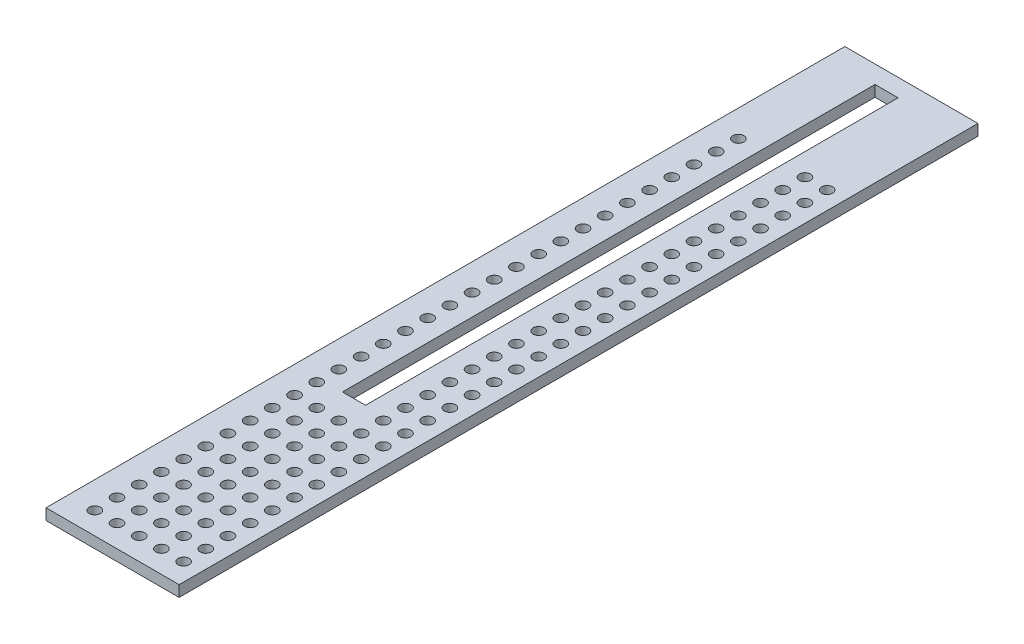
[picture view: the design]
ISO-10303-21;
HEADER;
FILE_DESCRIPTION(('STEP AP214'),'2;1');
FILE_NAME('part.step','',(''),(''),'','','');
FILE_SCHEMA(('AUTOMOTIVE_DESIGN { 1 0 10303 214 1 1 1 1 }'));
ENDSEC;
DATA;
#1=APPLICATION_CONTEXT('core data for automotive mechanical design processes');
#2=APPLICATION_PROTOCOL_DEFINITION('international standard','automotive_design',2000,#1);
#3=PRODUCT_CONTEXT('',#1,'mechanical');
#4=PRODUCT('Part','Part','',(#3));
#5=PRODUCT_RELATED_PRODUCT_CATEGORY('part','',(#4));
#6=PRODUCT_DEFINITION_FORMATION('','',#4);
#7=PRODUCT_DEFINITION_CONTEXT('part definition',#1,'design');
#8=PRODUCT_DEFINITION('design','',#6,#7);
#9=PRODUCT_DEFINITION_SHAPE('','',#8);
#10=(LENGTH_UNIT() NAMED_UNIT(*) SI_UNIT(.MILLI.,.METRE.));
#11=(NAMED_UNIT(*) PLANE_ANGLE_UNIT() SI_UNIT($,.RADIAN.));
#12=(NAMED_UNIT(*) SI_UNIT($,.STERADIAN.) SOLID_ANGLE_UNIT());
#13=UNCERTAINTY_MEASURE_WITH_UNIT(LENGTH_MEASURE(1.E-05),#10,'distance_accuracy_value','');
#14=(GEOMETRIC_REPRESENTATION_CONTEXT(3) GLOBAL_UNCERTAINTY_ASSIGNED_CONTEXT((#13)) GLOBAL_UNIT_ASSIGNED_CONTEXT((#10,
#11,#12)) REPRESENTATION_CONTEXT('',''));
#15=CARTESIAN_POINT('',(0.,0.,0.));
#16=DIRECTION('',(0.,0.,1.));
#17=DIRECTION('',(1.,0.,0.));
#18=AXIS2_PLACEMENT_3D('',#15,#16,#17);
#19=CARTESIAN_POINT('',(-1.58749999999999,50.7999999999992,228.6));
#20=DIRECTION('',(0.,-1.,0.));
#21=DIRECTION('',(1.,0.,0.));
#22=AXIS2_PLACEMENT_3D('',#19,#20,#21);
#23=PLANE('',#22);
#24=CARTESIAN_POINT('',(12.3825,50.7999999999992,222.25));
#25=DIRECTION('',(0.,1.,0.));
#26=DIRECTION('',(-1.,0.,0.));
#27=AXIS2_PLACEMENT_3D('',#24,#25,#26);
#28=CIRCLE('',#27,1.5875);
#29=CARTESIAN_POINT('',(10.795,50.7999999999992,222.25));
#30=VERTEX_POINT('',#29);
#31=EDGE_CURVE('E152',#30,#30,#28,.T.);
#32=ORIENTED_EDGE('',*,*,#31,.F.);
#33=EDGE_LOOP('',(#32));
#34=FACE_BOUND('',#33,.T.);
#35=CARTESIAN_POINT('',(18.7325,50.7999999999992,222.25));
#36=DIRECTION('',(0.,1.,0.));
#37=DIRECTION('',(-1.,0.,0.));
#38=AXIS2_PLACEMENT_3D('',#35,#36,#37);
#39=CIRCLE('',#38,1.5875);
#40=CARTESIAN_POINT('',(17.145,50.7999999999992,222.25));
#41=VERTEX_POINT('',#40);
#42=EDGE_CURVE('E156',#41,#41,#39,.T.);
#43=ORIENTED_EDGE('',*,*,#42,.F.);
#44=EDGE_LOOP('',(#43));
#45=FACE_BOUND('',#44,.T.);
#46=CARTESIAN_POINT('',(25.0825,50.7999999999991,222.25));
#47=DIRECTION('',(0.,1.,0.));
#48=DIRECTION('',(-1.,0.,0.));
#49=AXIS2_PLACEMENT_3D('',#46,#47,#48);
#50=CIRCLE('',#49,1.5875);
#51=CARTESIAN_POINT('',(23.495,50.7999999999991,222.25));
#52=VERTEX_POINT('',#51);
#53=EDGE_CURVE('E160',#52,#52,#50,.T.);
#54=ORIENTED_EDGE('',*,*,#53,.F.);
#55=EDGE_LOOP('',(#54));
#56=FACE_BOUND('',#55,.T.);
#57=CARTESIAN_POINT('',(31.4325,50.7999999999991,222.25));
#58=DIRECTION('',(0.,1.,0.));
#59=DIRECTION('',(-1.,0.,0.));
#60=AXIS2_PLACEMENT_3D('',#57,#58,#59);
#61=CIRCLE('',#60,1.5875);
#62=CARTESIAN_POINT('',(29.845,50.7999999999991,222.25));
#63=VERTEX_POINT('',#62);
#64=EDGE_CURVE('E164',#63,#63,#61,.T.);
#65=ORIENTED_EDGE('',*,*,#64,.F.);
#66=EDGE_LOOP('',(#65));
#67=FACE_BOUND('',#66,.T.);
#68=CARTESIAN_POINT('',(12.3825,50.7999999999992,215.9));
#69=DIRECTION('',(0.,1.,0.));
#70=DIRECTION('',(-1.,0.,0.));
#71=AXIS2_PLACEMENT_3D('',#68,#69,#70);
#72=CIRCLE('',#71,1.5875);
#73=CARTESIAN_POINT('',(10.795,50.7999999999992,215.9));
#74=VERTEX_POINT('',#73);
#75=EDGE_CURVE('E168',#74,#74,#72,.T.);
#76=ORIENTED_EDGE('',*,*,#75,.F.);
#77=EDGE_LOOP('',(#76));
#78=FACE_BOUND('',#77,.T.);
#79=CARTESIAN_POINT('',(18.7325,50.7999999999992,215.9));
#80=DIRECTION('',(0.,1.,0.));
#81=DIRECTION('',(-1.,0.,0.));
#82=AXIS2_PLACEMENT_3D('',#79,#80,#81);
#83=CIRCLE('',#82,1.5875);
#84=CARTESIAN_POINT('',(17.145,50.7999999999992,215.9));
#85=VERTEX_POINT('',#84);
#86=EDGE_CURVE('E172',#85,#85,#83,.T.);
#87=ORIENTED_EDGE('',*,*,#86,.F.);
#88=EDGE_LOOP('',(#87));
#89=FACE_BOUND('',#88,.T.);
#90=CARTESIAN_POINT('',(25.0825,50.7999999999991,215.9));
#91=DIRECTION('',(0.,1.,0.));
#92=DIRECTION('',(-1.,0.,0.));
#93=AXIS2_PLACEMENT_3D('',#90,#91,#92);
#94=CIRCLE('',#93,1.5875);
#95=CARTESIAN_POINT('',(23.495,50.7999999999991,215.9));
#96=VERTEX_POINT('',#95);
#97=EDGE_CURVE('E176',#96,#96,#94,.T.);
#98=ORIENTED_EDGE('',*,*,#97,.F.);
#99=EDGE_LOOP('',(#98));
#100=FACE_BOUND('',#99,.T.);
#101=CARTESIAN_POINT('',(31.4325,50.7999999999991,215.9));
#102=DIRECTION('',(0.,1.,0.));
#103=DIRECTION('',(-1.,0.,0.));
#104=AXIS2_PLACEMENT_3D('',#101,#102,#103);
#105=CIRCLE('',#104,1.58750000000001);
#106=CARTESIAN_POINT('',(29.845,50.7999999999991,215.9));
#107=VERTEX_POINT('',#106);
#108=EDGE_CURVE('E180',#107,#107,#105,.T.);
#109=ORIENTED_EDGE('',*,*,#108,.F.);
#110=EDGE_LOOP('',(#109));
#111=FACE_BOUND('',#110,.T.);
#112=CARTESIAN_POINT('',(12.3825,50.7999999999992,209.55));
#113=DIRECTION('',(0.,1.,0.));
#114=DIRECTION('',(-1.,0.,0.));
#115=AXIS2_PLACEMENT_3D('',#112,#113,#114);
#116=CIRCLE('',#115,1.5875);
#117=CARTESIAN_POINT('',(10.795,50.7999999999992,209.55));
#118=VERTEX_POINT('',#117);
#119=EDGE_CURVE('E184',#118,#118,#116,.T.);
#120=ORIENTED_EDGE('',*,*,#119,.F.);
#121=EDGE_LOOP('',(#120));
#122=FACE_BOUND('',#121,.T.);
#123=CARTESIAN_POINT('',(18.7325,50.7999999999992,209.55));
#124=DIRECTION('',(0.,1.,0.));
#125=DIRECTION('',(-1.,0.,0.));
#126=AXIS2_PLACEMENT_3D('',#123,#124,#125);
#127=CIRCLE('',#126,1.5875);
#128=CARTESIAN_POINT('',(17.145,50.7999999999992,209.55));
#129=VERTEX_POINT('',#128);
#130=EDGE_CURVE('E188',#129,#129,#127,.T.);
#131=ORIENTED_EDGE('',*,*,#130,.F.);
#132=EDGE_LOOP('',(#131));
#133=FACE_BOUND('',#132,.T.);
#134=CARTESIAN_POINT('',(25.0825,50.7999999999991,209.55));
#135=DIRECTION('',(0.,1.,0.));
#136=DIRECTION('',(-1.,0.,0.));
#137=AXIS2_PLACEMENT_3D('',#134,#135,#136);
#138=CIRCLE('',#137,1.5875);
#139=CARTESIAN_POINT('',(23.495,50.7999999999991,209.55));
#140=VERTEX_POINT('',#139);
#141=EDGE_CURVE('E192',#140,#140,#138,.T.);
#142=ORIENTED_EDGE('',*,*,#141,.F.);
#143=EDGE_LOOP('',(#142));
#144=FACE_BOUND('',#143,.T.);
#145=CARTESIAN_POINT('',(31.4325,50.7999999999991,209.55));
#146=DIRECTION('',(0.,1.,0.));
#147=DIRECTION('',(-1.,0.,0.));
#148=AXIS2_PLACEMENT_3D('',#145,#146,#147);
#149=CIRCLE('',#148,1.5875);
#150=CARTESIAN_POINT('',(29.845,50.7999999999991,209.55));
#151=VERTEX_POINT('',#150);
#152=EDGE_CURVE('E196',#151,#151,#149,.T.);
#153=ORIENTED_EDGE('',*,*,#152,.F.);
#154=EDGE_LOOP('',(#153));
#155=FACE_BOUND('',#154,.T.);
#156=CARTESIAN_POINT('',(12.3824999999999,50.7999999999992,203.2));
#157=DIRECTION('',(0.,1.,0.));
#158=DIRECTION('',(-1.,0.,0.));
#159=AXIS2_PLACEMENT_3D('',#156,#157,#158);
#160=CIRCLE('',#159,1.5875);
#161=CARTESIAN_POINT('',(10.7949999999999,50.7999999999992,203.2));
#162=VERTEX_POINT('',#161);
#163=EDGE_CURVE('E200',#162,#162,#160,.T.);
#164=ORIENTED_EDGE('',*,*,#163,.F.);
#165=EDGE_LOOP('',(#164));
#166=FACE_BOUND('',#165,.T.);
#167=CARTESIAN_POINT('',(18.7324999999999,50.7999999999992,203.2));
#168=DIRECTION('',(0.,1.,0.));
#169=DIRECTION('',(-1.,0.,0.));
#170=AXIS2_PLACEMENT_3D('',#167,#168,#169);
#171=CIRCLE('',#170,1.5875);
#172=CARTESIAN_POINT('',(17.1449999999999,50.7999999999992,203.2));
#173=VERTEX_POINT('',#172);
#174=EDGE_CURVE('E204',#173,#173,#171,.T.);
#175=ORIENTED_EDGE('',*,*,#174,.F.);
#176=EDGE_LOOP('',(#175));
#177=FACE_BOUND('',#176,.T.);
#178=CARTESIAN_POINT('',(25.0824999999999,50.7999999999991,203.2));
#179=DIRECTION('',(0.,1.,0.));
#180=DIRECTION('',(-1.,0.,0.));
#181=AXIS2_PLACEMENT_3D('',#178,#179,#180);
#182=CIRCLE('',#181,1.5875);
#183=CARTESIAN_POINT('',(23.4949999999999,50.7999999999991,203.2));
#184=VERTEX_POINT('',#183);
#185=EDGE_CURVE('E208',#184,#184,#182,.T.);
#186=ORIENTED_EDGE('',*,*,#185,.F.);
#187=EDGE_LOOP('',(#186));
#188=FACE_BOUND('',#187,.T.);
#189=CARTESIAN_POINT('',(31.4324999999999,50.7999999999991,203.2));
#190=DIRECTION('',(0.,1.,0.));
#191=DIRECTION('',(-1.,0.,0.));
#192=AXIS2_PLACEMENT_3D('',#189,#190,#191);
#193=CIRCLE('',#192,1.5875);
#194=CARTESIAN_POINT('',(29.8449999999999,50.7999999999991,203.2));
#195=VERTEX_POINT('',#194);
#196=EDGE_CURVE('E212',#195,#195,#193,.T.);
#197=ORIENTED_EDGE('',*,*,#196,.F.);
#198=EDGE_LOOP('',(#197));
#199=FACE_BOUND('',#198,.T.);
#200=CARTESIAN_POINT('',(12.3824999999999,50.7999999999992,196.85));
#201=DIRECTION('',(0.,1.,0.));
#202=DIRECTION('',(-1.,0.,0.));
#203=AXIS2_PLACEMENT_3D('',#200,#201,#202);
#204=CIRCLE('',#203,1.5875);
#205=CARTESIAN_POINT('',(10.7949999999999,50.7999999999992,196.85));
#206=VERTEX_POINT('',#205);
#207=EDGE_CURVE('E216',#206,#206,#204,.T.);
#208=ORIENTED_EDGE('',*,*,#207,.F.);
#209=EDGE_LOOP('',(#208));
#210=FACE_BOUND('',#209,.T.);
#211=CARTESIAN_POINT('',(18.7324999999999,50.7999999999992,196.85));
#212=DIRECTION('',(0.,1.,0.));
#213=DIRECTION('',(-1.,0.,0.));
#214=AXIS2_PLACEMENT_3D('',#211,#212,#213);
#215=CIRCLE('',#214,1.5875);
#216=CARTESIAN_POINT('',(17.1449999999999,50.7999999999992,196.85));
#217=VERTEX_POINT('',#216);
#218=EDGE_CURVE('E220',#217,#217,#215,.T.);
#219=ORIENTED_EDGE('',*,*,#218,.F.);
#220=EDGE_LOOP('',(#219));
#221=FACE_BOUND('',#220,.T.);
#222=CARTESIAN_POINT('',(25.0824999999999,50.7999999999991,196.85));
#223=DIRECTION('',(0.,1.,0.));
#224=DIRECTION('',(-1.,0.,0.));
#225=AXIS2_PLACEMENT_3D('',#222,#223,#224);
#226=CIRCLE('',#225,1.5875);
#227=CARTESIAN_POINT('',(23.4949999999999,50.7999999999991,196.85));
#228=VERTEX_POINT('',#227);
#229=EDGE_CURVE('E224',#228,#228,#226,.T.);
#230=ORIENTED_EDGE('',*,*,#229,.F.);
#231=EDGE_LOOP('',(#230));
#232=FACE_BOUND('',#231,.T.);
#233=CARTESIAN_POINT('',(31.4324999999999,50.7999999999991,196.85));
#234=DIRECTION('',(0.,1.,0.));
#235=DIRECTION('',(-1.,0.,0.));
#236=AXIS2_PLACEMENT_3D('',#233,#234,#235);
#237=CIRCLE('',#236,1.58750000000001);
#238=CARTESIAN_POINT('',(29.8449999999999,50.7999999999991,196.85));
#239=VERTEX_POINT('',#238);
#240=EDGE_CURVE('E228',#239,#239,#237,.T.);
#241=ORIENTED_EDGE('',*,*,#240,.F.);
#242=EDGE_LOOP('',(#241));
#243=FACE_BOUND('',#242,.T.);
#244=CARTESIAN_POINT('',(12.3824999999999,50.7999999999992,190.5));
#245=DIRECTION('',(0.,1.,0.));
#246=DIRECTION('',(-1.,0.,0.));
#247=AXIS2_PLACEMENT_3D('',#244,#245,#246);
#248=CIRCLE('',#247,1.5875);
#249=CARTESIAN_POINT('',(10.7949999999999,50.7999999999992,190.5));
#250=VERTEX_POINT('',#249);
#251=EDGE_CURVE('E232',#250,#250,#248,.T.);
#252=ORIENTED_EDGE('',*,*,#251,.F.);
#253=EDGE_LOOP('',(#252));
#254=FACE_BOUND('',#253,.T.);
#255=CARTESIAN_POINT('',(18.7324999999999,50.7999999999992,190.5));
#256=DIRECTION('',(0.,1.,0.));
#257=DIRECTION('',(-1.,0.,0.));
#258=AXIS2_PLACEMENT_3D('',#255,#256,#257);
#259=CIRCLE('',#258,1.5875);
#260=CARTESIAN_POINT('',(17.1449999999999,50.7999999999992,190.5));
#261=VERTEX_POINT('',#260);
#262=EDGE_CURVE('E236',#261,#261,#259,.T.);
#263=ORIENTED_EDGE('',*,*,#262,.F.);
#264=EDGE_LOOP('',(#263));
#265=FACE_BOUND('',#264,.T.);
#266=CARTESIAN_POINT('',(25.0824999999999,50.7999999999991,190.5));
#267=DIRECTION('',(0.,1.,0.));
#268=DIRECTION('',(-1.,0.,0.));
#269=AXIS2_PLACEMENT_3D('',#266,#267,#268);
#270=CIRCLE('',#269,1.5875);
#271=CARTESIAN_POINT('',(23.4949999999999,50.7999999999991,190.5));
#272=VERTEX_POINT('',#271);
#273=EDGE_CURVE('E240',#272,#272,#270,.T.);
#274=ORIENTED_EDGE('',*,*,#273,.F.);
#275=EDGE_LOOP('',(#274));
#276=FACE_BOUND('',#275,.T.);
#277=CARTESIAN_POINT('',(31.4324999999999,50.7999999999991,190.5));
#278=DIRECTION('',(0.,1.,0.));
#279=DIRECTION('',(-1.,0.,0.));
#280=AXIS2_PLACEMENT_3D('',#277,#278,#279);
#281=CIRCLE('',#280,1.5875);
#282=CARTESIAN_POINT('',(29.8449999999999,50.7999999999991,190.5));
#283=VERTEX_POINT('',#282);
#284=EDGE_CURVE('E244',#283,#283,#281,.T.);
#285=ORIENTED_EDGE('',*,*,#284,.F.);
#286=EDGE_LOOP('',(#285));
#287=FACE_BOUND('',#286,.T.);
#288=CARTESIAN_POINT('',(12.3824999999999,50.7999999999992,184.15));
#289=DIRECTION('',(0.,1.,0.));
#290=DIRECTION('',(-1.,0.,0.));
#291=AXIS2_PLACEMENT_3D('',#288,#289,#290);
#292=CIRCLE('',#291,1.5875);
#293=CARTESIAN_POINT('',(10.7949999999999,50.7999999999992,184.15));
#294=VERTEX_POINT('',#293);
#295=EDGE_CURVE('E248',#294,#294,#292,.T.);
#296=ORIENTED_EDGE('',*,*,#295,.F.);
#297=EDGE_LOOP('',(#296));
#298=FACE_BOUND('',#297,.T.);
#299=CARTESIAN_POINT('',(18.7324999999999,50.7999999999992,184.15));
#300=DIRECTION('',(0.,1.,0.));
#301=DIRECTION('',(-1.,0.,0.));
#302=AXIS2_PLACEMENT_3D('',#299,#300,#301);
#303=CIRCLE('',#302,1.5875);
#304=CARTESIAN_POINT('',(17.1449999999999,50.7999999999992,184.15));
#305=VERTEX_POINT('',#304);
#306=EDGE_CURVE('E252',#305,#305,#303,.T.);
#307=ORIENTED_EDGE('',*,*,#306,.F.);
#308=EDGE_LOOP('',(#307));
#309=FACE_BOUND('',#308,.T.);
#310=CARTESIAN_POINT('',(25.0824999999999,50.7999999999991,184.15));
#311=DIRECTION('',(0.,1.,0.));
#312=DIRECTION('',(-1.,0.,0.));
#313=AXIS2_PLACEMENT_3D('',#310,#311,#312);
#314=CIRCLE('',#313,1.5875);
#315=CARTESIAN_POINT('',(23.4949999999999,50.7999999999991,184.15));
#316=VERTEX_POINT('',#315);
#317=EDGE_CURVE('E256',#316,#316,#314,.T.);
#318=ORIENTED_EDGE('',*,*,#317,.F.);
#319=EDGE_LOOP('',(#318));
#320=FACE_BOUND('',#319,.T.);
#321=CARTESIAN_POINT('',(31.4324999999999,50.7999999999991,184.15));
#322=DIRECTION('',(0.,1.,0.));
#323=DIRECTION('',(-1.,0.,0.));
#324=AXIS2_PLACEMENT_3D('',#321,#322,#323);
#325=CIRCLE('',#324,1.58750000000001);
#326=CARTESIAN_POINT('',(29.8449999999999,50.7999999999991,184.15));
#327=VERTEX_POINT('',#326);
#328=EDGE_CURVE('E260',#327,#327,#325,.T.);
#329=ORIENTED_EDGE('',*,*,#328,.F.);
#330=EDGE_LOOP('',(#329));
#331=FACE_BOUND('',#330,.T.);
#332=CARTESIAN_POINT('',(12.3824999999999,50.7999999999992,177.8));
#333=DIRECTION('',(0.,1.,0.));
#334=DIRECTION('',(-1.,0.,0.));
#335=AXIS2_PLACEMENT_3D('',#332,#333,#334);
#336=CIRCLE('',#335,1.5875);
#337=CARTESIAN_POINT('',(10.7949999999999,50.7999999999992,177.8));
#338=VERTEX_POINT('',#337);
#339=EDGE_CURVE('E264',#338,#338,#336,.T.);
#340=ORIENTED_EDGE('',*,*,#339,.F.);
#341=EDGE_LOOP('',(#340));
#342=FACE_BOUND('',#341,.T.);
#343=CARTESIAN_POINT('',(18.7324999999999,50.7999999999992,177.8));
#344=DIRECTION('',(0.,1.,0.));
#345=DIRECTION('',(-1.,0.,0.));
#346=AXIS2_PLACEMENT_3D('',#343,#344,#345);
#347=CIRCLE('',#346,1.5875);
#348=CARTESIAN_POINT('',(17.1449999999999,50.7999999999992,177.8));
#349=VERTEX_POINT('',#348);
#350=EDGE_CURVE('E268',#349,#349,#347,.T.);
#351=ORIENTED_EDGE('',*,*,#350,.F.);
#352=EDGE_LOOP('',(#351));
#353=FACE_BOUND('',#352,.T.);
#354=CARTESIAN_POINT('',(25.0824999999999,50.7999999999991,177.8));
#355=DIRECTION('',(0.,1.,0.));
#356=DIRECTION('',(-1.,0.,0.));
#357=AXIS2_PLACEMENT_3D('',#354,#355,#356);
#358=CIRCLE('',#357,1.5875);
#359=CARTESIAN_POINT('',(23.4949999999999,50.7999999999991,177.8));
#360=VERTEX_POINT('',#359);
#361=EDGE_CURVE('E272',#360,#360,#358,.T.);
#362=ORIENTED_EDGE('',*,*,#361,.F.);
#363=EDGE_LOOP('',(#362));
#364=FACE_BOUND('',#363,.T.);
#365=CARTESIAN_POINT('',(31.4324999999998,50.7999999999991,177.8));
#366=DIRECTION('',(0.,1.,0.));
#367=DIRECTION('',(-1.,0.,0.));
#368=AXIS2_PLACEMENT_3D('',#365,#366,#367);
#369=CIRCLE('',#368,1.5875);
#370=CARTESIAN_POINT('',(29.8449999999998,50.7999999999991,177.8));
#371=VERTEX_POINT('',#370);
#372=EDGE_CURVE('E276',#371,#371,#369,.T.);
#373=ORIENTED_EDGE('',*,*,#372,.F.);
#374=EDGE_LOOP('',(#373));
#375=FACE_BOUND('',#374,.T.);
#376=CARTESIAN_POINT('',(12.3824999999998,50.7999999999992,171.45));
#377=DIRECTION('',(0.,1.,0.));
#378=DIRECTION('',(-1.,0.,0.));
#379=AXIS2_PLACEMENT_3D('',#376,#377,#378);
#380=CIRCLE('',#379,1.5875);
#381=CARTESIAN_POINT('',(10.7949999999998,50.7999999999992,171.45));
#382=VERTEX_POINT('',#381);
#383=EDGE_CURVE('E280',#382,#382,#380,.T.);
#384=ORIENTED_EDGE('',*,*,#383,.F.);
#385=EDGE_LOOP('',(#384));
#386=FACE_BOUND('',#385,.T.);
#387=CARTESIAN_POINT('',(18.7324999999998,50.7999999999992,171.45));
#388=DIRECTION('',(0.,1.,0.));
#389=DIRECTION('',(-1.,0.,0.));
#390=AXIS2_PLACEMENT_3D('',#387,#388,#389);
#391=CIRCLE('',#390,1.5875);
#392=CARTESIAN_POINT('',(17.1449999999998,50.7999999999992,171.45));
#393=VERTEX_POINT('',#392);
#394=EDGE_CURVE('E284',#393,#393,#391,.T.);
#395=ORIENTED_EDGE('',*,*,#394,.F.);
#396=EDGE_LOOP('',(#395));
#397=FACE_BOUND('',#396,.T.);
#398=CARTESIAN_POINT('',(25.0824999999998,50.7999999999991,171.45));
#399=DIRECTION('',(0.,1.,0.));
#400=DIRECTION('',(-1.,0.,0.));
#401=AXIS2_PLACEMENT_3D('',#398,#399,#400);
#402=CIRCLE('',#401,1.5875);
#403=CARTESIAN_POINT('',(23.4949999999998,50.7999999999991,171.45));
#404=VERTEX_POINT('',#403);
#405=EDGE_CURVE('E288',#404,#404,#402,.T.);
#406=ORIENTED_EDGE('',*,*,#405,.F.);
#407=EDGE_LOOP('',(#406));
#408=FACE_BOUND('',#407,.T.);
#409=CARTESIAN_POINT('',(31.4324999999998,50.7999999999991,171.45));
#410=DIRECTION('',(0.,1.,0.));
#411=DIRECTION('',(-1.,0.,0.));
#412=AXIS2_PLACEMENT_3D('',#409,#410,#411);
#413=CIRCLE('',#412,1.5875);
#414=CARTESIAN_POINT('',(29.8449999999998,50.7999999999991,171.45));
#415=VERTEX_POINT('',#414);
#416=EDGE_CURVE('E292',#415,#415,#413,.T.);
#417=ORIENTED_EDGE('',*,*,#416,.F.);
#418=EDGE_LOOP('',(#417));
#419=FACE_BOUND('',#418,.T.);
#420=CARTESIAN_POINT('',(12.3824999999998,50.7999999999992,165.1));
#421=DIRECTION('',(0.,1.,0.));
#422=DIRECTION('',(-1.,0.,0.));
#423=AXIS2_PLACEMENT_3D('',#420,#421,#422);
#424=CIRCLE('',#423,1.5875);
#425=CARTESIAN_POINT('',(10.7949999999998,50.7999999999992,165.1));
#426=VERTEX_POINT('',#425);
#427=EDGE_CURVE('E296',#426,#426,#424,.T.);
#428=ORIENTED_EDGE('',*,*,#427,.F.);
#429=EDGE_LOOP('',(#428));
#430=FACE_BOUND('',#429,.T.);
#431=CARTESIAN_POINT('',(18.7324999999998,50.7999999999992,165.1));
#432=DIRECTION('',(0.,1.,0.));
#433=DIRECTION('',(-1.,0.,0.));
#434=AXIS2_PLACEMENT_3D('',#431,#432,#433);
#435=CIRCLE('',#434,1.5875);
#436=CARTESIAN_POINT('',(17.1449999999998,50.7999999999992,165.1));
#437=VERTEX_POINT('',#436);
#438=EDGE_CURVE('E300',#437,#437,#435,.T.);
#439=ORIENTED_EDGE('',*,*,#438,.F.);
#440=EDGE_LOOP('',(#439));
#441=FACE_BOUND('',#440,.T.);
#442=CARTESIAN_POINT('',(25.0824999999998,50.7999999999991,165.1));
#443=DIRECTION('',(0.,1.,0.));
#444=DIRECTION('',(-1.,0.,0.));
#445=AXIS2_PLACEMENT_3D('',#442,#443,#444);
#446=CIRCLE('',#445,1.5875);
#447=CARTESIAN_POINT('',(23.4949999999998,50.7999999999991,165.1));
#448=VERTEX_POINT('',#447);
#449=EDGE_CURVE('E304',#448,#448,#446,.T.);
#450=ORIENTED_EDGE('',*,*,#449,.F.);
#451=EDGE_LOOP('',(#450));
#452=FACE_BOUND('',#451,.T.);
#453=CARTESIAN_POINT('',(31.4324999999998,50.7999999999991,165.1));
#454=DIRECTION('',(0.,1.,0.));
#455=DIRECTION('',(-1.,0.,0.));
#456=AXIS2_PLACEMENT_3D('',#453,#454,#455);
#457=CIRCLE('',#456,1.58750000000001);
#458=CARTESIAN_POINT('',(29.8449999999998,50.7999999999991,165.1));
#459=VERTEX_POINT('',#458);
#460=EDGE_CURVE('E308',#459,#459,#457,.T.);
#461=ORIENTED_EDGE('',*,*,#460,.F.);
#462=EDGE_LOOP('',(#461));
#463=FACE_BOUND('',#462,.T.);
#464=CARTESIAN_POINT('',(25.0824999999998,50.7999999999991,158.75));
#465=DIRECTION('',(0.,1.,0.));
#466=DIRECTION('',(-1.,0.,0.));
#467=AXIS2_PLACEMENT_3D('',#464,#465,#466);
#468=CIRCLE('',#467,1.5875);
#469=CARTESIAN_POINT('',(23.4949999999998,50.7999999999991,158.75));
#470=VERTEX_POINT('',#469);
#471=EDGE_CURVE('E312',#470,#470,#468,.T.);
#472=ORIENTED_EDGE('',*,*,#471,.F.);
#473=EDGE_LOOP('',(#472));
#474=FACE_BOUND('',#473,.T.);
#475=CARTESIAN_POINT('',(31.4324999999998,50.7999999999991,158.75));
#476=DIRECTION('',(0.,1.,0.));
#477=DIRECTION('',(-1.,0.,0.));
#478=AXIS2_PLACEMENT_3D('',#475,#476,#477);
#479=CIRCLE('',#478,1.5875);
#480=CARTESIAN_POINT('',(29.8449999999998,50.7999999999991,158.75));
#481=VERTEX_POINT('',#480);
#482=EDGE_CURVE('E316',#481,#481,#479,.T.);
#483=ORIENTED_EDGE('',*,*,#482,.F.);
#484=EDGE_LOOP('',(#483));
#485=FACE_BOUND('',#484,.T.);
#486=CARTESIAN_POINT('',(25.0824999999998,50.7999999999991,152.4));
#487=DIRECTION('',(0.,1.,0.));
#488=DIRECTION('',(-1.,0.,0.));
#489=AXIS2_PLACEMENT_3D('',#486,#487,#488);
#490=CIRCLE('',#489,1.5875);
#491=CARTESIAN_POINT('',(23.4949999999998,50.7999999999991,152.4));
#492=VERTEX_POINT('',#491);
#493=EDGE_CURVE('E320',#492,#492,#490,.T.);
#494=ORIENTED_EDGE('',*,*,#493,.F.);
#495=EDGE_LOOP('',(#494));
#496=FACE_BOUND('',#495,.T.);
#497=CARTESIAN_POINT('',(31.4324999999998,50.7999999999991,152.4));
#498=DIRECTION('',(0.,1.,0.));
#499=DIRECTION('',(-1.,0.,0.));
#500=AXIS2_PLACEMENT_3D('',#497,#498,#499);
#501=CIRCLE('',#500,1.58750000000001);
#502=CARTESIAN_POINT('',(29.8449999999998,50.7999999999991,152.4));
#503=VERTEX_POINT('',#502);
#504=EDGE_CURVE('E324',#503,#503,#501,.T.);
#505=ORIENTED_EDGE('',*,*,#504,.F.);
#506=EDGE_LOOP('',(#505));
#507=FACE_BOUND('',#506,.T.);
#508=CARTESIAN_POINT('',(25.0824999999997,50.7999999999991,146.05));
#509=DIRECTION('',(0.,1.,0.));
#510=DIRECTION('',(-1.,0.,0.));
#511=AXIS2_PLACEMENT_3D('',#508,#509,#510);
#512=CIRCLE('',#511,1.5875);
#513=CARTESIAN_POINT('',(23.4949999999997,50.7999999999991,146.05));
#514=VERTEX_POINT('',#513);
#515=EDGE_CURVE('E328',#514,#514,#512,.T.);
#516=ORIENTED_EDGE('',*,*,#515,.F.);
#517=EDGE_LOOP('',(#516));
#518=FACE_BOUND('',#517,.T.);
#519=CARTESIAN_POINT('',(31.4324999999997,50.7999999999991,146.05));
#520=DIRECTION('',(0.,1.,0.));
#521=DIRECTION('',(-1.,0.,0.));
#522=AXIS2_PLACEMENT_3D('',#519,#520,#521);
#523=CIRCLE('',#522,1.5875);
#524=CARTESIAN_POINT('',(29.8449999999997,50.7999999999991,146.05));
#525=VERTEX_POINT('',#524);
#526=EDGE_CURVE('E332',#525,#525,#523,.T.);
#527=ORIENTED_EDGE('',*,*,#526,.F.);
#528=EDGE_LOOP('',(#527));
#529=FACE_BOUND('',#528,.T.);
#530=CARTESIAN_POINT('',(25.0824999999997,50.7999999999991,139.7));
#531=DIRECTION('',(0.,1.,0.));
#532=DIRECTION('',(-1.,0.,0.));
#533=AXIS2_PLACEMENT_3D('',#530,#531,#532);
#534=CIRCLE('',#533,1.5875);
#535=CARTESIAN_POINT('',(23.4949999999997,50.7999999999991,139.7));
#536=VERTEX_POINT('',#535);
#537=EDGE_CURVE('E336',#536,#536,#534,.T.);
#538=ORIENTED_EDGE('',*,*,#537,.F.);
#539=EDGE_LOOP('',(#538));
#540=FACE_BOUND('',#539,.T.);
#541=CARTESIAN_POINT('',(31.4324999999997,50.7999999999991,139.7));
#542=DIRECTION('',(0.,1.,0.));
#543=DIRECTION('',(-1.,0.,0.));
#544=AXIS2_PLACEMENT_3D('',#541,#542,#543);
#545=CIRCLE('',#544,1.5875);
#546=CARTESIAN_POINT('',(29.8449999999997,50.7999999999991,139.7));
#547=VERTEX_POINT('',#546);
#548=EDGE_CURVE('E340',#547,#547,#545,.T.);
#549=ORIENTED_EDGE('',*,*,#548,.F.);
#550=EDGE_LOOP('',(#549));
#551=FACE_BOUND('',#550,.T.);
#552=CARTESIAN_POINT('',(25.0824999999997,50.7999999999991,133.35));
#553=DIRECTION('',(0.,1.,0.));
#554=DIRECTION('',(-1.,0.,0.));
#555=AXIS2_PLACEMENT_3D('',#552,#553,#554);
#556=CIRCLE('',#555,1.5875);
#557=CARTESIAN_POINT('',(23.4949999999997,50.7999999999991,133.35));
#558=VERTEX_POINT('',#557);
#559=EDGE_CURVE('E344',#558,#558,#556,.T.);
#560=ORIENTED_EDGE('',*,*,#559,.F.);
#561=EDGE_LOOP('',(#560));
#562=FACE_BOUND('',#561,.T.);
#563=CARTESIAN_POINT('',(31.4324999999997,50.7999999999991,133.35));
#564=DIRECTION('',(0.,1.,0.));
#565=DIRECTION('',(-1.,0.,0.));
#566=AXIS2_PLACEMENT_3D('',#563,#564,#565);
#567=CIRCLE('',#566,1.5875);
#568=CARTESIAN_POINT('',(29.8449999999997,50.7999999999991,133.35));
#569=VERTEX_POINT('',#568);
#570=EDGE_CURVE('E348',#569,#569,#567,.T.);
#571=ORIENTED_EDGE('',*,*,#570,.F.);
#572=EDGE_LOOP('',(#571));
#573=FACE_BOUND('',#572,.T.);
#574=CARTESIAN_POINT('',(25.0824999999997,50.7999999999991,127.));
#575=DIRECTION('',(0.,1.,0.));
#576=DIRECTION('',(-1.,0.,0.));
#577=AXIS2_PLACEMENT_3D('',#574,#575,#576);
#578=CIRCLE('',#577,1.5875);
#579=CARTESIAN_POINT('',(23.4949999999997,50.7999999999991,127.));
#580=VERTEX_POINT('',#579);
#581=EDGE_CURVE('E352',#580,#580,#578,.T.);
#582=ORIENTED_EDGE('',*,*,#581,.F.);
#583=EDGE_LOOP('',(#582));
#584=FACE_BOUND('',#583,.T.);
#585=CARTESIAN_POINT('',(31.4324999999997,50.7999999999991,127.));
#586=DIRECTION('',(0.,1.,0.));
#587=DIRECTION('',(-1.,0.,0.));
#588=AXIS2_PLACEMENT_3D('',#585,#586,#587);
#589=CIRCLE('',#588,1.5875);
#590=CARTESIAN_POINT('',(29.8449999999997,50.7999999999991,127.));
#591=VERTEX_POINT('',#590);
#592=EDGE_CURVE('E356',#591,#591,#589,.T.);
#593=ORIENTED_EDGE('',*,*,#592,.F.);
#594=EDGE_LOOP('',(#593));
#595=FACE_BOUND('',#594,.T.);
#596=CARTESIAN_POINT('',(25.0824999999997,50.7999999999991,120.65));
#597=DIRECTION('',(0.,1.,0.));
#598=DIRECTION('',(-1.,0.,0.));
#599=AXIS2_PLACEMENT_3D('',#596,#597,#598);
#600=CIRCLE('',#599,1.5875);
#601=CARTESIAN_POINT('',(23.4949999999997,50.7999999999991,120.65));
#602=VERTEX_POINT('',#601);
#603=EDGE_CURVE('E360',#602,#602,#600,.T.);
#604=ORIENTED_EDGE('',*,*,#603,.F.);
#605=EDGE_LOOP('',(#604));
#606=FACE_BOUND('',#605,.T.);
#607=CARTESIAN_POINT('',(31.4324999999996,50.7999999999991,120.65));
#608=DIRECTION('',(0.,1.,0.));
#609=DIRECTION('',(-1.,0.,0.));
#610=AXIS2_PLACEMENT_3D('',#607,#608,#609);
#611=CIRCLE('',#610,1.58750000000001);
#612=CARTESIAN_POINT('',(29.8449999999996,50.7999999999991,120.65));
#613=VERTEX_POINT('',#612);
#614=EDGE_CURVE('E364',#613,#613,#611,.T.);
#615=ORIENTED_EDGE('',*,*,#614,.F.);
#616=EDGE_LOOP('',(#615));
#617=FACE_BOUND('',#616,.T.);
#618=CARTESIAN_POINT('',(25.0824999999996,50.7999999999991,114.3));
#619=DIRECTION('',(0.,1.,0.));
#620=DIRECTION('',(-1.,0.,0.));
#621=AXIS2_PLACEMENT_3D('',#618,#619,#620);
#622=CIRCLE('',#621,1.5875);
#623=CARTESIAN_POINT('',(23.4949999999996,50.7999999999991,114.3));
#624=VERTEX_POINT('',#623);
#625=EDGE_CURVE('E368',#624,#624,#622,.T.);
#626=ORIENTED_EDGE('',*,*,#625,.F.);
#627=EDGE_LOOP('',(#626));
#628=FACE_BOUND('',#627,.T.);
#629=CARTESIAN_POINT('',(31.4324999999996,50.7999999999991,114.3));
#630=DIRECTION('',(0.,1.,0.));
#631=DIRECTION('',(-1.,0.,0.));
#632=AXIS2_PLACEMENT_3D('',#629,#630,#631);
#633=CIRCLE('',#632,1.5875);
#634=CARTESIAN_POINT('',(29.8449999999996,50.7999999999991,114.3));
#635=VERTEX_POINT('',#634);
#636=EDGE_CURVE('E372',#635,#635,#633,.T.);
#637=ORIENTED_EDGE('',*,*,#636,.F.);
#638=EDGE_LOOP('',(#637));
#639=FACE_BOUND('',#638,.T.);
#640=CARTESIAN_POINT('',(25.0824999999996,50.7999999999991,107.95));
#641=DIRECTION('',(0.,1.,0.));
#642=DIRECTION('',(-1.,0.,0.));
#643=AXIS2_PLACEMENT_3D('',#640,#641,#642);
#644=CIRCLE('',#643,1.5875);
#645=CARTESIAN_POINT('',(23.4949999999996,50.7999999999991,107.95));
#646=VERTEX_POINT('',#645);
#647=EDGE_CURVE('E376',#646,#646,#644,.T.);
#648=ORIENTED_EDGE('',*,*,#647,.F.);
#649=EDGE_LOOP('',(#648));
#650=FACE_BOUND('',#649,.T.);
#651=CARTESIAN_POINT('',(31.4324999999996,50.7999999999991,107.95));
#652=DIRECTION('',(0.,1.,0.));
#653=DIRECTION('',(-1.,0.,0.));
#654=AXIS2_PLACEMENT_3D('',#651,#652,#653);
#655=CIRCLE('',#654,1.5875);
#656=CARTESIAN_POINT('',(29.8449999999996,50.7999999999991,107.95));
#657=VERTEX_POINT('',#656);
#658=EDGE_CURVE('E380',#657,#657,#655,.T.);
#659=ORIENTED_EDGE('',*,*,#658,.F.);
#660=EDGE_LOOP('',(#659));
#661=FACE_BOUND('',#660,.T.);
#662=CARTESIAN_POINT('',(25.0824999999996,50.7999999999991,101.6));
#663=DIRECTION('',(0.,1.,0.));
#664=DIRECTION('',(-1.,0.,0.));
#665=AXIS2_PLACEMENT_3D('',#662,#663,#664);
#666=CIRCLE('',#665,1.5875);
#667=CARTESIAN_POINT('',(23.4949999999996,50.7999999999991,101.6));
#668=VERTEX_POINT('',#667);
#669=EDGE_CURVE('E384',#668,#668,#666,.T.);
#670=ORIENTED_EDGE('',*,*,#669,.F.);
#671=EDGE_LOOP('',(#670));
#672=FACE_BOUND('',#671,.T.);
#673=CARTESIAN_POINT('',(31.4324999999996,50.7999999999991,101.6));
#674=DIRECTION('',(0.,1.,0.));
#675=DIRECTION('',(-1.,0.,0.));
#676=AXIS2_PLACEMENT_3D('',#673,#674,#675);
#677=CIRCLE('',#676,1.5875);
#678=CARTESIAN_POINT('',(29.8449999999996,50.7999999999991,101.6));
#679=VERTEX_POINT('',#678);
#680=EDGE_CURVE('E388',#679,#679,#677,.T.);
#681=ORIENTED_EDGE('',*,*,#680,.F.);
#682=EDGE_LOOP('',(#681));
#683=FACE_BOUND('',#682,.T.);
#684=CARTESIAN_POINT('',(25.0824999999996,50.7999999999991,95.25));
#685=DIRECTION('',(0.,1.,0.));
#686=DIRECTION('',(-1.,0.,0.));
#687=AXIS2_PLACEMENT_3D('',#684,#685,#686);
#688=CIRCLE('',#687,1.5875);
#689=CARTESIAN_POINT('',(23.4949999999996,50.7999999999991,95.25));
#690=VERTEX_POINT('',#689);
#691=EDGE_CURVE('E392',#690,#690,#688,.T.);
#692=ORIENTED_EDGE('',*,*,#691,.F.);
#693=EDGE_LOOP('',(#692));
#694=FACE_BOUND('',#693,.T.);
#695=CARTESIAN_POINT('',(31.4324999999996,50.7999999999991,95.25));
#696=DIRECTION('',(0.,1.,0.));
#697=DIRECTION('',(-1.,0.,0.));
#698=AXIS2_PLACEMENT_3D('',#695,#696,#697);
#699=CIRCLE('',#698,1.5875);
#700=CARTESIAN_POINT('',(29.8449999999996,50.7999999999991,95.25));
#701=VERTEX_POINT('',#700);
#702=EDGE_CURVE('E396',#701,#701,#699,.T.);
#703=ORIENTED_EDGE('',*,*,#702,.F.);
#704=EDGE_LOOP('',(#703));
#705=FACE_BOUND('',#704,.T.);
#706=CARTESIAN_POINT('',(25.0824999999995,50.7999999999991,88.9));
#707=DIRECTION('',(0.,1.,0.));
#708=DIRECTION('',(-1.,0.,0.));
#709=AXIS2_PLACEMENT_3D('',#706,#707,#708);
#710=CIRCLE('',#709,1.5875);
#711=CARTESIAN_POINT('',(23.4949999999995,50.7999999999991,88.9));
#712=VERTEX_POINT('',#711);
#713=EDGE_CURVE('E400',#712,#712,#710,.T.);
#714=ORIENTED_EDGE('',*,*,#713,.F.);
#715=EDGE_LOOP('',(#714));
#716=FACE_BOUND('',#715,.T.);
#717=CARTESIAN_POINT('',(31.4324999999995,50.7999999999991,88.9));
#718=DIRECTION('',(0.,1.,0.));
#719=DIRECTION('',(-1.,0.,0.));
#720=AXIS2_PLACEMENT_3D('',#717,#718,#719);
#721=CIRCLE('',#720,1.58750000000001);
#722=CARTESIAN_POINT('',(29.8449999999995,50.7999999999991,88.9));
#723=VERTEX_POINT('',#722);
#724=EDGE_CURVE('E404',#723,#723,#721,.T.);
#725=ORIENTED_EDGE('',*,*,#724,.F.);
#726=EDGE_LOOP('',(#725));
#727=FACE_BOUND('',#726,.T.);
#728=CARTESIAN_POINT('',(6.03249999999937,50.7999999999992,38.1));
#729=DIRECTION('',(0.,1.,0.));
#730=DIRECTION('',(-1.,0.,0.));
#731=AXIS2_PLACEMENT_3D('',#728,#729,#730);
#732=CIRCLE('',#731,1.5875);
#733=CARTESIAN_POINT('',(4.44499999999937,50.7999999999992,38.1));
#734=VERTEX_POINT('',#733);
#735=EDGE_CURVE('E117',#734,#734,#732,.T.);
#736=ORIENTED_EDGE('',*,*,#735,.F.);
#737=EDGE_LOOP('',(#736));
#738=FACE_BOUND('',#737,.T.);
#739=CARTESIAN_POINT('',(6.03249999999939,50.7999999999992,44.45));
#740=DIRECTION('',(0.,1.,0.));
#741=DIRECTION('',(-1.,0.,0.));
#742=AXIS2_PLACEMENT_3D('',#739,#740,#741);
#743=CIRCLE('',#742,1.5875);
#744=CARTESIAN_POINT('',(4.44499999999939,50.7999999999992,44.45));
#745=VERTEX_POINT('',#744);
#746=EDGE_CURVE('E411',#745,#745,#743,.T.);
#747=ORIENTED_EDGE('',*,*,#746,.F.);
#748=EDGE_LOOP('',(#747));
#749=FACE_BOUND('',#748,.T.);
#750=CARTESIAN_POINT('',(6.03249999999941,50.7999999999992,50.8));
#751=DIRECTION('',(0.,1.,0.));
#752=DIRECTION('',(-1.,0.,0.));
#753=AXIS2_PLACEMENT_3D('',#750,#751,#752);
#754=CIRCLE('',#753,1.5875);
#755=CARTESIAN_POINT('',(4.44499999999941,50.7999999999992,50.8));
#756=VERTEX_POINT('',#755);
#757=EDGE_CURVE('E415',#756,#756,#754,.T.);
#758=ORIENTED_EDGE('',*,*,#757,.F.);
#759=EDGE_LOOP('',(#758));
#760=FACE_BOUND('',#759,.T.);
#761=CARTESIAN_POINT('',(6.03249999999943,50.7999999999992,57.15));
#762=DIRECTION('',(0.,1.,0.));
#763=DIRECTION('',(-1.,0.,0.));
#764=AXIS2_PLACEMENT_3D('',#761,#762,#763);
#765=CIRCLE('',#764,1.5875);
#766=CARTESIAN_POINT('',(4.44499999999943,50.7999999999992,57.15));
#767=VERTEX_POINT('',#766);
#768=EDGE_CURVE('E419',#767,#767,#765,.T.);
#769=ORIENTED_EDGE('',*,*,#768,.F.);
#770=EDGE_LOOP('',(#769));
#771=FACE_BOUND('',#770,.T.);
#772=CARTESIAN_POINT('',(6.03249999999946,50.7999999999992,63.5));
#773=DIRECTION('',(0.,1.,0.));
#774=DIRECTION('',(-1.,0.,0.));
#775=AXIS2_PLACEMENT_3D('',#772,#773,#774);
#776=CIRCLE('',#775,1.5875);
#777=CARTESIAN_POINT('',(4.44499999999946,50.7999999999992,63.5));
#778=VERTEX_POINT('',#777);
#779=EDGE_CURVE('E423',#778,#778,#776,.T.);
#780=ORIENTED_EDGE('',*,*,#779,.F.);
#781=EDGE_LOOP('',(#780));
#782=FACE_BOUND('',#781,.T.);
#783=CARTESIAN_POINT('',(6.03249999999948,50.7999999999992,69.85));
#784=DIRECTION('',(0.,1.,0.));
#785=DIRECTION('',(-1.,0.,0.));
#786=AXIS2_PLACEMENT_3D('',#783,#784,#785);
#787=CIRCLE('',#786,1.5875);
#788=CARTESIAN_POINT('',(4.44499999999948,50.7999999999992,69.85));
#789=VERTEX_POINT('',#788);
#790=EDGE_CURVE('E427',#789,#789,#787,.T.);
#791=ORIENTED_EDGE('',*,*,#790,.F.);
#792=EDGE_LOOP('',(#791));
#793=FACE_BOUND('',#792,.T.);
#794=CARTESIAN_POINT('',(6.0324999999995,50.7999999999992,76.2));
#795=DIRECTION('',(0.,1.,0.));
#796=DIRECTION('',(-1.,0.,0.));
#797=AXIS2_PLACEMENT_3D('',#794,#795,#796);
#798=CIRCLE('',#797,1.5875);
#799=CARTESIAN_POINT('',(4.4449999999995,50.7999999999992,76.2));
#800=VERTEX_POINT('',#799);
#801=EDGE_CURVE('E431',#800,#800,#798,.T.);
#802=ORIENTED_EDGE('',*,*,#801,.F.);
#803=EDGE_LOOP('',(#802));
#804=FACE_BOUND('',#803,.T.);
#805=CARTESIAN_POINT('',(6.03249999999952,50.7999999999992,82.55));
#806=DIRECTION('',(0.,1.,0.));
#807=DIRECTION('',(-1.,0.,0.));
#808=AXIS2_PLACEMENT_3D('',#805,#806,#807);
#809=CIRCLE('',#808,1.5875);
#810=CARTESIAN_POINT('',(4.44499999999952,50.7999999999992,82.55));
#811=VERTEX_POINT('',#810);
#812=EDGE_CURVE('E435',#811,#811,#809,.T.);
#813=ORIENTED_EDGE('',*,*,#812,.F.);
#814=EDGE_LOOP('',(#813));
#815=FACE_BOUND('',#814,.T.);
#816=CARTESIAN_POINT('',(6.03249999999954,50.7999999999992,88.9));
#817=DIRECTION('',(0.,1.,0.));
#818=DIRECTION('',(-1.,0.,0.));
#819=AXIS2_PLACEMENT_3D('',#816,#817,#818);
#820=CIRCLE('',#819,1.5875);
#821=CARTESIAN_POINT('',(4.44499999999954,50.7999999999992,88.9));
#822=VERTEX_POINT('',#821);
#823=EDGE_CURVE('E439',#822,#822,#820,.T.);
#824=ORIENTED_EDGE('',*,*,#823,.F.);
#825=EDGE_LOOP('',(#824));
#826=FACE_BOUND('',#825,.T.);
#827=CARTESIAN_POINT('',(6.03249999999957,50.7999999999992,95.25));
#828=DIRECTION('',(0.,1.,0.));
#829=DIRECTION('',(-1.,0.,0.));
#830=AXIS2_PLACEMENT_3D('',#827,#828,#829);
#831=CIRCLE('',#830,1.5875);
#832=CARTESIAN_POINT('',(4.44499999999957,50.7999999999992,95.25));
#833=VERTEX_POINT('',#832);
#834=EDGE_CURVE('E443',#833,#833,#831,.T.);
#835=ORIENTED_EDGE('',*,*,#834,.F.);
#836=EDGE_LOOP('',(#835));
#837=FACE_BOUND('',#836,.T.);
#838=CARTESIAN_POINT('',(6.03249999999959,50.7999999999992,101.6));
#839=DIRECTION('',(0.,1.,0.));
#840=DIRECTION('',(-1.,0.,0.));
#841=AXIS2_PLACEMENT_3D('',#838,#839,#840);
#842=CIRCLE('',#841,1.5875);
#843=CARTESIAN_POINT('',(4.44499999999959,50.7999999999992,101.6));
#844=VERTEX_POINT('',#843);
#845=EDGE_CURVE('E447',#844,#844,#842,.T.);
#846=ORIENTED_EDGE('',*,*,#845,.F.);
#847=EDGE_LOOP('',(#846));
#848=FACE_BOUND('',#847,.T.);
#849=CARTESIAN_POINT('',(6.03249999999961,50.7999999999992,107.95));
#850=DIRECTION('',(0.,1.,0.));
#851=DIRECTION('',(-1.,0.,0.));
#852=AXIS2_PLACEMENT_3D('',#849,#850,#851);
#853=CIRCLE('',#852,1.5875);
#854=CARTESIAN_POINT('',(4.44499999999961,50.7999999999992,107.95));
#855=VERTEX_POINT('',#854);
#856=EDGE_CURVE('E451',#855,#855,#853,.T.);
#857=ORIENTED_EDGE('',*,*,#856,.F.);
#858=EDGE_LOOP('',(#857));
#859=FACE_BOUND('',#858,.T.);
#860=CARTESIAN_POINT('',(6.03249999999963,50.7999999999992,114.3));
#861=DIRECTION('',(0.,1.,0.));
#862=DIRECTION('',(-1.,0.,0.));
#863=AXIS2_PLACEMENT_3D('',#860,#861,#862);
#864=CIRCLE('',#863,1.5875);
#865=CARTESIAN_POINT('',(4.44499999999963,50.7999999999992,114.3));
#866=VERTEX_POINT('',#865);
#867=EDGE_CURVE('E455',#866,#866,#864,.T.);
#868=ORIENTED_EDGE('',*,*,#867,.F.);
#869=EDGE_LOOP('',(#868));
#870=FACE_BOUND('',#869,.T.);
#871=CARTESIAN_POINT('',(6.03249999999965,50.7999999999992,120.65));
#872=DIRECTION('',(0.,1.,0.));
#873=DIRECTION('',(-1.,0.,0.));
#874=AXIS2_PLACEMENT_3D('',#871,#872,#873);
#875=CIRCLE('',#874,1.5875);
#876=CARTESIAN_POINT('',(4.44499999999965,50.7999999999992,120.65));
#877=VERTEX_POINT('',#876);
#878=EDGE_CURVE('E459',#877,#877,#875,.T.);
#879=ORIENTED_EDGE('',*,*,#878,.F.);
#880=EDGE_LOOP('',(#879));
#881=FACE_BOUND('',#880,.T.);
#882=CARTESIAN_POINT('',(6.03249999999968,50.7999999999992,127.));
#883=DIRECTION('',(0.,1.,0.));
#884=DIRECTION('',(-1.,0.,0.));
#885=AXIS2_PLACEMENT_3D('',#882,#883,#884);
#886=CIRCLE('',#885,1.5875);
#887=CARTESIAN_POINT('',(4.44499999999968,50.7999999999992,127.));
#888=VERTEX_POINT('',#887);
#889=EDGE_CURVE('E463',#888,#888,#886,.T.);
#890=ORIENTED_EDGE('',*,*,#889,.F.);
#891=EDGE_LOOP('',(#890));
#892=FACE_BOUND('',#891,.T.);
#893=CARTESIAN_POINT('',(6.0324999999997,50.7999999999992,133.35));
#894=DIRECTION('',(0.,1.,0.));
#895=DIRECTION('',(-1.,0.,0.));
#896=AXIS2_PLACEMENT_3D('',#893,#894,#895);
#897=CIRCLE('',#896,1.5875);
#898=CARTESIAN_POINT('',(4.4449999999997,50.7999999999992,133.35));
#899=VERTEX_POINT('',#898);
#900=EDGE_CURVE('E467',#899,#899,#897,.T.);
#901=ORIENTED_EDGE('',*,*,#900,.F.);
#902=EDGE_LOOP('',(#901));
#903=FACE_BOUND('',#902,.T.);
#904=CARTESIAN_POINT('',(6.03249999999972,50.7999999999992,139.7));
#905=DIRECTION('',(0.,1.,0.));
#906=DIRECTION('',(-1.,0.,0.));
#907=AXIS2_PLACEMENT_3D('',#904,#905,#906);
#908=CIRCLE('',#907,1.5875);
#909=CARTESIAN_POINT('',(4.44499999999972,50.7999999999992,139.7));
#910=VERTEX_POINT('',#909);
#911=EDGE_CURVE('E471',#910,#910,#908,.T.);
#912=ORIENTED_EDGE('',*,*,#911,.F.);
#913=EDGE_LOOP('',(#912));
#914=FACE_BOUND('',#913,.T.);
#915=CARTESIAN_POINT('',(6.03249999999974,50.7999999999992,146.05));
#916=DIRECTION('',(0.,1.,0.));
#917=DIRECTION('',(-1.,0.,0.));
#918=AXIS2_PLACEMENT_3D('',#915,#916,#917);
#919=CIRCLE('',#918,1.5875);
#920=CARTESIAN_POINT('',(4.44499999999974,50.7999999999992,146.05));
#921=VERTEX_POINT('',#920);
#922=EDGE_CURVE('E475',#921,#921,#919,.T.);
#923=ORIENTED_EDGE('',*,*,#922,.F.);
#924=EDGE_LOOP('',(#923));
#925=FACE_BOUND('',#924,.T.);
#926=CARTESIAN_POINT('',(6.03249999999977,50.7999999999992,152.4));
#927=DIRECTION('',(0.,1.,0.));
#928=DIRECTION('',(-1.,0.,0.));
#929=AXIS2_PLACEMENT_3D('',#926,#927,#928);
#930=CIRCLE('',#929,1.5875);
#931=CARTESIAN_POINT('',(4.44499999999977,50.7999999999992,152.4));
#932=VERTEX_POINT('',#931);
#933=EDGE_CURVE('E479',#932,#932,#930,.T.);
#934=ORIENTED_EDGE('',*,*,#933,.F.);
#935=EDGE_LOOP('',(#934));
#936=FACE_BOUND('',#935,.T.);
#937=CARTESIAN_POINT('',(6.03249999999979,50.7999999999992,158.75));
#938=DIRECTION('',(0.,1.,0.));
#939=DIRECTION('',(-1.,0.,0.));
#940=AXIS2_PLACEMENT_3D('',#937,#938,#939);
#941=CIRCLE('',#940,1.5875);
#942=CARTESIAN_POINT('',(4.44499999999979,50.7999999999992,158.75));
#943=VERTEX_POINT('',#942);
#944=EDGE_CURVE('E483',#943,#943,#941,.T.);
#945=ORIENTED_EDGE('',*,*,#944,.F.);
#946=EDGE_LOOP('',(#945));
#947=FACE_BOUND('',#946,.T.);
#948=CARTESIAN_POINT('',(6.03249999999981,50.7999999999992,165.1));
#949=DIRECTION('',(0.,1.,0.));
#950=DIRECTION('',(-1.,0.,0.));
#951=AXIS2_PLACEMENT_3D('',#948,#949,#950);
#952=CIRCLE('',#951,1.5875);
#953=CARTESIAN_POINT('',(4.44499999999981,50.7999999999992,165.1));
#954=VERTEX_POINT('',#953);
#955=EDGE_CURVE('E487',#954,#954,#952,.T.);
#956=ORIENTED_EDGE('',*,*,#955,.F.);
#957=EDGE_LOOP('',(#956));
#958=FACE_BOUND('',#957,.T.);
#959=CARTESIAN_POINT('',(6.03249999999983,50.7999999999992,171.45));
#960=DIRECTION('',(0.,1.,0.));
#961=DIRECTION('',(-1.,0.,0.));
#962=AXIS2_PLACEMENT_3D('',#959,#960,#961);
#963=CIRCLE('',#962,1.5875);
#964=CARTESIAN_POINT('',(4.44499999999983,50.7999999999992,171.45));
#965=VERTEX_POINT('',#964);
#966=EDGE_CURVE('E491',#965,#965,#963,.T.);
#967=ORIENTED_EDGE('',*,*,#966,.F.);
#968=EDGE_LOOP('',(#967));
#969=FACE_BOUND('',#968,.T.);
#970=CARTESIAN_POINT('',(6.03249999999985,50.7999999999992,177.8));
#971=DIRECTION('',(0.,1.,0.));
#972=DIRECTION('',(-1.,0.,0.));
#973=AXIS2_PLACEMENT_3D('',#970,#971,#972);
#974=CIRCLE('',#973,1.5875);
#975=CARTESIAN_POINT('',(4.44499999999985,50.7999999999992,177.8));
#976=VERTEX_POINT('',#975);
#977=EDGE_CURVE('E495',#976,#976,#974,.T.);
#978=ORIENTED_EDGE('',*,*,#977,.F.);
#979=EDGE_LOOP('',(#978));
#980=FACE_BOUND('',#979,.T.);
#981=CARTESIAN_POINT('',(6.03249999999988,50.7999999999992,184.15));
#982=DIRECTION('',(0.,1.,0.));
#983=DIRECTION('',(-1.,0.,0.));
#984=AXIS2_PLACEMENT_3D('',#981,#982,#983);
#985=CIRCLE('',#984,1.5875);
#986=CARTESIAN_POINT('',(4.44499999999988,50.7999999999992,184.15));
#987=VERTEX_POINT('',#986);
#988=EDGE_CURVE('E499',#987,#987,#985,.T.);
#989=ORIENTED_EDGE('',*,*,#988,.F.);
#990=EDGE_LOOP('',(#989));
#991=FACE_BOUND('',#990,.T.);
#992=CARTESIAN_POINT('',(6.0324999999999,50.7999999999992,190.5));
#993=DIRECTION('',(0.,1.,0.));
#994=DIRECTION('',(-1.,0.,0.));
#995=AXIS2_PLACEMENT_3D('',#992,#993,#994);
#996=CIRCLE('',#995,1.5875);
#997=CARTESIAN_POINT('',(4.4449999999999,50.7999999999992,190.5));
#998=VERTEX_POINT('',#997);
#999=EDGE_CURVE('E503',#998,#998,#996,.T.);
#1000=ORIENTED_EDGE('',*,*,#999,.F.);
#1001=EDGE_LOOP('',(#1000));
#1002=FACE_BOUND('',#1001,.T.);
#1003=CARTESIAN_POINT('',(6.03249999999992,50.7999999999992,196.85));
#1004=DIRECTION('',(0.,1.,0.));
#1005=DIRECTION('',(-1.,0.,0.));
#1006=AXIS2_PLACEMENT_3D('',#1003,#1004,#1005);
#1007=CIRCLE('',#1006,1.5875);
#1008=CARTESIAN_POINT('',(4.44499999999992,50.7999999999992,196.85));
#1009=VERTEX_POINT('',#1008);
#1010=EDGE_CURVE('E507',#1009,#1009,#1007,.T.);
#1011=ORIENTED_EDGE('',*,*,#1010,.F.);
#1012=EDGE_LOOP('',(#1011));
#1013=FACE_BOUND('',#1012,.T.);
#1014=CARTESIAN_POINT('',(6.03249999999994,50.7999999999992,203.2));
#1015=DIRECTION('',(0.,1.,0.));
#1016=DIRECTION('',(-1.,0.,0.));
#1017=AXIS2_PLACEMENT_3D('',#1014,#1015,#1016);
#1018=CIRCLE('',#1017,1.5875);
#1019=CARTESIAN_POINT('',(4.44499999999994,50.7999999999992,203.2));
#1020=VERTEX_POINT('',#1019);
#1021=EDGE_CURVE('E511',#1020,#1020,#1018,.T.);
#1022=ORIENTED_EDGE('',*,*,#1021,.F.);
#1023=EDGE_LOOP('',(#1022));
#1024=FACE_BOUND('',#1023,.T.);
#1025=CARTESIAN_POINT('',(6.03249999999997,50.7999999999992,209.55));
#1026=DIRECTION('',(0.,1.,0.));
#1027=DIRECTION('',(-1.,0.,0.));
#1028=AXIS2_PLACEMENT_3D('',#1025,#1026,#1027);
#1029=CIRCLE('',#1028,1.5875);
#1030=CARTESIAN_POINT('',(4.44499999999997,50.7999999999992,209.55));
#1031=VERTEX_POINT('',#1030);
#1032=EDGE_CURVE('E515',#1031,#1031,#1029,.T.);
#1033=ORIENTED_EDGE('',*,*,#1032,.F.);
#1034=EDGE_LOOP('',(#1033));
#1035=FACE_BOUND('',#1034,.T.);
#1036=CARTESIAN_POINT('',(6.03249999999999,50.7999999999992,215.9));
#1037=DIRECTION('',(0.,1.,0.));
#1038=DIRECTION('',(-1.,0.,0.));
#1039=AXIS2_PLACEMENT_3D('',#1036,#1037,#1038);
#1040=CIRCLE('',#1039,1.5875);
#1041=CARTESIAN_POINT('',(4.44499999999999,50.7999999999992,215.9));
#1042=VERTEX_POINT('',#1041);
#1043=EDGE_CURVE('E519',#1042,#1042,#1040,.T.);
#1044=ORIENTED_EDGE('',*,*,#1043,.F.);
#1045=EDGE_LOOP('',(#1044));
#1046=FACE_BOUND('',#1045,.T.);
#1047=CARTESIAN_POINT('',(31.4324999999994,50.7999999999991,38.1));
#1048=DIRECTION('',(0.,1.,0.));
#1049=DIRECTION('',(-1.,0.,0.));
#1050=AXIS2_PLACEMENT_3D('',#1047,#1048,#1049);
#1051=CIRCLE('',#1050,1.5875);
#1052=CARTESIAN_POINT('',(29.8449999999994,50.7999999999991,38.1));
#1053=VERTEX_POINT('',#1052);
#1054=EDGE_CURVE('E523',#1053,#1053,#1051,.T.);
#1055=ORIENTED_EDGE('',*,*,#1054,.F.);
#1056=EDGE_LOOP('',(#1055));
#1057=FACE_BOUND('',#1056,.T.);
#1058=CARTESIAN_POINT('',(25.0824999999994,50.7999999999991,38.1));
#1059=DIRECTION('',(0.,1.,0.));
#1060=DIRECTION('',(-1.,0.,0.));
#1061=AXIS2_PLACEMENT_3D('',#1058,#1059,#1060);
#1062=CIRCLE('',#1061,1.5875);
#1063=CARTESIAN_POINT('',(23.4949999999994,50.7999999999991,38.1));
#1064=VERTEX_POINT('',#1063);
#1065=EDGE_CURVE('E527',#1064,#1064,#1062,.T.);
#1066=ORIENTED_EDGE('',*,*,#1065,.F.);
#1067=EDGE_LOOP('',(#1066));
#1068=FACE_BOUND('',#1067,.T.);
#1069=CARTESIAN_POINT('',(31.4324999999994,50.7999999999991,44.45));
#1070=DIRECTION('',(0.,1.,0.));
#1071=DIRECTION('',(-1.,0.,0.));
#1072=AXIS2_PLACEMENT_3D('',#1069,#1070,#1071);
#1073=CIRCLE('',#1072,1.5875);
#1074=CARTESIAN_POINT('',(29.8449999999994,50.7999999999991,44.45));
#1075=VERTEX_POINT('',#1074);
#1076=EDGE_CURVE('E531',#1075,#1075,#1073,.T.);
#1077=ORIENTED_EDGE('',*,*,#1076,.F.);
#1078=EDGE_LOOP('',(#1077));
#1079=FACE_BOUND('',#1078,.T.);
#1080=CARTESIAN_POINT('',(25.0824999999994,50.7999999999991,44.45));
#1081=DIRECTION('',(0.,1.,0.));
#1082=DIRECTION('',(-1.,0.,0.));
#1083=AXIS2_PLACEMENT_3D('',#1080,#1081,#1082);
#1084=CIRCLE('',#1083,1.5875);
#1085=CARTESIAN_POINT('',(23.4949999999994,50.7999999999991,44.45));
#1086=VERTEX_POINT('',#1085);
#1087=EDGE_CURVE('E535',#1086,#1086,#1084,.T.);
#1088=ORIENTED_EDGE('',*,*,#1087,.F.);
#1089=EDGE_LOOP('',(#1088));
#1090=FACE_BOUND('',#1089,.T.);
#1091=CARTESIAN_POINT('',(31.4324999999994,50.7999999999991,50.8));
#1092=DIRECTION('',(0.,1.,0.));
#1093=DIRECTION('',(-1.,0.,0.));
#1094=AXIS2_PLACEMENT_3D('',#1091,#1092,#1093);
#1095=CIRCLE('',#1094,1.5875);
#1096=CARTESIAN_POINT('',(29.8449999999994,50.7999999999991,50.8));
#1097=VERTEX_POINT('',#1096);
#1098=EDGE_CURVE('E539',#1097,#1097,#1095,.T.);
#1099=ORIENTED_EDGE('',*,*,#1098,.F.);
#1100=EDGE_LOOP('',(#1099));
#1101=FACE_BOUND('',#1100,.T.);
#1102=CARTESIAN_POINT('',(25.0824999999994,50.7999999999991,50.8));
#1103=DIRECTION('',(0.,1.,0.));
#1104=DIRECTION('',(-1.,0.,0.));
#1105=AXIS2_PLACEMENT_3D('',#1102,#1103,#1104);
#1106=CIRCLE('',#1105,1.5875);
#1107=CARTESIAN_POINT('',(23.4949999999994,50.7999999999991,50.8));
#1108=VERTEX_POINT('',#1107);
#1109=EDGE_CURVE('E543',#1108,#1108,#1106,.T.);
#1110=ORIENTED_EDGE('',*,*,#1109,.F.);
#1111=EDGE_LOOP('',(#1110));
#1112=FACE_BOUND('',#1111,.T.);
#1113=CARTESIAN_POINT('',(31.4324999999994,50.7999999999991,57.15));
#1114=DIRECTION('',(0.,1.,0.));
#1115=DIRECTION('',(-1.,0.,0.));
#1116=AXIS2_PLACEMENT_3D('',#1113,#1114,#1115);
#1117=CIRCLE('',#1116,1.58750000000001);
#1118=CARTESIAN_POINT('',(29.8449999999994,50.7999999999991,57.15));
#1119=VERTEX_POINT('',#1118);
#1120=EDGE_CURVE('E547',#1119,#1119,#1117,.T.);
#1121=ORIENTED_EDGE('',*,*,#1120,.F.);
#1122=EDGE_LOOP('',(#1121));
#1123=FACE_BOUND('',#1122,.T.);
#1124=CARTESIAN_POINT('',(25.0824999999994,50.7999999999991,57.15));
#1125=DIRECTION('',(0.,1.,0.));
#1126=DIRECTION('',(-1.,0.,0.));
#1127=AXIS2_PLACEMENT_3D('',#1124,#1125,#1126);
#1128=CIRCLE('',#1127,1.5875);
#1129=CARTESIAN_POINT('',(23.4949999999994,50.7999999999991,57.15));
#1130=VERTEX_POINT('',#1129);
#1131=EDGE_CURVE('E551',#1130,#1130,#1128,.T.);
#1132=ORIENTED_EDGE('',*,*,#1131,.F.);
#1133=EDGE_LOOP('',(#1132));
#1134=FACE_BOUND('',#1133,.T.);
#1135=CARTESIAN_POINT('',(31.4324999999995,50.7999999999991,63.5));
#1136=DIRECTION('',(0.,1.,0.));
#1137=DIRECTION('',(-1.,0.,0.));
#1138=AXIS2_PLACEMENT_3D('',#1135,#1136,#1137);
#1139=CIRCLE('',#1138,1.5875);
#1140=CARTESIAN_POINT('',(29.8449999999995,50.7999999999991,63.5));
#1141=VERTEX_POINT('',#1140);
#1142=EDGE_CURVE('E555',#1141,#1141,#1139,.T.);
#1143=ORIENTED_EDGE('',*,*,#1142,.F.);
#1144=EDGE_LOOP('',(#1143));
#1145=FACE_BOUND('',#1144,.T.);
#1146=CARTESIAN_POINT('',(25.0824999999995,50.7999999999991,63.5));
#1147=DIRECTION('',(0.,1.,0.));
#1148=DIRECTION('',(-1.,0.,0.));
#1149=AXIS2_PLACEMENT_3D('',#1146,#1147,#1148);
#1150=CIRCLE('',#1149,1.5875);
#1151=CARTESIAN_POINT('',(23.4949999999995,50.7999999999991,63.5));
#1152=VERTEX_POINT('',#1151);
#1153=EDGE_CURVE('E559',#1152,#1152,#1150,.T.);
#1154=ORIENTED_EDGE('',*,*,#1153,.F.);
#1155=EDGE_LOOP('',(#1154));
#1156=FACE_BOUND('',#1155,.T.);
#1157=CARTESIAN_POINT('',(31.4324999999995,50.7999999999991,69.85));
#1158=DIRECTION('',(0.,1.,0.));
#1159=DIRECTION('',(-1.,0.,0.));
#1160=AXIS2_PLACEMENT_3D('',#1157,#1158,#1159);
#1161=CIRCLE('',#1160,1.5875);
#1162=CARTESIAN_POINT('',(29.8449999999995,50.7999999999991,69.85));
#1163=VERTEX_POINT('',#1162);
#1164=EDGE_CURVE('E563',#1163,#1163,#1161,.T.);
#1165=ORIENTED_EDGE('',*,*,#1164,.F.);
#1166=EDGE_LOOP('',(#1165));
#1167=FACE_BOUND('',#1166,.T.);
#1168=CARTESIAN_POINT('',(25.0824999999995,50.7999999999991,69.85));
#1169=DIRECTION('',(0.,1.,0.));
#1170=DIRECTION('',(-1.,0.,0.));
#1171=AXIS2_PLACEMENT_3D('',#1168,#1169,#1170);
#1172=CIRCLE('',#1171,1.5875);
#1173=CARTESIAN_POINT('',(23.4949999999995,50.7999999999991,69.85));
#1174=VERTEX_POINT('',#1173);
#1175=EDGE_CURVE('E567',#1174,#1174,#1172,.T.);
#1176=ORIENTED_EDGE('',*,*,#1175,.F.);
#1177=EDGE_LOOP('',(#1176));
#1178=FACE_BOUND('',#1177,.T.);
#1179=CARTESIAN_POINT('',(31.4324999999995,50.7999999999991,76.2));
#1180=DIRECTION('',(0.,1.,0.));
#1181=DIRECTION('',(-1.,0.,0.));
#1182=AXIS2_PLACEMENT_3D('',#1179,#1180,#1181);
#1183=CIRCLE('',#1182,1.5875);
#1184=CARTESIAN_POINT('',(29.8449999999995,50.7999999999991,76.2));
#1185=VERTEX_POINT('',#1184);
#1186=EDGE_CURVE('E571',#1185,#1185,#1183,.T.);
#1187=ORIENTED_EDGE('',*,*,#1186,.F.);
#1188=EDGE_LOOP('',(#1187));
#1189=FACE_BOUND('',#1188,.T.);
#1190=CARTESIAN_POINT('',(25.0824999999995,50.7999999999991,76.2));
#1191=DIRECTION('',(0.,1.,0.));
#1192=DIRECTION('',(-1.,0.,0.));
#1193=AXIS2_PLACEMENT_3D('',#1190,#1191,#1192);
#1194=CIRCLE('',#1193,1.5875);
#1195=CARTESIAN_POINT('',(23.4949999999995,50.7999999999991,76.2));
#1196=VERTEX_POINT('',#1195);
#1197=EDGE_CURVE('E575',#1196,#1196,#1194,.T.);
#1198=ORIENTED_EDGE('',*,*,#1197,.F.);
#1199=EDGE_LOOP('',(#1198));
#1200=FACE_BOUND('',#1199,.T.);
#1201=CARTESIAN_POINT('',(31.4324999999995,50.7999999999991,82.55));
#1202=DIRECTION('',(0.,1.,0.));
#1203=DIRECTION('',(-1.,0.,0.));
#1204=AXIS2_PLACEMENT_3D('',#1201,#1202,#1203);
#1205=CIRCLE('',#1204,1.5875);
#1206=CARTESIAN_POINT('',(29.8449999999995,50.7999999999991,82.55));
#1207=VERTEX_POINT('',#1206);
#1208=EDGE_CURVE('E579',#1207,#1207,#1205,.T.);
#1209=ORIENTED_EDGE('',*,*,#1208,.F.);
#1210=EDGE_LOOP('',(#1209));
#1211=FACE_BOUND('',#1210,.T.);
#1212=CARTESIAN_POINT('',(25.0824999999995,50.7999999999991,82.55));
#1213=DIRECTION('',(0.,1.,0.));
#1214=DIRECTION('',(-1.,0.,0.));
#1215=AXIS2_PLACEMENT_3D('',#1212,#1213,#1214);
#1216=CIRCLE('',#1215,1.5875);
#1217=CARTESIAN_POINT('',(23.4949999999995,50.7999999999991,82.55));
#1218=VERTEX_POINT('',#1217);
#1219=EDGE_CURVE('E583',#1218,#1218,#1216,.T.);
#1220=ORIENTED_EDGE('',*,*,#1219,.F.);
#1221=EDGE_LOOP('',(#1220));
#1222=FACE_BOUND('',#1221,.T.);
#1223=CARTESIAN_POINT('',(6.03250000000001,50.7999999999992,222.25));
#1224=DIRECTION('',(0.,1.,0.));
#1225=DIRECTION('',(-1.,0.,0.));
#1226=AXIS2_PLACEMENT_3D('',#1223,#1224,#1225);
#1227=CIRCLE('',#1226,1.5875);
#1228=CARTESIAN_POINT('',(4.44500000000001,50.7999999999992,222.25));
#1229=VERTEX_POINT('',#1228);
#1230=EDGE_CURVE('E587',#1229,#1229,#1227,.T.);
#1231=ORIENTED_EDGE('',*,*,#1230,.F.);
#1232=EDGE_LOOP('',(#1231));
#1233=FACE_BOUND('',#1232,.T.);
#1234=DIRECTION('',(-1.,0.,0.));
#1235=VECTOR('',#1234,1.);
#1236=CARTESIAN_POINT('',(18.7325,50.7999999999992,5.08));
#1237=LINE('',#1236,#1235);
#1238=CARTESIAN_POINT('',(18.7325,50.7999999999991,5.08));
#1239=VERTEX_POINT('',#1238);
#1240=CARTESIAN_POINT('',(12.1285,50.7999999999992,5.08));
#1241=VERTEX_POINT('',#1240);
#1242=EDGE_CURVE('E591',#1239,#1241,#1237,.T.);
#1243=ORIENTED_EDGE('',*,*,#1242,.F.);
#1244=DIRECTION('',(0.,0.,-1.));
#1245=VECTOR('',#1244,1.);
#1246=CARTESIAN_POINT('',(18.7325,50.7999999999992,5.08));
#1247=LINE('',#1246,#1245);
#1248=CARTESIAN_POINT('',(18.7325,50.7999999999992,157.48));
#1249=VERTEX_POINT('',#1248);
#1250=EDGE_CURVE('E60',#1249,#1239,#1247,.T.);
#1251=ORIENTED_EDGE('',*,*,#1250,.F.);
#1252=DIRECTION('',(1.,0.,0.));
#1253=VECTOR('',#1252,1.);
#1254=CARTESIAN_POINT('',(18.7325,50.7999999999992,157.48));
#1255=LINE('',#1254,#1253);
#1256=CARTESIAN_POINT('',(12.1285,50.7999999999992,157.48));
#1257=VERTEX_POINT('',#1256);
#1258=EDGE_CURVE('E598',#1257,#1249,#1255,.T.);
#1259=ORIENTED_EDGE('',*,*,#1258,.F.);
#1260=DIRECTION('',(0.,0.,1.));
#1261=VECTOR('',#1260,1.);
#1262=CARTESIAN_POINT('',(12.1285,50.7999999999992,5.08));
#1263=LINE('',#1262,#1261);
#1264=EDGE_CURVE('E594',#1241,#1257,#1263,.T.);
#1265=ORIENTED_EDGE('',*,*,#1264,.F.);
#1266=EDGE_LOOP('',(#1243,#1251,#1259,#1265));
#1267=FACE_BOUND('',#1266,.T.);
#1268=DIRECTION('',(-1.,0.,0.));
#1269=VECTOR('',#1268,1.);
#1270=CARTESIAN_POINT('',(-1.58749999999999,50.7999999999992,0.));
#1271=LINE('',#1270,#1269);
#1272=CARTESIAN_POINT('',(36.5125,50.7999999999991,0.));
#1273=VERTEX_POINT('',#1272);
#1274=CARTESIAN_POINT('',(-1.58749999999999,50.7999999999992,0.));
#1275=VERTEX_POINT('',#1274);
#1276=EDGE_CURVE('E130',#1273,#1275,#1271,.T.);
#1277=ORIENTED_EDGE('',*,*,#1276,.T.);
#1278=DIRECTION('',(0.,0.,-1.));
#1279=VECTOR('',#1278,1.);
#1280=CARTESIAN_POINT('',(-1.58749999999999,50.7999999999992,228.6));
#1281=LINE('',#1280,#1279);
#1282=CARTESIAN_POINT('',(-1.58749999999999,50.7999999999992,228.6));
#1283=VERTEX_POINT('',#1282);
#1284=EDGE_CURVE('E11',#1283,#1275,#1281,.T.);
#1285=ORIENTED_EDGE('',*,*,#1284,.F.);
#1286=DIRECTION('',(-1.,0.,0.));
#1287=VECTOR('',#1286,1.);
#1288=CARTESIAN_POINT('',(-1.58749999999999,50.7999999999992,228.6));
#1289=LINE('',#1288,#1287);
#1290=CARTESIAN_POINT('',(36.5125,50.7999999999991,228.6));
#1291=VERTEX_POINT('',#1290);
#1292=EDGE_CURVE('E121',#1291,#1283,#1289,.T.);
#1293=ORIENTED_EDGE('',*,*,#1292,.F.);
#1294=DIRECTION('',(0.,0.,-1.));
#1295=VECTOR('',#1294,1.);
#1296=CARTESIAN_POINT('',(36.5125,50.7999999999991,228.6));
#1297=LINE('',#1296,#1295);
#1298=EDGE_CURVE('E129',#1291,#1273,#1297,.T.);
#1299=ORIENTED_EDGE('',*,*,#1298,.T.);
#1300=EDGE_LOOP('',(#1277,#1285,#1293,#1299));
#1301=FACE_BOUND('',#1300,.T.);
#1302=ADVANCED_FACE('F38',(#34,#45,#56,#67,#78,#89,#100,#111,#122,#133,#144,#155,#166,#177,#188,
#199,#210,#221,#232,#243,#254,#265,#276,#287,#298,#309,#320,#331,#342,#353,#364,#375,#386,#397,
#408,#419,#430,#441,#452,#463,#474,#485,#496,#507,#518,#529,#540,#551,#562,#573,#584,#595,#606,
#617,#628,#639,#650,#661,#672,#683,#694,#705,#716,#727,#738,#749,#760,#771,#782,#793,#804,#815,
#826,#837,#848,#859,#870,#881,#892,#903,#914,#925,#936,#947,#958,#969,#980,#991,#1002,#1013,
#1024,#1035,#1046,#1057,#1068,#1079,#1090,#1101,#1112,#1123,#1134,#1145,#1156,#1167,#1178,#1189,
#1200,#1211,#1222,#1233,#1267,#1301),#23,.F.);
#1303=CARTESIAN_POINT('',(-1.58750000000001,-50.8000000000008,228.6));
#1304=DIRECTION('',(1.,0.,0.));
#1305=DIRECTION('',(0.,1.,0.));
#1306=AXIS2_PLACEMENT_3D('',#1303,#1304,#1305);
#1307=PLANE('',#1306);
#1308=DIRECTION('',(0.,-1.,0.));
#1309=VECTOR('',#1308,1.);
#1310=CARTESIAN_POINT('',(-1.58750000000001,-50.8000000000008,0.));
#1311=LINE('',#1310,#1309);
#1312=CARTESIAN_POINT('',(-1.58749999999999,47.6249999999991,0.));
#1313=VERTEX_POINT('',#1312);
#1314=EDGE_CURVE('E116',#1275,#1313,#1311,.T.);
#1315=ORIENTED_EDGE('',*,*,#1314,.T.);
#1316=DIRECTION('',(0.,0.,-1.));
#1317=VECTOR('',#1316,1.);
#1318=CARTESIAN_POINT('',(-1.58749999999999,47.6249999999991,228.6));
#1319=LINE('',#1318,#1317);
#1320=CARTESIAN_POINT('',(-1.58749999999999,47.6249999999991,228.6));
#1321=VERTEX_POINT('',#1320);
#1322=EDGE_CURVE('E104',#1321,#1313,#1319,.T.);
#1323=ORIENTED_EDGE('',*,*,#1322,.F.);
#1324=DIRECTION('',(0.,-1.,0.));
#1325=VECTOR('',#1324,1.);
#1326=CARTESIAN_POINT('',(-1.58750000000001,-50.8000000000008,228.6));
#1327=LINE('',#1326,#1325);
#1328=EDGE_CURVE('E111',#1283,#1321,#1327,.T.);
#1329=ORIENTED_EDGE('',*,*,#1328,.F.);
#1330=ORIENTED_EDGE('',*,*,#1284,.T.);
#1331=EDGE_LOOP('',(#1315,#1323,#1329,#1330));
#1332=FACE_BOUND('',#1331,.T.);
#1333=ADVANCED_FACE('F114',(#1332),#1307,.F.);
#1334=CARTESIAN_POINT('',(1.5875,47.6249999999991,228.6));
#1335=DIRECTION('',(0.,1.,0.));
#1336=DIRECTION('',(0.,0.,1.));
#1337=AXIS2_PLACEMENT_3D('',#1334,#1335,#1336);
#1338=PLANE('',#1337);
#1339=CARTESIAN_POINT('',(12.3825,47.6249999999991,222.25));
#1340=DIRECTION('',(0.,1.,0.));
#1341=DIRECTION('',(0.,0.,1.));
#1342=AXIS2_PLACEMENT_3D('',#1339,#1340,#1341);
#1343=CIRCLE('',#1342,1.5875);
#1344=CARTESIAN_POINT('',(12.3825,47.6249999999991,223.8375));
#1345=VERTEX_POINT('',#1344);
#1346=EDGE_CURVE('E631',#1345,#1345,#1343,.F.);
#1347=ORIENTED_EDGE('',*,*,#1346,.F.);
#1348=EDGE_LOOP('',(#1347));
#1349=FACE_BOUND('',#1348,.T.);
#1350=CARTESIAN_POINT('',(18.7325,47.6249999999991,222.25));
#1351=DIRECTION('',(0.,1.,0.));
#1352=DIRECTION('',(0.,0.,1.));
#1353=AXIS2_PLACEMENT_3D('',#1350,#1351,#1352);
#1354=CIRCLE('',#1353,1.5875);
#1355=CARTESIAN_POINT('',(18.7325,47.6249999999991,223.8375));
#1356=VERTEX_POINT('',#1355);
#1357=EDGE_CURVE('E881',#1356,#1356,#1354,.F.);
#1358=ORIENTED_EDGE('',*,*,#1357,.F.);
#1359=EDGE_LOOP('',(#1358));
#1360=FACE_BOUND('',#1359,.T.);
#1361=CARTESIAN_POINT('',(25.0825,47.6249999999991,222.25));
#1362=DIRECTION('',(0.,1.,0.));
#1363=DIRECTION('',(0.,0.,1.));
#1364=AXIS2_PLACEMENT_3D('',#1361,#1362,#1363);
#1365=CIRCLE('',#1364,1.5875);
#1366=CARTESIAN_POINT('',(25.0825,47.6249999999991,223.8375));
#1367=VERTEX_POINT('',#1366);
#1368=EDGE_CURVE('E877',#1367,#1367,#1365,.F.);
#1369=ORIENTED_EDGE('',*,*,#1368,.F.);
#1370=EDGE_LOOP('',(#1369));
#1371=FACE_BOUND('',#1370,.T.);
#1372=CARTESIAN_POINT('',(31.4325,47.6249999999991,222.25));
#1373=DIRECTION('',(0.,1.,0.));
#1374=DIRECTION('',(0.,0.,1.));
#1375=AXIS2_PLACEMENT_3D('',#1372,#1373,#1374);
#1376=CIRCLE('',#1375,1.5875);
#1377=CARTESIAN_POINT('',(31.4325,47.6249999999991,223.8375));
#1378=VERTEX_POINT('',#1377);
#1379=EDGE_CURVE('E873',#1378,#1378,#1376,.F.);
#1380=ORIENTED_EDGE('',*,*,#1379,.F.);
#1381=EDGE_LOOP('',(#1380));
#1382=FACE_BOUND('',#1381,.T.);
#1383=CARTESIAN_POINT('',(12.3825,47.6249999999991,215.9));
#1384=DIRECTION('',(0.,1.,0.));
#1385=DIRECTION('',(0.,0.,1.));
#1386=AXIS2_PLACEMENT_3D('',#1383,#1384,#1385);
#1387=CIRCLE('',#1386,1.5875);
#1388=CARTESIAN_POINT('',(12.3825,47.6249999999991,217.4875));
#1389=VERTEX_POINT('',#1388);
#1390=EDGE_CURVE('E869',#1389,#1389,#1387,.F.);
#1391=ORIENTED_EDGE('',*,*,#1390,.F.);
#1392=EDGE_LOOP('',(#1391));
#1393=FACE_BOUND('',#1392,.T.);
#1394=CARTESIAN_POINT('',(18.7325,47.6249999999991,215.9));
#1395=DIRECTION('',(0.,1.,0.));
#1396=DIRECTION('',(0.,0.,1.));
#1397=AXIS2_PLACEMENT_3D('',#1394,#1395,#1396);
#1398=CIRCLE('',#1397,1.5875);
#1399=CARTESIAN_POINT('',(18.7325,47.6249999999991,217.4875));
#1400=VERTEX_POINT('',#1399);
#1401=EDGE_CURVE('E865',#1400,#1400,#1398,.F.);
#1402=ORIENTED_EDGE('',*,*,#1401,.F.);
#1403=EDGE_LOOP('',(#1402));
#1404=FACE_BOUND('',#1403,.T.);
#1405=CARTESIAN_POINT('',(25.0825,47.6249999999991,215.9));
#1406=DIRECTION('',(0.,1.,0.));
#1407=DIRECTION('',(0.,0.,1.));
#1408=AXIS2_PLACEMENT_3D('',#1405,#1406,#1407);
#1409=CIRCLE('',#1408,1.5875);
#1410=CARTESIAN_POINT('',(25.0825,47.6249999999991,217.4875));
#1411=VERTEX_POINT('',#1410);
#1412=EDGE_CURVE('E861',#1411,#1411,#1409,.F.);
#1413=ORIENTED_EDGE('',*,*,#1412,.F.);
#1414=EDGE_LOOP('',(#1413));
#1415=FACE_BOUND('',#1414,.T.);
#1416=CARTESIAN_POINT('',(31.4325,47.6249999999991,215.9));
#1417=DIRECTION('',(0.,1.,0.));
#1418=DIRECTION('',(0.,0.,1.));
#1419=AXIS2_PLACEMENT_3D('',#1416,#1417,#1418);
#1420=CIRCLE('',#1419,1.58750000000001);
#1421=CARTESIAN_POINT('',(31.4325,47.6249999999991,217.4875));
#1422=VERTEX_POINT('',#1421);
#1423=EDGE_CURVE('E857',#1422,#1422,#1420,.F.);
#1424=ORIENTED_EDGE('',*,*,#1423,.F.);
#1425=EDGE_LOOP('',(#1424));
#1426=FACE_BOUND('',#1425,.T.);
#1427=CARTESIAN_POINT('',(12.3825,47.6249999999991,209.55));
#1428=DIRECTION('',(0.,1.,0.));
#1429=DIRECTION('',(0.,0.,1.));
#1430=AXIS2_PLACEMENT_3D('',#1427,#1428,#1429);
#1431=CIRCLE('',#1430,1.5875);
#1432=CARTESIAN_POINT('',(12.3825,47.6249999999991,211.1375));
#1433=VERTEX_POINT('',#1432);
#1434=EDGE_CURVE('E853',#1433,#1433,#1431,.F.);
#1435=ORIENTED_EDGE('',*,*,#1434,.F.);
#1436=EDGE_LOOP('',(#1435));
#1437=FACE_BOUND('',#1436,.T.);
#1438=CARTESIAN_POINT('',(18.7325,47.6249999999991,209.55));
#1439=DIRECTION('',(0.,1.,0.));
#1440=DIRECTION('',(0.,0.,1.));
#1441=AXIS2_PLACEMENT_3D('',#1438,#1439,#1440);
#1442=CIRCLE('',#1441,1.5875);
#1443=CARTESIAN_POINT('',(18.7325,47.6249999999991,211.1375));
#1444=VERTEX_POINT('',#1443);
#1445=EDGE_CURVE('E849',#1444,#1444,#1442,.F.);
#1446=ORIENTED_EDGE('',*,*,#1445,.F.);
#1447=EDGE_LOOP('',(#1446));
#1448=FACE_BOUND('',#1447,.T.);
#1449=CARTESIAN_POINT('',(25.0825,47.6249999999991,209.55));
#1450=DIRECTION('',(0.,1.,0.));
#1451=DIRECTION('',(0.,0.,1.));
#1452=AXIS2_PLACEMENT_3D('',#1449,#1450,#1451);
#1453=CIRCLE('',#1452,1.5875);
#1454=CARTESIAN_POINT('',(25.0825,47.6249999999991,211.1375));
#1455=VERTEX_POINT('',#1454);
#1456=EDGE_CURVE('E845',#1455,#1455,#1453,.F.);
#1457=ORIENTED_EDGE('',*,*,#1456,.F.);
#1458=EDGE_LOOP('',(#1457));
#1459=FACE_BOUND('',#1458,.T.);
#1460=CARTESIAN_POINT('',(31.4325,47.6249999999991,209.55));
#1461=DIRECTION('',(0.,1.,0.));
#1462=DIRECTION('',(0.,0.,1.));
#1463=AXIS2_PLACEMENT_3D('',#1460,#1461,#1462);
#1464=CIRCLE('',#1463,1.5875);
#1465=CARTESIAN_POINT('',(31.4325,47.6249999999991,211.1375));
#1466=VERTEX_POINT('',#1465);
#1467=EDGE_CURVE('E841',#1466,#1466,#1464,.F.);
#1468=ORIENTED_EDGE('',*,*,#1467,.F.);
#1469=EDGE_LOOP('',(#1468));
#1470=FACE_BOUND('',#1469,.T.);
#1471=CARTESIAN_POINT('',(12.3824999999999,47.6249999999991,203.2));
#1472=DIRECTION('',(0.,1.,0.));
#1473=DIRECTION('',(0.,0.,1.));
#1474=AXIS2_PLACEMENT_3D('',#1471,#1472,#1473);
#1475=CIRCLE('',#1474,1.5875);
#1476=CARTESIAN_POINT('',(12.3824999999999,47.6249999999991,204.7875));
#1477=VERTEX_POINT('',#1476);
#1478=EDGE_CURVE('E837',#1477,#1477,#1475,.F.);
#1479=ORIENTED_EDGE('',*,*,#1478,.F.);
#1480=EDGE_LOOP('',(#1479));
#1481=FACE_BOUND('',#1480,.T.);
#1482=CARTESIAN_POINT('',(18.7324999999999,47.6249999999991,203.2));
#1483=DIRECTION('',(0.,1.,0.));
#1484=DIRECTION('',(0.,0.,1.));
#1485=AXIS2_PLACEMENT_3D('',#1482,#1483,#1484);
#1486=CIRCLE('',#1485,1.5875);
#1487=CARTESIAN_POINT('',(18.7324999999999,47.6249999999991,204.7875));
#1488=VERTEX_POINT('',#1487);
#1489=EDGE_CURVE('E833',#1488,#1488,#1486,.F.);
#1490=ORIENTED_EDGE('',*,*,#1489,.F.);
#1491=EDGE_LOOP('',(#1490));
#1492=FACE_BOUND('',#1491,.T.);
#1493=CARTESIAN_POINT('',(25.0824999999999,47.6249999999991,203.2));
#1494=DIRECTION('',(0.,1.,0.));
#1495=DIRECTION('',(0.,0.,1.));
#1496=AXIS2_PLACEMENT_3D('',#1493,#1494,#1495);
#1497=CIRCLE('',#1496,1.5875);
#1498=CARTESIAN_POINT('',(25.0824999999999,47.6249999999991,204.7875));
#1499=VERTEX_POINT('',#1498);
#1500=EDGE_CURVE('E829',#1499,#1499,#1497,.F.);
#1501=ORIENTED_EDGE('',*,*,#1500,.F.);
#1502=EDGE_LOOP('',(#1501));
#1503=FACE_BOUND('',#1502,.T.);
#1504=CARTESIAN_POINT('',(31.4324999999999,47.6249999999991,203.2));
#1505=DIRECTION('',(0.,1.,0.));
#1506=DIRECTION('',(0.,0.,1.));
#1507=AXIS2_PLACEMENT_3D('',#1504,#1505,#1506);
#1508=CIRCLE('',#1507,1.5875);
#1509=CARTESIAN_POINT('',(31.4324999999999,47.6249999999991,204.7875));
#1510=VERTEX_POINT('',#1509);
#1511=EDGE_CURVE('E825',#1510,#1510,#1508,.F.);
#1512=ORIENTED_EDGE('',*,*,#1511,.F.);
#1513=EDGE_LOOP('',(#1512));
#1514=FACE_BOUND('',#1513,.T.);
#1515=CARTESIAN_POINT('',(12.3824999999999,47.6249999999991,196.85));
#1516=DIRECTION('',(0.,1.,0.));
#1517=DIRECTION('',(0.,0.,1.));
#1518=AXIS2_PLACEMENT_3D('',#1515,#1516,#1517);
#1519=CIRCLE('',#1518,1.5875);
#1520=CARTESIAN_POINT('',(12.3824999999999,47.6249999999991,198.4375));
#1521=VERTEX_POINT('',#1520);
#1522=EDGE_CURVE('E821',#1521,#1521,#1519,.F.);
#1523=ORIENTED_EDGE('',*,*,#1522,.F.);
#1524=EDGE_LOOP('',(#1523));
#1525=FACE_BOUND('',#1524,.T.);
#1526=CARTESIAN_POINT('',(18.7324999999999,47.6249999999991,196.85));
#1527=DIRECTION('',(0.,1.,0.));
#1528=DIRECTION('',(0.,0.,1.));
#1529=AXIS2_PLACEMENT_3D('',#1526,#1527,#1528);
#1530=CIRCLE('',#1529,1.5875);
#1531=CARTESIAN_POINT('',(18.7324999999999,47.6249999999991,198.4375));
#1532=VERTEX_POINT('',#1531);
#1533=EDGE_CURVE('E817',#1532,#1532,#1530,.F.);
#1534=ORIENTED_EDGE('',*,*,#1533,.F.);
#1535=EDGE_LOOP('',(#1534));
#1536=FACE_BOUND('',#1535,.T.);
#1537=CARTESIAN_POINT('',(25.0824999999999,47.6249999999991,196.85));
#1538=DIRECTION('',(0.,1.,0.));
#1539=DIRECTION('',(0.,0.,1.));
#1540=AXIS2_PLACEMENT_3D('',#1537,#1538,#1539);
#1541=CIRCLE('',#1540,1.5875);
#1542=CARTESIAN_POINT('',(25.0824999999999,47.6249999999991,198.4375));
#1543=VERTEX_POINT('',#1542);
#1544=EDGE_CURVE('E813',#1543,#1543,#1541,.F.);
#1545=ORIENTED_EDGE('',*,*,#1544,.F.);
#1546=EDGE_LOOP('',(#1545));
#1547=FACE_BOUND('',#1546,.T.);
#1548=CARTESIAN_POINT('',(31.4324999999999,47.6249999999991,196.85));
#1549=DIRECTION('',(0.,1.,0.));
#1550=DIRECTION('',(0.,0.,1.));
#1551=AXIS2_PLACEMENT_3D('',#1548,#1549,#1550);
#1552=CIRCLE('',#1551,1.58750000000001);
#1553=CARTESIAN_POINT('',(31.4324999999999,47.6249999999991,198.4375));
#1554=VERTEX_POINT('',#1553);
#1555=EDGE_CURVE('E809',#1554,#1554,#1552,.F.);
#1556=ORIENTED_EDGE('',*,*,#1555,.F.);
#1557=EDGE_LOOP('',(#1556));
#1558=FACE_BOUND('',#1557,.T.);
#1559=CARTESIAN_POINT('',(12.3824999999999,47.6249999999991,190.5));
#1560=DIRECTION('',(0.,1.,0.));
#1561=DIRECTION('',(0.,0.,1.));
#1562=AXIS2_PLACEMENT_3D('',#1559,#1560,#1561);
#1563=CIRCLE('',#1562,1.5875);
#1564=CARTESIAN_POINT('',(12.3824999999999,47.6249999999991,192.0875));
#1565=VERTEX_POINT('',#1564);
#1566=EDGE_CURVE('E805',#1565,#1565,#1563,.F.);
#1567=ORIENTED_EDGE('',*,*,#1566,.F.);
#1568=EDGE_LOOP('',(#1567));
#1569=FACE_BOUND('',#1568,.T.);
#1570=CARTESIAN_POINT('',(18.7324999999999,47.6249999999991,190.5));
#1571=DIRECTION('',(0.,1.,0.));
#1572=DIRECTION('',(0.,0.,1.));
#1573=AXIS2_PLACEMENT_3D('',#1570,#1571,#1572);
#1574=CIRCLE('',#1573,1.5875);
#1575=CARTESIAN_POINT('',(18.7324999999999,47.6249999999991,192.0875));
#1576=VERTEX_POINT('',#1575);
#1577=EDGE_CURVE('E801',#1576,#1576,#1574,.F.);
#1578=ORIENTED_EDGE('',*,*,#1577,.F.);
#1579=EDGE_LOOP('',(#1578));
#1580=FACE_BOUND('',#1579,.T.);
#1581=CARTESIAN_POINT('',(25.0824999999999,47.6249999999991,190.5));
#1582=DIRECTION('',(0.,1.,0.));
#1583=DIRECTION('',(0.,0.,1.));
#1584=AXIS2_PLACEMENT_3D('',#1581,#1582,#1583);
#1585=CIRCLE('',#1584,1.5875);
#1586=CARTESIAN_POINT('',(25.0824999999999,47.6249999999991,192.0875));
#1587=VERTEX_POINT('',#1586);
#1588=EDGE_CURVE('E797',#1587,#1587,#1585,.F.);
#1589=ORIENTED_EDGE('',*,*,#1588,.F.);
#1590=EDGE_LOOP('',(#1589));
#1591=FACE_BOUND('',#1590,.T.);
#1592=CARTESIAN_POINT('',(31.4324999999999,47.6249999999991,190.5));
#1593=DIRECTION('',(0.,1.,0.));
#1594=DIRECTION('',(0.,0.,1.));
#1595=AXIS2_PLACEMENT_3D('',#1592,#1593,#1594);
#1596=CIRCLE('',#1595,1.5875);
#1597=CARTESIAN_POINT('',(31.4324999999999,47.6249999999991,192.0875));
#1598=VERTEX_POINT('',#1597);
#1599=EDGE_CURVE('E793',#1598,#1598,#1596,.F.);
#1600=ORIENTED_EDGE('',*,*,#1599,.F.);
#1601=EDGE_LOOP('',(#1600));
#1602=FACE_BOUND('',#1601,.T.);
#1603=CARTESIAN_POINT('',(12.3824999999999,47.6249999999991,184.15));
#1604=DIRECTION('',(0.,1.,0.));
#1605=DIRECTION('',(0.,0.,1.));
#1606=AXIS2_PLACEMENT_3D('',#1603,#1604,#1605);
#1607=CIRCLE('',#1606,1.5875);
#1608=CARTESIAN_POINT('',(12.3824999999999,47.6249999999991,185.7375));
#1609=VERTEX_POINT('',#1608);
#1610=EDGE_CURVE('E789',#1609,#1609,#1607,.F.);
#1611=ORIENTED_EDGE('',*,*,#1610,.F.);
#1612=EDGE_LOOP('',(#1611));
#1613=FACE_BOUND('',#1612,.T.);
#1614=CARTESIAN_POINT('',(18.7324999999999,47.6249999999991,184.15));
#1615=DIRECTION('',(0.,1.,0.));
#1616=DIRECTION('',(0.,0.,1.));
#1617=AXIS2_PLACEMENT_3D('',#1614,#1615,#1616);
#1618=CIRCLE('',#1617,1.5875);
#1619=CARTESIAN_POINT('',(18.7324999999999,47.6249999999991,185.7375));
#1620=VERTEX_POINT('',#1619);
#1621=EDGE_CURVE('E785',#1620,#1620,#1618,.F.);
#1622=ORIENTED_EDGE('',*,*,#1621,.F.);
#1623=EDGE_LOOP('',(#1622));
#1624=FACE_BOUND('',#1623,.T.);
#1625=CARTESIAN_POINT('',(25.0824999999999,47.6249999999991,184.15));
#1626=DIRECTION('',(0.,1.,0.));
#1627=DIRECTION('',(0.,0.,1.));
#1628=AXIS2_PLACEMENT_3D('',#1625,#1626,#1627);
#1629=CIRCLE('',#1628,1.5875);
#1630=CARTESIAN_POINT('',(25.0824999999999,47.6249999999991,185.7375));
#1631=VERTEX_POINT('',#1630);
#1632=EDGE_CURVE('E781',#1631,#1631,#1629,.F.);
#1633=ORIENTED_EDGE('',*,*,#1632,.F.);
#1634=EDGE_LOOP('',(#1633));
#1635=FACE_BOUND('',#1634,.T.);
#1636=CARTESIAN_POINT('',(31.4324999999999,47.6249999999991,184.15));
#1637=DIRECTION('',(0.,1.,0.));
#1638=DIRECTION('',(0.,0.,1.));
#1639=AXIS2_PLACEMENT_3D('',#1636,#1637,#1638);
#1640=CIRCLE('',#1639,1.58750000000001);
#1641=CARTESIAN_POINT('',(31.4324999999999,47.6249999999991,185.7375));
#1642=VERTEX_POINT('',#1641);
#1643=EDGE_CURVE('E777',#1642,#1642,#1640,.F.);
#1644=ORIENTED_EDGE('',*,*,#1643,.F.);
#1645=EDGE_LOOP('',(#1644));
#1646=FACE_BOUND('',#1645,.T.);
#1647=CARTESIAN_POINT('',(12.3824999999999,47.6249999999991,177.8));
#1648=DIRECTION('',(0.,1.,0.));
#1649=DIRECTION('',(0.,0.,1.));
#1650=AXIS2_PLACEMENT_3D('',#1647,#1648,#1649);
#1651=CIRCLE('',#1650,1.5875);
#1652=CARTESIAN_POINT('',(12.3824999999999,47.6249999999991,179.3875));
#1653=VERTEX_POINT('',#1652);
#1654=EDGE_CURVE('E773',#1653,#1653,#1651,.F.);
#1655=ORIENTED_EDGE('',*,*,#1654,.F.);
#1656=EDGE_LOOP('',(#1655));
#1657=FACE_BOUND('',#1656,.T.);
#1658=CARTESIAN_POINT('',(18.7324999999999,47.6249999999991,177.8));
#1659=DIRECTION('',(0.,1.,0.));
#1660=DIRECTION('',(0.,0.,1.));
#1661=AXIS2_PLACEMENT_3D('',#1658,#1659,#1660);
#1662=CIRCLE('',#1661,1.5875);
#1663=CARTESIAN_POINT('',(18.7324999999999,47.6249999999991,179.3875));
#1664=VERTEX_POINT('',#1663);
#1665=EDGE_CURVE('E769',#1664,#1664,#1662,.F.);
#1666=ORIENTED_EDGE('',*,*,#1665,.F.);
#1667=EDGE_LOOP('',(#1666));
#1668=FACE_BOUND('',#1667,.T.);
#1669=CARTESIAN_POINT('',(25.0824999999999,47.6249999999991,177.8));
#1670=DIRECTION('',(0.,1.,0.));
#1671=DIRECTION('',(0.,0.,1.));
#1672=AXIS2_PLACEMENT_3D('',#1669,#1670,#1671);
#1673=CIRCLE('',#1672,1.5875);
#1674=CARTESIAN_POINT('',(25.0824999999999,47.6249999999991,179.3875));
#1675=VERTEX_POINT('',#1674);
#1676=EDGE_CURVE('E765',#1675,#1675,#1673,.F.);
#1677=ORIENTED_EDGE('',*,*,#1676,.F.);
#1678=EDGE_LOOP('',(#1677));
#1679=FACE_BOUND('',#1678,.T.);
#1680=CARTESIAN_POINT('',(31.4324999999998,47.6249999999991,177.8));
#1681=DIRECTION('',(0.,1.,0.));
#1682=DIRECTION('',(0.,0.,1.));
#1683=AXIS2_PLACEMENT_3D('',#1680,#1681,#1682);
#1684=CIRCLE('',#1683,1.5875);
#1685=CARTESIAN_POINT('',(31.4324999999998,47.6249999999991,179.3875));
#1686=VERTEX_POINT('',#1685);
#1687=EDGE_CURVE('E761',#1686,#1686,#1684,.F.);
#1688=ORIENTED_EDGE('',*,*,#1687,.F.);
#1689=EDGE_LOOP('',(#1688));
#1690=FACE_BOUND('',#1689,.T.);
#1691=CARTESIAN_POINT('',(12.3824999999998,47.6249999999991,171.45));
#1692=DIRECTION('',(0.,1.,0.));
#1693=DIRECTION('',(0.,0.,1.));
#1694=AXIS2_PLACEMENT_3D('',#1691,#1692,#1693);
#1695=CIRCLE('',#1694,1.5875);
#1696=CARTESIAN_POINT('',(12.3824999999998,47.6249999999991,173.0375));
#1697=VERTEX_POINT('',#1696);
#1698=EDGE_CURVE('E757',#1697,#1697,#1695,.F.);
#1699=ORIENTED_EDGE('',*,*,#1698,.F.);
#1700=EDGE_LOOP('',(#1699));
#1701=FACE_BOUND('',#1700,.T.);
#1702=CARTESIAN_POINT('',(18.7324999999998,47.6249999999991,171.45));
#1703=DIRECTION('',(0.,1.,0.));
#1704=DIRECTION('',(0.,0.,1.));
#1705=AXIS2_PLACEMENT_3D('',#1702,#1703,#1704);
#1706=CIRCLE('',#1705,1.5875);
#1707=CARTESIAN_POINT('',(18.7324999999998,47.6249999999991,173.0375));
#1708=VERTEX_POINT('',#1707);
#1709=EDGE_CURVE('E753',#1708,#1708,#1706,.F.);
#1710=ORIENTED_EDGE('',*,*,#1709,.F.);
#1711=EDGE_LOOP('',(#1710));
#1712=FACE_BOUND('',#1711,.T.);
#1713=CARTESIAN_POINT('',(25.0824999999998,47.6249999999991,171.45));
#1714=DIRECTION('',(0.,1.,0.));
#1715=DIRECTION('',(0.,0.,1.));
#1716=AXIS2_PLACEMENT_3D('',#1713,#1714,#1715);
#1717=CIRCLE('',#1716,1.5875);
#1718=CARTESIAN_POINT('',(25.0824999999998,47.6249999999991,173.0375));
#1719=VERTEX_POINT('',#1718);
#1720=EDGE_CURVE('E749',#1719,#1719,#1717,.F.);
#1721=ORIENTED_EDGE('',*,*,#1720,.F.);
#1722=EDGE_LOOP('',(#1721));
#1723=FACE_BOUND('',#1722,.T.);
#1724=CARTESIAN_POINT('',(31.4324999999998,47.6249999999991,171.45));
#1725=DIRECTION('',(0.,1.,0.));
#1726=DIRECTION('',(0.,0.,1.));
#1727=AXIS2_PLACEMENT_3D('',#1724,#1725,#1726);
#1728=CIRCLE('',#1727,1.5875);
#1729=CARTESIAN_POINT('',(31.4324999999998,47.6249999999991,173.0375));
#1730=VERTEX_POINT('',#1729);
#1731=EDGE_CURVE('E745',#1730,#1730,#1728,.F.);
#1732=ORIENTED_EDGE('',*,*,#1731,.F.);
#1733=EDGE_LOOP('',(#1732));
#1734=FACE_BOUND('',#1733,.T.);
#1735=CARTESIAN_POINT('',(12.3824999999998,47.6249999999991,165.1));
#1736=DIRECTION('',(0.,1.,0.));
#1737=DIRECTION('',(0.,0.,1.));
#1738=AXIS2_PLACEMENT_3D('',#1735,#1736,#1737);
#1739=CIRCLE('',#1738,1.5875);
#1740=CARTESIAN_POINT('',(12.3824999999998,47.6249999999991,166.6875));
#1741=VERTEX_POINT('',#1740);
#1742=EDGE_CURVE('E741',#1741,#1741,#1739,.F.);
#1743=ORIENTED_EDGE('',*,*,#1742,.F.);
#1744=EDGE_LOOP('',(#1743));
#1745=FACE_BOUND('',#1744,.T.);
#1746=CARTESIAN_POINT('',(18.7324999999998,47.6249999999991,165.1));
#1747=DIRECTION('',(0.,1.,0.));
#1748=DIRECTION('',(0.,0.,1.));
#1749=AXIS2_PLACEMENT_3D('',#1746,#1747,#1748);
#1750=CIRCLE('',#1749,1.5875);
#1751=CARTESIAN_POINT('',(18.7324999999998,47.6249999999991,166.6875));
#1752=VERTEX_POINT('',#1751);
#1753=EDGE_CURVE('E737',#1752,#1752,#1750,.F.);
#1754=ORIENTED_EDGE('',*,*,#1753,.F.);
#1755=EDGE_LOOP('',(#1754));
#1756=FACE_BOUND('',#1755,.T.);
#1757=CARTESIAN_POINT('',(25.0824999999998,47.6249999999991,165.1));
#1758=DIRECTION('',(0.,1.,0.));
#1759=DIRECTION('',(0.,0.,1.));
#1760=AXIS2_PLACEMENT_3D('',#1757,#1758,#1759);
#1761=CIRCLE('',#1760,1.5875);
#1762=CARTESIAN_POINT('',(25.0824999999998,47.6249999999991,166.6875));
#1763=VERTEX_POINT('',#1762);
#1764=EDGE_CURVE('E733',#1763,#1763,#1761,.F.);
#1765=ORIENTED_EDGE('',*,*,#1764,.F.);
#1766=EDGE_LOOP('',(#1765));
#1767=FACE_BOUND('',#1766,.T.);
#1768=CARTESIAN_POINT('',(31.4324999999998,47.6249999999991,165.1));
#1769=DIRECTION('',(0.,1.,0.));
#1770=DIRECTION('',(0.,0.,1.));
#1771=AXIS2_PLACEMENT_3D('',#1768,#1769,#1770);
#1772=CIRCLE('',#1771,1.58750000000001);
#1773=CARTESIAN_POINT('',(31.4324999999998,47.6249999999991,166.6875));
#1774=VERTEX_POINT('',#1773);
#1775=EDGE_CURVE('E729',#1774,#1774,#1772,.F.);
#1776=ORIENTED_EDGE('',*,*,#1775,.F.);
#1777=EDGE_LOOP('',(#1776));
#1778=FACE_BOUND('',#1777,.T.);
#1779=CARTESIAN_POINT('',(25.0824999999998,47.6249999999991,158.75));
#1780=DIRECTION('',(0.,1.,0.));
#1781=DIRECTION('',(0.,0.,1.));
#1782=AXIS2_PLACEMENT_3D('',#1779,#1780,#1781);
#1783=CIRCLE('',#1782,1.5875);
#1784=CARTESIAN_POINT('',(25.0824999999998,47.6249999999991,160.3375));
#1785=VERTEX_POINT('',#1784);
#1786=EDGE_CURVE('E725',#1785,#1785,#1783,.F.);
#1787=ORIENTED_EDGE('',*,*,#1786,.F.);
#1788=EDGE_LOOP('',(#1787));
#1789=FACE_BOUND('',#1788,.T.);
#1790=CARTESIAN_POINT('',(31.4324999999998,47.6249999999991,158.75));
#1791=DIRECTION('',(0.,1.,0.));
#1792=DIRECTION('',(0.,0.,1.));
#1793=AXIS2_PLACEMENT_3D('',#1790,#1791,#1792);
#1794=CIRCLE('',#1793,1.5875);
#1795=CARTESIAN_POINT('',(31.4324999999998,47.6249999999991,160.3375));
#1796=VERTEX_POINT('',#1795);
#1797=EDGE_CURVE('E721',#1796,#1796,#1794,.F.);
#1798=ORIENTED_EDGE('',*,*,#1797,.F.);
#1799=EDGE_LOOP('',(#1798));
#1800=FACE_BOUND('',#1799,.T.);
#1801=CARTESIAN_POINT('',(25.0824999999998,47.6249999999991,152.4));
#1802=DIRECTION('',(0.,1.,0.));
#1803=DIRECTION('',(0.,0.,1.));
#1804=AXIS2_PLACEMENT_3D('',#1801,#1802,#1803);
#1805=CIRCLE('',#1804,1.5875);
#1806=CARTESIAN_POINT('',(25.0824999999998,47.6249999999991,153.9875));
#1807=VERTEX_POINT('',#1806);
#1808=EDGE_CURVE('E717',#1807,#1807,#1805,.F.);
#1809=ORIENTED_EDGE('',*,*,#1808,.F.);
#1810=EDGE_LOOP('',(#1809));
#1811=FACE_BOUND('',#1810,.T.);
#1812=CARTESIAN_POINT('',(31.4324999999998,47.6249999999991,152.4));
#1813=DIRECTION('',(0.,1.,0.));
#1814=DIRECTION('',(0.,0.,1.));
#1815=AXIS2_PLACEMENT_3D('',#1812,#1813,#1814);
#1816=CIRCLE('',#1815,1.58750000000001);
#1817=CARTESIAN_POINT('',(31.4324999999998,47.6249999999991,153.9875));
#1818=VERTEX_POINT('',#1817);
#1819=EDGE_CURVE('E713',#1818,#1818,#1816,.F.);
#1820=ORIENTED_EDGE('',*,*,#1819,.F.);
#1821=EDGE_LOOP('',(#1820));
#1822=FACE_BOUND('',#1821,.T.);
#1823=CARTESIAN_POINT('',(25.0824999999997,47.6249999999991,146.05));
#1824=DIRECTION('',(0.,1.,0.));
#1825=DIRECTION('',(0.,0.,1.));
#1826=AXIS2_PLACEMENT_3D('',#1823,#1824,#1825);
#1827=CIRCLE('',#1826,1.5875);
#1828=CARTESIAN_POINT('',(25.0824999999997,47.6249999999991,147.6375));
#1829=VERTEX_POINT('',#1828);
#1830=EDGE_CURVE('E709',#1829,#1829,#1827,.F.);
#1831=ORIENTED_EDGE('',*,*,#1830,.F.);
#1832=EDGE_LOOP('',(#1831));
#1833=FACE_BOUND('',#1832,.T.);
#1834=CARTESIAN_POINT('',(31.4324999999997,47.6249999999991,146.05));
#1835=DIRECTION('',(0.,1.,0.));
#1836=DIRECTION('',(0.,0.,1.));
#1837=AXIS2_PLACEMENT_3D('',#1834,#1835,#1836);
#1838=CIRCLE('',#1837,1.5875);
#1839=CARTESIAN_POINT('',(31.4324999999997,47.6249999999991,147.6375));
#1840=VERTEX_POINT('',#1839);
#1841=EDGE_CURVE('E705',#1840,#1840,#1838,.F.);
#1842=ORIENTED_EDGE('',*,*,#1841,.F.);
#1843=EDGE_LOOP('',(#1842));
#1844=FACE_BOUND('',#1843,.T.);
#1845=CARTESIAN_POINT('',(25.0824999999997,47.6249999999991,139.7));
#1846=DIRECTION('',(0.,1.,0.));
#1847=DIRECTION('',(0.,0.,1.));
#1848=AXIS2_PLACEMENT_3D('',#1845,#1846,#1847);
#1849=CIRCLE('',#1848,1.5875);
#1850=CARTESIAN_POINT('',(25.0824999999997,47.6249999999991,141.2875));
#1851=VERTEX_POINT('',#1850);
#1852=EDGE_CURVE('E701',#1851,#1851,#1849,.F.);
#1853=ORIENTED_EDGE('',*,*,#1852,.F.);
#1854=EDGE_LOOP('',(#1853));
#1855=FACE_BOUND('',#1854,.T.);
#1856=CARTESIAN_POINT('',(31.4324999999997,47.6249999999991,139.7));
#1857=DIRECTION('',(0.,1.,0.));
#1858=DIRECTION('',(0.,0.,1.));
#1859=AXIS2_PLACEMENT_3D('',#1856,#1857,#1858);
#1860=CIRCLE('',#1859,1.5875);
#1861=CARTESIAN_POINT('',(31.4324999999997,47.6249999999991,141.2875));
#1862=VERTEX_POINT('',#1861);
#1863=EDGE_CURVE('E697',#1862,#1862,#1860,.F.);
#1864=ORIENTED_EDGE('',*,*,#1863,.F.);
#1865=EDGE_LOOP('',(#1864));
#1866=FACE_BOUND('',#1865,.T.);
#1867=CARTESIAN_POINT('',(25.0824999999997,47.6249999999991,133.35));
#1868=DIRECTION('',(0.,1.,0.));
#1869=DIRECTION('',(0.,0.,1.));
#1870=AXIS2_PLACEMENT_3D('',#1867,#1868,#1869);
#1871=CIRCLE('',#1870,1.5875);
#1872=CARTESIAN_POINT('',(25.0824999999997,47.6249999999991,134.9375));
#1873=VERTEX_POINT('',#1872);
#1874=EDGE_CURVE('E693',#1873,#1873,#1871,.F.);
#1875=ORIENTED_EDGE('',*,*,#1874,.F.);
#1876=EDGE_LOOP('',(#1875));
#1877=FACE_BOUND('',#1876,.T.);
#1878=CARTESIAN_POINT('',(31.4324999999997,47.6249999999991,133.35));
#1879=DIRECTION('',(0.,1.,0.));
#1880=DIRECTION('',(0.,0.,1.));
#1881=AXIS2_PLACEMENT_3D('',#1878,#1879,#1880);
#1882=CIRCLE('',#1881,1.5875);
#1883=CARTESIAN_POINT('',(31.4324999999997,47.6249999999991,134.9375));
#1884=VERTEX_POINT('',#1883);
#1885=EDGE_CURVE('E689',#1884,#1884,#1882,.F.);
#1886=ORIENTED_EDGE('',*,*,#1885,.F.);
#1887=EDGE_LOOP('',(#1886));
#1888=FACE_BOUND('',#1887,.T.);
#1889=CARTESIAN_POINT('',(25.0824999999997,47.6249999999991,127.));
#1890=DIRECTION('',(0.,1.,0.));
#1891=DIRECTION('',(0.,0.,1.));
#1892=AXIS2_PLACEMENT_3D('',#1889,#1890,#1891);
#1893=CIRCLE('',#1892,1.5875);
#1894=CARTESIAN_POINT('',(25.0824999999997,47.6249999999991,128.5875));
#1895=VERTEX_POINT('',#1894);
#1896=EDGE_CURVE('E685',#1895,#1895,#1893,.F.);
#1897=ORIENTED_EDGE('',*,*,#1896,.F.);
#1898=EDGE_LOOP('',(#1897));
#1899=FACE_BOUND('',#1898,.T.);
#1900=CARTESIAN_POINT('',(31.4324999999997,47.6249999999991,127.));
#1901=DIRECTION('',(0.,1.,0.));
#1902=DIRECTION('',(0.,0.,1.));
#1903=AXIS2_PLACEMENT_3D('',#1900,#1901,#1902);
#1904=CIRCLE('',#1903,1.5875);
#1905=CARTESIAN_POINT('',(31.4324999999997,47.6249999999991,128.5875));
#1906=VERTEX_POINT('',#1905);
#1907=EDGE_CURVE('E681',#1906,#1906,#1904,.F.);
#1908=ORIENTED_EDGE('',*,*,#1907,.F.);
#1909=EDGE_LOOP('',(#1908));
#1910=FACE_BOUND('',#1909,.T.);
#1911=CARTESIAN_POINT('',(25.0824999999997,47.6249999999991,120.65));
#1912=DIRECTION('',(0.,1.,0.));
#1913=DIRECTION('',(0.,0.,1.));
#1914=AXIS2_PLACEMENT_3D('',#1911,#1912,#1913);
#1915=CIRCLE('',#1914,1.5875);
#1916=CARTESIAN_POINT('',(25.0824999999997,47.6249999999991,122.2375));
#1917=VERTEX_POINT('',#1916);
#1918=EDGE_CURVE('E677',#1917,#1917,#1915,.F.);
#1919=ORIENTED_EDGE('',*,*,#1918,.F.);
#1920=EDGE_LOOP('',(#1919));
#1921=FACE_BOUND('',#1920,.T.);
#1922=CARTESIAN_POINT('',(31.4324999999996,47.6249999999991,120.65));
#1923=DIRECTION('',(0.,1.,0.));
#1924=DIRECTION('',(0.,0.,1.));
#1925=AXIS2_PLACEMENT_3D('',#1922,#1923,#1924);
#1926=CIRCLE('',#1925,1.58750000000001);
#1927=CARTESIAN_POINT('',(31.4324999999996,47.6249999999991,122.2375));
#1928=VERTEX_POINT('',#1927);
#1929=EDGE_CURVE('E673',#1928,#1928,#1926,.F.);
#1930=ORIENTED_EDGE('',*,*,#1929,.F.);
#1931=EDGE_LOOP('',(#1930));
#1932=FACE_BOUND('',#1931,.T.);
#1933=CARTESIAN_POINT('',(25.0824999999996,47.6249999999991,114.3));
#1934=DIRECTION('',(0.,1.,0.));
#1935=DIRECTION('',(0.,0.,1.));
#1936=AXIS2_PLACEMENT_3D('',#1933,#1934,#1935);
#1937=CIRCLE('',#1936,1.5875);
#1938=CARTESIAN_POINT('',(25.0824999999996,47.6249999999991,115.8875));
#1939=VERTEX_POINT('',#1938);
#1940=EDGE_CURVE('E669',#1939,#1939,#1937,.F.);
#1941=ORIENTED_EDGE('',*,*,#1940,.F.);
#1942=EDGE_LOOP('',(#1941));
#1943=FACE_BOUND('',#1942,.T.);
#1944=CARTESIAN_POINT('',(31.4324999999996,47.6249999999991,114.3));
#1945=DIRECTION('',(0.,1.,0.));
#1946=DIRECTION('',(0.,0.,1.));
#1947=AXIS2_PLACEMENT_3D('',#1944,#1945,#1946);
#1948=CIRCLE('',#1947,1.5875);
#1949=CARTESIAN_POINT('',(31.4324999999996,47.6249999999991,115.8875));
#1950=VERTEX_POINT('',#1949);
#1951=EDGE_CURVE('E665',#1950,#1950,#1948,.F.);
#1952=ORIENTED_EDGE('',*,*,#1951,.F.);
#1953=EDGE_LOOP('',(#1952));
#1954=FACE_BOUND('',#1953,.T.);
#1955=CARTESIAN_POINT('',(25.0824999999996,47.6249999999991,107.95));
#1956=DIRECTION('',(0.,1.,0.));
#1957=DIRECTION('',(0.,0.,1.));
#1958=AXIS2_PLACEMENT_3D('',#1955,#1956,#1957);
#1959=CIRCLE('',#1958,1.5875);
#1960=CARTESIAN_POINT('',(25.0824999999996,47.6249999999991,109.5375));
#1961=VERTEX_POINT('',#1960);
#1962=EDGE_CURVE('E661',#1961,#1961,#1959,.F.);
#1963=ORIENTED_EDGE('',*,*,#1962,.F.);
#1964=EDGE_LOOP('',(#1963));
#1965=FACE_BOUND('',#1964,.T.);
#1966=CARTESIAN_POINT('',(31.4324999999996,47.6249999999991,107.95));
#1967=DIRECTION('',(0.,1.,0.));
#1968=DIRECTION('',(0.,0.,1.));
#1969=AXIS2_PLACEMENT_3D('',#1966,#1967,#1968);
#1970=CIRCLE('',#1969,1.5875);
#1971=CARTESIAN_POINT('',(31.4324999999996,47.6249999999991,109.5375));
#1972=VERTEX_POINT('',#1971);
#1973=EDGE_CURVE('E657',#1972,#1972,#1970,.F.);
#1974=ORIENTED_EDGE('',*,*,#1973,.F.);
#1975=EDGE_LOOP('',(#1974));
#1976=FACE_BOUND('',#1975,.T.);
#1977=CARTESIAN_POINT('',(25.0824999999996,47.6249999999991,101.6));
#1978=DIRECTION('',(0.,1.,0.));
#1979=DIRECTION('',(0.,0.,1.));
#1980=AXIS2_PLACEMENT_3D('',#1977,#1978,#1979);
#1981=CIRCLE('',#1980,1.5875);
#1982=CARTESIAN_POINT('',(25.0824999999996,47.6249999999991,103.1875));
#1983=VERTEX_POINT('',#1982);
#1984=EDGE_CURVE('E653',#1983,#1983,#1981,.F.);
#1985=ORIENTED_EDGE('',*,*,#1984,.F.);
#1986=EDGE_LOOP('',(#1985));
#1987=FACE_BOUND('',#1986,.T.);
#1988=CARTESIAN_POINT('',(31.4324999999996,47.6249999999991,101.6));
#1989=DIRECTION('',(0.,1.,0.));
#1990=DIRECTION('',(0.,0.,1.));
#1991=AXIS2_PLACEMENT_3D('',#1988,#1989,#1990);
#1992=CIRCLE('',#1991,1.5875);
#1993=CARTESIAN_POINT('',(31.4324999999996,47.6249999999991,103.1875));
#1994=VERTEX_POINT('',#1993);
#1995=EDGE_CURVE('E649',#1994,#1994,#1992,.F.);
#1996=ORIENTED_EDGE('',*,*,#1995,.F.);
#1997=EDGE_LOOP('',(#1996));
#1998=FACE_BOUND('',#1997,.T.);
#1999=CARTESIAN_POINT('',(25.0824999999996,47.6249999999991,95.25));
#2000=DIRECTION('',(0.,1.,0.));
#2001=DIRECTION('',(0.,0.,1.));
#2002=AXIS2_PLACEMENT_3D('',#1999,#2000,#2001);
#2003=CIRCLE('',#2002,1.5875);
#2004=CARTESIAN_POINT('',(25.0824999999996,47.6249999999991,96.8375));
#2005=VERTEX_POINT('',#2004);
#2006=EDGE_CURVE('E645',#2005,#2005,#2003,.F.);
#2007=ORIENTED_EDGE('',*,*,#2006,.F.);
#2008=EDGE_LOOP('',(#2007));
#2009=FACE_BOUND('',#2008,.T.);
#2010=CARTESIAN_POINT('',(31.4324999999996,47.6249999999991,95.25));
#2011=DIRECTION('',(0.,1.,0.));
#2012=DIRECTION('',(0.,0.,1.));
#2013=AXIS2_PLACEMENT_3D('',#2010,#2011,#2012);
#2014=CIRCLE('',#2013,1.5875);
#2015=CARTESIAN_POINT('',(31.4324999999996,47.6249999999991,96.8375));
#2016=VERTEX_POINT('',#2015);
#2017=EDGE_CURVE('E641',#2016,#2016,#2014,.F.);
#2018=ORIENTED_EDGE('',*,*,#2017,.F.);
#2019=EDGE_LOOP('',(#2018));
#2020=FACE_BOUND('',#2019,.T.);
#2021=CARTESIAN_POINT('',(25.0824999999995,47.6249999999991,88.9));
#2022=DIRECTION('',(0.,1.,0.));
#2023=DIRECTION('',(0.,0.,1.));
#2024=AXIS2_PLACEMENT_3D('',#2021,#2022,#2023);
#2025=CIRCLE('',#2024,1.5875);
#2026=CARTESIAN_POINT('',(25.0824999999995,47.6249999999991,90.4875));
#2027=VERTEX_POINT('',#2026);
#2028=EDGE_CURVE('E637',#2027,#2027,#2025,.F.);
#2029=ORIENTED_EDGE('',*,*,#2028,.F.);
#2030=EDGE_LOOP('',(#2029));
#2031=FACE_BOUND('',#2030,.T.);
#2032=CARTESIAN_POINT('',(31.4324999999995,47.6249999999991,88.9));
#2033=DIRECTION('',(0.,1.,0.));
#2034=DIRECTION('',(0.,0.,1.));
#2035=AXIS2_PLACEMENT_3D('',#2032,#2033,#2034);
#2036=CIRCLE('',#2035,1.58750000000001);
#2037=CARTESIAN_POINT('',(31.4324999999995,47.6249999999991,90.4875));
#2038=VERTEX_POINT('',#2037);
#2039=EDGE_CURVE('E632',#2038,#2038,#2036,.F.);
#2040=ORIENTED_EDGE('',*,*,#2039,.F.);
#2041=EDGE_LOOP('',(#2040));
#2042=FACE_BOUND('',#2041,.T.);
#2043=CARTESIAN_POINT('',(6.03249999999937,47.6249999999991,38.1));
#2044=DIRECTION('',(0.,1.,0.));
#2045=DIRECTION('',(0.,0.,1.));
#2046=AXIS2_PLACEMENT_3D('',#2043,#2044,#2045);
#2047=CIRCLE('',#2046,1.5875);
#2048=CARTESIAN_POINT('',(6.03249999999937,47.6249999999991,39.6875));
#2049=VERTEX_POINT('',#2048);
#2050=EDGE_CURVE('E1016',#2049,#2049,#2047,.F.);
#2051=ORIENTED_EDGE('',*,*,#2050,.F.);
#2052=EDGE_LOOP('',(#2051));
#2053=FACE_BOUND('',#2052,.T.);
#2054=CARTESIAN_POINT('',(6.03249999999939,47.6249999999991,44.45));
#2055=DIRECTION('',(0.,1.,0.));
#2056=DIRECTION('',(0.,0.,1.));
#2057=AXIS2_PLACEMENT_3D('',#2054,#2055,#2056);
#2058=CIRCLE('',#2057,1.5875);
#2059=CARTESIAN_POINT('',(6.03249999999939,47.6249999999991,46.0375));
#2060=VERTEX_POINT('',#2059);
#2061=EDGE_CURVE('E1020',#2060,#2060,#2058,.F.);
#2062=ORIENTED_EDGE('',*,*,#2061,.F.);
#2063=EDGE_LOOP('',(#2062));
#2064=FACE_BOUND('',#2063,.T.);
#2065=CARTESIAN_POINT('',(6.03249999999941,47.6249999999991,50.8));
#2066=DIRECTION('',(0.,1.,0.));
#2067=DIRECTION('',(0.,0.,1.));
#2068=AXIS2_PLACEMENT_3D('',#2065,#2066,#2067);
#2069=CIRCLE('',#2068,1.5875);
#2070=CARTESIAN_POINT('',(6.03249999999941,47.6249999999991,52.3875));
#2071=VERTEX_POINT('',#2070);
#2072=EDGE_CURVE('E1024',#2071,#2071,#2069,.F.);
#2073=ORIENTED_EDGE('',*,*,#2072,.F.);
#2074=EDGE_LOOP('',(#2073));
#2075=FACE_BOUND('',#2074,.T.);
#2076=CARTESIAN_POINT('',(6.03249999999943,47.6249999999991,57.15));
#2077=DIRECTION('',(0.,1.,0.));
#2078=DIRECTION('',(0.,0.,1.));
#2079=AXIS2_PLACEMENT_3D('',#2076,#2077,#2078);
#2080=CIRCLE('',#2079,1.5875);
#2081=CARTESIAN_POINT('',(6.03249999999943,47.6249999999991,58.7375));
#2082=VERTEX_POINT('',#2081);
#2083=EDGE_CURVE('E1028',#2082,#2082,#2080,.F.);
#2084=ORIENTED_EDGE('',*,*,#2083,.F.);
#2085=EDGE_LOOP('',(#2084));
#2086=FACE_BOUND('',#2085,.T.);
#2087=CARTESIAN_POINT('',(6.03249999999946,47.6249999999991,63.5));
#2088=DIRECTION('',(0.,1.,0.));
#2089=DIRECTION('',(0.,0.,1.));
#2090=AXIS2_PLACEMENT_3D('',#2087,#2088,#2089);
#2091=CIRCLE('',#2090,1.5875);
#2092=CARTESIAN_POINT('',(6.03249999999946,47.6249999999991,65.0875));
#2093=VERTEX_POINT('',#2092);
#2094=EDGE_CURVE('E1032',#2093,#2093,#2091,.F.);
#2095=ORIENTED_EDGE('',*,*,#2094,.F.);
#2096=EDGE_LOOP('',(#2095));
#2097=FACE_BOUND('',#2096,.T.);
#2098=CARTESIAN_POINT('',(6.03249999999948,47.6249999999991,69.85));
#2099=DIRECTION('',(0.,1.,0.));
#2100=DIRECTION('',(0.,0.,1.));
#2101=AXIS2_PLACEMENT_3D('',#2098,#2099,#2100);
#2102=CIRCLE('',#2101,1.5875);
#2103=CARTESIAN_POINT('',(6.03249999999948,47.6249999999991,71.4375));
#2104=VERTEX_POINT('',#2103);
#2105=EDGE_CURVE('E1036',#2104,#2104,#2102,.F.);
#2106=ORIENTED_EDGE('',*,*,#2105,.F.);
#2107=EDGE_LOOP('',(#2106));
#2108=FACE_BOUND('',#2107,.T.);
#2109=CARTESIAN_POINT('',(6.0324999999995,47.6249999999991,76.2));
#2110=DIRECTION('',(0.,1.,0.));
#2111=DIRECTION('',(0.,0.,1.));
#2112=AXIS2_PLACEMENT_3D('',#2109,#2110,#2111);
#2113=CIRCLE('',#2112,1.5875);
#2114=CARTESIAN_POINT('',(6.0324999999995,47.6249999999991,77.7875));
#2115=VERTEX_POINT('',#2114);
#2116=EDGE_CURVE('E1040',#2115,#2115,#2113,.F.);
#2117=ORIENTED_EDGE('',*,*,#2116,.F.);
#2118=EDGE_LOOP('',(#2117));
#2119=FACE_BOUND('',#2118,.T.);
#2120=CARTESIAN_POINT('',(6.03249999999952,47.6249999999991,82.55));
#2121=DIRECTION('',(0.,1.,0.));
#2122=DIRECTION('',(0.,0.,1.));
#2123=AXIS2_PLACEMENT_3D('',#2120,#2121,#2122);
#2124=CIRCLE('',#2123,1.5875);
#2125=CARTESIAN_POINT('',(6.03249999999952,47.6249999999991,84.1375));
#2126=VERTEX_POINT('',#2125);
#2127=EDGE_CURVE('E1044',#2126,#2126,#2124,.F.);
#2128=ORIENTED_EDGE('',*,*,#2127,.F.);
#2129=EDGE_LOOP('',(#2128));
#2130=FACE_BOUND('',#2129,.T.);
#2131=CARTESIAN_POINT('',(6.03249999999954,47.6249999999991,88.9));
#2132=DIRECTION('',(0.,1.,0.));
#2133=DIRECTION('',(0.,0.,1.));
#2134=AXIS2_PLACEMENT_3D('',#2131,#2132,#2133);
#2135=CIRCLE('',#2134,1.5875);
#2136=CARTESIAN_POINT('',(6.03249999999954,47.6249999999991,90.4875));
#2137=VERTEX_POINT('',#2136);
#2138=EDGE_CURVE('E1048',#2137,#2137,#2135,.F.);
#2139=ORIENTED_EDGE('',*,*,#2138,.F.);
#2140=EDGE_LOOP('',(#2139));
#2141=FACE_BOUND('',#2140,.T.);
#2142=CARTESIAN_POINT('',(6.03249999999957,47.6249999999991,95.25));
#2143=DIRECTION('',(0.,1.,0.));
#2144=DIRECTION('',(0.,0.,1.));
#2145=AXIS2_PLACEMENT_3D('',#2142,#2143,#2144);
#2146=CIRCLE('',#2145,1.5875);
#2147=CARTESIAN_POINT('',(6.03249999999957,47.6249999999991,96.8375));
#2148=VERTEX_POINT('',#2147);
#2149=EDGE_CURVE('E1052',#2148,#2148,#2146,.F.);
#2150=ORIENTED_EDGE('',*,*,#2149,.F.);
#2151=EDGE_LOOP('',(#2150));
#2152=FACE_BOUND('',#2151,.T.);
#2153=CARTESIAN_POINT('',(6.03249999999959,47.6249999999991,101.6));
#2154=DIRECTION('',(0.,1.,0.));
#2155=DIRECTION('',(0.,0.,1.));
#2156=AXIS2_PLACEMENT_3D('',#2153,#2154,#2155);
#2157=CIRCLE('',#2156,1.5875);
#2158=CARTESIAN_POINT('',(6.03249999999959,47.6249999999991,103.1875));
#2159=VERTEX_POINT('',#2158);
#2160=EDGE_CURVE('E1056',#2159,#2159,#2157,.F.);
#2161=ORIENTED_EDGE('',*,*,#2160,.F.);
#2162=EDGE_LOOP('',(#2161));
#2163=FACE_BOUND('',#2162,.T.);
#2164=CARTESIAN_POINT('',(6.03249999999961,47.6249999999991,107.95));
#2165=DIRECTION('',(0.,1.,0.));
#2166=DIRECTION('',(0.,0.,1.));
#2167=AXIS2_PLACEMENT_3D('',#2164,#2165,#2166);
#2168=CIRCLE('',#2167,1.5875);
#2169=CARTESIAN_POINT('',(6.03249999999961,47.6249999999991,109.5375));
#2170=VERTEX_POINT('',#2169);
#2171=EDGE_CURVE('E1060',#2170,#2170,#2168,.F.);
#2172=ORIENTED_EDGE('',*,*,#2171,.F.);
#2173=EDGE_LOOP('',(#2172));
#2174=FACE_BOUND('',#2173,.T.);
#2175=CARTESIAN_POINT('',(6.03249999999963,47.6249999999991,114.3));
#2176=DIRECTION('',(0.,1.,0.));
#2177=DIRECTION('',(0.,0.,1.));
#2178=AXIS2_PLACEMENT_3D('',#2175,#2176,#2177);
#2179=CIRCLE('',#2178,1.5875);
#2180=CARTESIAN_POINT('',(6.03249999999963,47.6249999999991,115.8875));
#2181=VERTEX_POINT('',#2180);
#2182=EDGE_CURVE('E892',#2181,#2181,#2179,.F.);
#2183=ORIENTED_EDGE('',*,*,#2182,.F.);
#2184=EDGE_LOOP('',(#2183));
#2185=FACE_BOUND('',#2184,.T.);
#2186=CARTESIAN_POINT('',(6.03249999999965,47.6249999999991,120.65));
#2187=DIRECTION('',(0.,1.,0.));
#2188=DIRECTION('',(0.,0.,1.));
#2189=AXIS2_PLACEMENT_3D('',#2186,#2187,#2188);
#2190=CIRCLE('',#2189,1.5875);
#2191=CARTESIAN_POINT('',(6.03249999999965,47.6249999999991,122.2375));
#2192=VERTEX_POINT('',#2191);
#2193=EDGE_CURVE('E888',#2192,#2192,#2190,.F.);
#2194=ORIENTED_EDGE('',*,*,#2193,.F.);
#2195=EDGE_LOOP('',(#2194));
#2196=FACE_BOUND('',#2195,.T.);
#2197=CARTESIAN_POINT('',(6.03249999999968,47.6249999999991,127.));
#2198=DIRECTION('',(0.,1.,0.));
#2199=DIRECTION('',(0.,0.,1.));
#2200=AXIS2_PLACEMENT_3D('',#2197,#2198,#2199);
#2201=CIRCLE('',#2200,1.5875);
#2202=CARTESIAN_POINT('',(6.03249999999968,47.6249999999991,128.5875));
#2203=VERTEX_POINT('',#2202);
#2204=EDGE_CURVE('E893',#2203,#2203,#2201,.F.);
#2205=ORIENTED_EDGE('',*,*,#2204,.F.);
#2206=EDGE_LOOP('',(#2205));
#2207=FACE_BOUND('',#2206,.T.);
#2208=CARTESIAN_POINT('',(6.0324999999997,47.6249999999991,133.35));
#2209=DIRECTION('',(0.,1.,0.));
#2210=DIRECTION('',(0.,0.,1.));
#2211=AXIS2_PLACEMENT_3D('',#2208,#2209,#2210);
#2212=CIRCLE('',#2211,1.5875);
#2213=CARTESIAN_POINT('',(6.0324999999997,47.6249999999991,134.9375));
#2214=VERTEX_POINT('',#2213);
#2215=EDGE_CURVE('E897',#2214,#2214,#2212,.F.);
#2216=ORIENTED_EDGE('',*,*,#2215,.F.);
#2217=EDGE_LOOP('',(#2216));
#2218=FACE_BOUND('',#2217,.T.);
#2219=CARTESIAN_POINT('',(6.03249999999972,47.6249999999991,139.7));
#2220=DIRECTION('',(0.,1.,0.));
#2221=DIRECTION('',(0.,0.,1.));
#2222=AXIS2_PLACEMENT_3D('',#2219,#2220,#2221);
#2223=CIRCLE('',#2222,1.5875);
#2224=CARTESIAN_POINT('',(6.03249999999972,47.6249999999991,141.2875));
#2225=VERTEX_POINT('',#2224);
#2226=EDGE_CURVE('E901',#2225,#2225,#2223,.F.);
#2227=ORIENTED_EDGE('',*,*,#2226,.F.);
#2228=EDGE_LOOP('',(#2227));
#2229=FACE_BOUND('',#2228,.T.);
#2230=CARTESIAN_POINT('',(6.03249999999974,47.6249999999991,146.05));
#2231=DIRECTION('',(0.,1.,0.));
#2232=DIRECTION('',(0.,0.,1.));
#2233=AXIS2_PLACEMENT_3D('',#2230,#2231,#2232);
#2234=CIRCLE('',#2233,1.5875);
#2235=CARTESIAN_POINT('',(6.03249999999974,47.6249999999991,147.6375));
#2236=VERTEX_POINT('',#2235);
#2237=EDGE_CURVE('E905',#2236,#2236,#2234,.F.);
#2238=ORIENTED_EDGE('',*,*,#2237,.F.);
#2239=EDGE_LOOP('',(#2238));
#2240=FACE_BOUND('',#2239,.T.);
#2241=CARTESIAN_POINT('',(6.03249999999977,47.6249999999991,152.4));
#2242=DIRECTION('',(0.,1.,0.));
#2243=DIRECTION('',(0.,0.,1.));
#2244=AXIS2_PLACEMENT_3D('',#2241,#2242,#2243);
#2245=CIRCLE('',#2244,1.5875);
#2246=CARTESIAN_POINT('',(6.03249999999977,47.6249999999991,153.9875));
#2247=VERTEX_POINT('',#2246);
#2248=EDGE_CURVE('E909',#2247,#2247,#2245,.F.);
#2249=ORIENTED_EDGE('',*,*,#2248,.F.);
#2250=EDGE_LOOP('',(#2249));
#2251=FACE_BOUND('',#2250,.T.);
#2252=CARTESIAN_POINT('',(6.03249999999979,47.6249999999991,158.75));
#2253=DIRECTION('',(0.,1.,0.));
#2254=DIRECTION('',(0.,0.,1.));
#2255=AXIS2_PLACEMENT_3D('',#2252,#2253,#2254);
#2256=CIRCLE('',#2255,1.5875);
#2257=CARTESIAN_POINT('',(6.03249999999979,47.6249999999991,160.3375));
#2258=VERTEX_POINT('',#2257);
#2259=EDGE_CURVE('E913',#2258,#2258,#2256,.F.);
#2260=ORIENTED_EDGE('',*,*,#2259,.F.);
#2261=EDGE_LOOP('',(#2260));
#2262=FACE_BOUND('',#2261,.T.);
#2263=CARTESIAN_POINT('',(6.03249999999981,47.6249999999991,165.1));
#2264=DIRECTION('',(0.,1.,0.));
#2265=DIRECTION('',(0.,0.,1.));
#2266=AXIS2_PLACEMENT_3D('',#2263,#2264,#2265);
#2267=CIRCLE('',#2266,1.5875);
#2268=CARTESIAN_POINT('',(6.03249999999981,47.6249999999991,166.6875));
#2269=VERTEX_POINT('',#2268);
#2270=EDGE_CURVE('E917',#2269,#2269,#2267,.F.);
#2271=ORIENTED_EDGE('',*,*,#2270,.F.);
#2272=EDGE_LOOP('',(#2271));
#2273=FACE_BOUND('',#2272,.T.);
#2274=CARTESIAN_POINT('',(6.03249999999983,47.6249999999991,171.45));
#2275=DIRECTION('',(0.,1.,0.));
#2276=DIRECTION('',(0.,0.,1.));
#2277=AXIS2_PLACEMENT_3D('',#2274,#2275,#2276);
#2278=CIRCLE('',#2277,1.5875);
#2279=CARTESIAN_POINT('',(6.03249999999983,47.6249999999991,173.0375));
#2280=VERTEX_POINT('',#2279);
#2281=EDGE_CURVE('E921',#2280,#2280,#2278,.F.);
#2282=ORIENTED_EDGE('',*,*,#2281,.F.);
#2283=EDGE_LOOP('',(#2282));
#2284=FACE_BOUND('',#2283,.T.);
#2285=CARTESIAN_POINT('',(6.03249999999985,47.6249999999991,177.8));
#2286=DIRECTION('',(0.,1.,0.));
#2287=DIRECTION('',(0.,0.,1.));
#2288=AXIS2_PLACEMENT_3D('',#2285,#2286,#2287);
#2289=CIRCLE('',#2288,1.5875);
#2290=CARTESIAN_POINT('',(6.03249999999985,47.6249999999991,179.3875));
#2291=VERTEX_POINT('',#2290);
#2292=EDGE_CURVE('E925',#2291,#2291,#2289,.F.);
#2293=ORIENTED_EDGE('',*,*,#2292,.F.);
#2294=EDGE_LOOP('',(#2293));
#2295=FACE_BOUND('',#2294,.T.);
#2296=CARTESIAN_POINT('',(6.03249999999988,47.6249999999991,184.15));
#2297=DIRECTION('',(0.,1.,0.));
#2298=DIRECTION('',(0.,0.,1.));
#2299=AXIS2_PLACEMENT_3D('',#2296,#2297,#2298);
#2300=CIRCLE('',#2299,1.5875);
#2301=CARTESIAN_POINT('',(6.03249999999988,47.6249999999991,185.7375));
#2302=VERTEX_POINT('',#2301);
#2303=EDGE_CURVE('E929',#2302,#2302,#2300,.F.);
#2304=ORIENTED_EDGE('',*,*,#2303,.F.);
#2305=EDGE_LOOP('',(#2304));
#2306=FACE_BOUND('',#2305,.T.);
#2307=CARTESIAN_POINT('',(6.0324999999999,47.6249999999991,190.5));
#2308=DIRECTION('',(0.,1.,0.));
#2309=DIRECTION('',(0.,0.,1.));
#2310=AXIS2_PLACEMENT_3D('',#2307,#2308,#2309);
#2311=CIRCLE('',#2310,1.5875);
#2312=CARTESIAN_POINT('',(6.0324999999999,47.6249999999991,192.0875));
#2313=VERTEX_POINT('',#2312);
#2314=EDGE_CURVE('E933',#2313,#2313,#2311,.F.);
#2315=ORIENTED_EDGE('',*,*,#2314,.F.);
#2316=EDGE_LOOP('',(#2315));
#2317=FACE_BOUND('',#2316,.T.);
#2318=CARTESIAN_POINT('',(6.03249999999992,47.6249999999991,196.85));
#2319=DIRECTION('',(0.,1.,0.));
#2320=DIRECTION('',(0.,0.,1.));
#2321=AXIS2_PLACEMENT_3D('',#2318,#2319,#2320);
#2322=CIRCLE('',#2321,1.5875);
#2323=CARTESIAN_POINT('',(6.03249999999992,47.6249999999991,198.4375));
#2324=VERTEX_POINT('',#2323);
#2325=EDGE_CURVE('E937',#2324,#2324,#2322,.F.);
#2326=ORIENTED_EDGE('',*,*,#2325,.F.);
#2327=EDGE_LOOP('',(#2326));
#2328=FACE_BOUND('',#2327,.T.);
#2329=CARTESIAN_POINT('',(6.03249999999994,47.6249999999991,203.2));
#2330=DIRECTION('',(0.,1.,0.));
#2331=DIRECTION('',(0.,0.,1.));
#2332=AXIS2_PLACEMENT_3D('',#2329,#2330,#2331);
#2333=CIRCLE('',#2332,1.5875);
#2334=CARTESIAN_POINT('',(6.03249999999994,47.6249999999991,204.7875));
#2335=VERTEX_POINT('',#2334);
#2336=EDGE_CURVE('E941',#2335,#2335,#2333,.F.);
#2337=ORIENTED_EDGE('',*,*,#2336,.F.);
#2338=EDGE_LOOP('',(#2337));
#2339=FACE_BOUND('',#2338,.T.);
#2340=CARTESIAN_POINT('',(6.03249999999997,47.6249999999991,209.55));
#2341=DIRECTION('',(0.,1.,0.));
#2342=DIRECTION('',(0.,0.,1.));
#2343=AXIS2_PLACEMENT_3D('',#2340,#2341,#2342);
#2344=CIRCLE('',#2343,1.5875);
#2345=CARTESIAN_POINT('',(6.03249999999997,47.6249999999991,211.1375));
#2346=VERTEX_POINT('',#2345);
#2347=EDGE_CURVE('E945',#2346,#2346,#2344,.F.);
#2348=ORIENTED_EDGE('',*,*,#2347,.F.);
#2349=EDGE_LOOP('',(#2348));
#2350=FACE_BOUND('',#2349,.T.);
#2351=CARTESIAN_POINT('',(6.03249999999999,47.6249999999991,215.9));
#2352=DIRECTION('',(0.,1.,0.));
#2353=DIRECTION('',(0.,0.,1.));
#2354=AXIS2_PLACEMENT_3D('',#2351,#2352,#2353);
#2355=CIRCLE('',#2354,1.5875);
#2356=CARTESIAN_POINT('',(6.03249999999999,47.6249999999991,217.4875));
#2357=VERTEX_POINT('',#2356);
#2358=EDGE_CURVE('E949',#2357,#2357,#2355,.F.);
#2359=ORIENTED_EDGE('',*,*,#2358,.F.);
#2360=EDGE_LOOP('',(#2359));
#2361=FACE_BOUND('',#2360,.T.);
#2362=CARTESIAN_POINT('',(31.4324999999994,47.6249999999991,38.1));
#2363=DIRECTION('',(0.,1.,0.));
#2364=DIRECTION('',(0.,0.,1.));
#2365=AXIS2_PLACEMENT_3D('',#2362,#2363,#2364);
#2366=CIRCLE('',#2365,1.5875);
#2367=CARTESIAN_POINT('',(31.4324999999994,47.6249999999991,39.6875));
#2368=VERTEX_POINT('',#2367);
#2369=EDGE_CURVE('E953',#2368,#2368,#2366,.F.);
#2370=ORIENTED_EDGE('',*,*,#2369,.F.);
#2371=EDGE_LOOP('',(#2370));
#2372=FACE_BOUND('',#2371,.T.);
#2373=CARTESIAN_POINT('',(25.0824999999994,47.6249999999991,38.1));
#2374=DIRECTION('',(0.,1.,0.));
#2375=DIRECTION('',(0.,0.,1.));
#2376=AXIS2_PLACEMENT_3D('',#2373,#2374,#2375);
#2377=CIRCLE('',#2376,1.5875);
#2378=CARTESIAN_POINT('',(25.0824999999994,47.6249999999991,39.6875));
#2379=VERTEX_POINT('',#2378);
#2380=EDGE_CURVE('E957',#2379,#2379,#2377,.F.);
#2381=ORIENTED_EDGE('',*,*,#2380,.F.);
#2382=EDGE_LOOP('',(#2381));
#2383=FACE_BOUND('',#2382,.T.);
#2384=CARTESIAN_POINT('',(31.4324999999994,47.6249999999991,44.45));
#2385=DIRECTION('',(0.,1.,0.));
#2386=DIRECTION('',(0.,0.,1.));
#2387=AXIS2_PLACEMENT_3D('',#2384,#2385,#2386);
#2388=CIRCLE('',#2387,1.5875);
#2389=CARTESIAN_POINT('',(31.4324999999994,47.6249999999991,46.0375));
#2390=VERTEX_POINT('',#2389);
#2391=EDGE_CURVE('E961',#2390,#2390,#2388,.F.);
#2392=ORIENTED_EDGE('',*,*,#2391,.F.);
#2393=EDGE_LOOP('',(#2392));
#2394=FACE_BOUND('',#2393,.T.);
#2395=CARTESIAN_POINT('',(25.0824999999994,47.6249999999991,44.45));
#2396=DIRECTION('',(0.,1.,0.));
#2397=DIRECTION('',(0.,0.,1.));
#2398=AXIS2_PLACEMENT_3D('',#2395,#2396,#2397);
#2399=CIRCLE('',#2398,1.5875);
#2400=CARTESIAN_POINT('',(25.0824999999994,47.6249999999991,46.0375));
#2401=VERTEX_POINT('',#2400);
#2402=EDGE_CURVE('E965',#2401,#2401,#2399,.F.);
#2403=ORIENTED_EDGE('',*,*,#2402,.F.);
#2404=EDGE_LOOP('',(#2403));
#2405=FACE_BOUND('',#2404,.T.);
#2406=CARTESIAN_POINT('',(31.4324999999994,47.6249999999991,50.8));
#2407=DIRECTION('',(0.,1.,0.));
#2408=DIRECTION('',(0.,0.,1.));
#2409=AXIS2_PLACEMENT_3D('',#2406,#2407,#2408);
#2410=CIRCLE('',#2409,1.5875);
#2411=CARTESIAN_POINT('',(31.4324999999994,47.6249999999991,52.3875));
#2412=VERTEX_POINT('',#2411);
#2413=EDGE_CURVE('E969',#2412,#2412,#2410,.F.);
#2414=ORIENTED_EDGE('',*,*,#2413,.F.);
#2415=EDGE_LOOP('',(#2414));
#2416=FACE_BOUND('',#2415,.T.);
#2417=CARTESIAN_POINT('',(25.0824999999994,47.6249999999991,50.8));
#2418=DIRECTION('',(0.,1.,0.));
#2419=DIRECTION('',(0.,0.,1.));
#2420=AXIS2_PLACEMENT_3D('',#2417,#2418,#2419);
#2421=CIRCLE('',#2420,1.5875);
#2422=CARTESIAN_POINT('',(25.0824999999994,47.6249999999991,52.3875));
#2423=VERTEX_POINT('',#2422);
#2424=EDGE_CURVE('E973',#2423,#2423,#2421,.F.);
#2425=ORIENTED_EDGE('',*,*,#2424,.F.);
#2426=EDGE_LOOP('',(#2425));
#2427=FACE_BOUND('',#2426,.T.);
#2428=CARTESIAN_POINT('',(31.4324999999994,47.6249999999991,57.15));
#2429=DIRECTION('',(0.,1.,0.));
#2430=DIRECTION('',(0.,0.,1.));
#2431=AXIS2_PLACEMENT_3D('',#2428,#2429,#2430);
#2432=CIRCLE('',#2431,1.58750000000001);
#2433=CARTESIAN_POINT('',(31.4324999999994,47.6249999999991,58.7375));
#2434=VERTEX_POINT('',#2433);
#2435=EDGE_CURVE('E977',#2434,#2434,#2432,.F.);
#2436=ORIENTED_EDGE('',*,*,#2435,.F.);
#2437=EDGE_LOOP('',(#2436));
#2438=FACE_BOUND('',#2437,.T.);
#2439=CARTESIAN_POINT('',(25.0824999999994,47.6249999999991,57.15));
#2440=DIRECTION('',(0.,1.,0.));
#2441=DIRECTION('',(0.,0.,1.));
#2442=AXIS2_PLACEMENT_3D('',#2439,#2440,#2441);
#2443=CIRCLE('',#2442,1.5875);
#2444=CARTESIAN_POINT('',(25.0824999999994,47.6249999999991,58.7375));
#2445=VERTEX_POINT('',#2444);
#2446=EDGE_CURVE('E981',#2445,#2445,#2443,.F.);
#2447=ORIENTED_EDGE('',*,*,#2446,.F.);
#2448=EDGE_LOOP('',(#2447));
#2449=FACE_BOUND('',#2448,.T.);
#2450=CARTESIAN_POINT('',(31.4324999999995,47.6249999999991,63.5));
#2451=DIRECTION('',(0.,1.,0.));
#2452=DIRECTION('',(0.,0.,1.));
#2453=AXIS2_PLACEMENT_3D('',#2450,#2451,#2452);
#2454=CIRCLE('',#2453,1.5875);
#2455=CARTESIAN_POINT('',(31.4324999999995,47.6249999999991,65.0875));
#2456=VERTEX_POINT('',#2455);
#2457=EDGE_CURVE('E985',#2456,#2456,#2454,.F.);
#2458=ORIENTED_EDGE('',*,*,#2457,.F.);
#2459=EDGE_LOOP('',(#2458));
#2460=FACE_BOUND('',#2459,.T.);
#2461=CARTESIAN_POINT('',(25.0824999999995,47.6249999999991,63.5));
#2462=DIRECTION('',(0.,1.,0.));
#2463=DIRECTION('',(0.,0.,1.));
#2464=AXIS2_PLACEMENT_3D('',#2461,#2462,#2463);
#2465=CIRCLE('',#2464,1.5875);
#2466=CARTESIAN_POINT('',(25.0824999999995,47.6249999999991,65.0875));
#2467=VERTEX_POINT('',#2466);
#2468=EDGE_CURVE('E989',#2467,#2467,#2465,.F.);
#2469=ORIENTED_EDGE('',*,*,#2468,.F.);
#2470=EDGE_LOOP('',(#2469));
#2471=FACE_BOUND('',#2470,.T.);
#2472=CARTESIAN_POINT('',(31.4324999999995,47.6249999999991,69.85));
#2473=DIRECTION('',(0.,1.,0.));
#2474=DIRECTION('',(0.,0.,1.));
#2475=AXIS2_PLACEMENT_3D('',#2472,#2473,#2474);
#2476=CIRCLE('',#2475,1.5875);
#2477=CARTESIAN_POINT('',(31.4324999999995,47.6249999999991,71.4375));
#2478=VERTEX_POINT('',#2477);
#2479=EDGE_CURVE('E993',#2478,#2478,#2476,.F.);
#2480=ORIENTED_EDGE('',*,*,#2479,.F.);
#2481=EDGE_LOOP('',(#2480));
#2482=FACE_BOUND('',#2481,.T.);
#2483=CARTESIAN_POINT('',(25.0824999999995,47.6249999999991,69.85));
#2484=DIRECTION('',(0.,1.,0.));
#2485=DIRECTION('',(0.,0.,1.));
#2486=AXIS2_PLACEMENT_3D('',#2483,#2484,#2485);
#2487=CIRCLE('',#2486,1.5875);
#2488=CARTESIAN_POINT('',(25.0824999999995,47.6249999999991,71.4375));
#2489=VERTEX_POINT('',#2488);
#2490=EDGE_CURVE('E997',#2489,#2489,#2487,.F.);
#2491=ORIENTED_EDGE('',*,*,#2490,.F.);
#2492=EDGE_LOOP('',(#2491));
#2493=FACE_BOUND('',#2492,.T.);
#2494=CARTESIAN_POINT('',(31.4324999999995,47.6249999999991,76.2));
#2495=DIRECTION('',(0.,1.,0.));
#2496=DIRECTION('',(0.,0.,1.));
#2497=AXIS2_PLACEMENT_3D('',#2494,#2495,#2496);
#2498=CIRCLE('',#2497,1.5875);
#2499=CARTESIAN_POINT('',(31.4324999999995,47.6249999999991,77.7875));
#2500=VERTEX_POINT('',#2499);
#2501=EDGE_CURVE('E1001',#2500,#2500,#2498,.F.);
#2502=ORIENTED_EDGE('',*,*,#2501,.F.);
#2503=EDGE_LOOP('',(#2502));
#2504=FACE_BOUND('',#2503,.T.);
#2505=CARTESIAN_POINT('',(25.0824999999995,47.6249999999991,76.2));
#2506=DIRECTION('',(0.,1.,0.));
#2507=DIRECTION('',(0.,0.,1.));
#2508=AXIS2_PLACEMENT_3D('',#2505,#2506,#2507);
#2509=CIRCLE('',#2508,1.5875);
#2510=CARTESIAN_POINT('',(25.0824999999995,47.6249999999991,77.7875));
#2511=VERTEX_POINT('',#2510);
#2512=EDGE_CURVE('E1005',#2511,#2511,#2509,.F.);
#2513=ORIENTED_EDGE('',*,*,#2512,.F.);
#2514=EDGE_LOOP('',(#2513));
#2515=FACE_BOUND('',#2514,.T.);
#2516=CARTESIAN_POINT('',(31.4324999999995,47.6249999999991,82.55));
#2517=DIRECTION('',(0.,1.,0.));
#2518=DIRECTION('',(0.,0.,1.));
#2519=AXIS2_PLACEMENT_3D('',#2516,#2517,#2518);
#2520=CIRCLE('',#2519,1.5875);
#2521=CARTESIAN_POINT('',(31.4324999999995,47.6249999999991,84.1375));
#2522=VERTEX_POINT('',#2521);
#2523=EDGE_CURVE('E1009',#2522,#2522,#2520,.F.);
#2524=ORIENTED_EDGE('',*,*,#2523,.F.);
#2525=EDGE_LOOP('',(#2524));
#2526=FACE_BOUND('',#2525,.T.);
#2527=CARTESIAN_POINT('',(25.0824999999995,47.6249999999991,82.55));
#2528=DIRECTION('',(0.,1.,0.));
#2529=DIRECTION('',(0.,0.,1.));
#2530=AXIS2_PLACEMENT_3D('',#2527,#2528,#2529);
#2531=CIRCLE('',#2530,1.5875);
#2532=CARTESIAN_POINT('',(25.0824999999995,47.6249999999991,84.1375));
#2533=VERTEX_POINT('',#2532);
#2534=EDGE_CURVE('E636',#2533,#2533,#2531,.F.);
#2535=ORIENTED_EDGE('',*,*,#2534,.F.);
#2536=EDGE_LOOP('',(#2535));
#2537=FACE_BOUND('',#2536,.T.);
#2538=CARTESIAN_POINT('',(6.03250000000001,47.6249999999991,222.25));
#2539=DIRECTION('',(0.,1.,0.));
#2540=DIRECTION('',(0.,0.,1.));
#2541=AXIS2_PLACEMENT_3D('',#2538,#2539,#2540);
#2542=CIRCLE('',#2541,1.5875);
#2543=CARTESIAN_POINT('',(6.03250000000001,47.6249999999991,223.8375));
#2544=VERTEX_POINT('',#2543);
#2545=EDGE_CURVE('E627',#2544,#2544,#2542,.F.);
#2546=ORIENTED_EDGE('',*,*,#2545,.F.);
#2547=EDGE_LOOP('',(#2546));
#2548=FACE_BOUND('',#2547,.T.);
#2549=DIRECTION('',(-1.,0.,0.));
#2550=VECTOR('',#2549,1.);
#2551=CARTESIAN_POINT('',(18.7325,47.6249999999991,157.48));
#2552=LINE('',#2551,#2550);
#2553=CARTESIAN_POINT('',(18.7325,47.6249999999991,157.48));
#2554=VERTEX_POINT('',#2553);
#2555=CARTESIAN_POINT('',(12.1285,47.6249999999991,157.48));
#2556=VERTEX_POINT('',#2555);
#2557=EDGE_CURVE('E622',#2554,#2556,#2552,.T.);
#2558=ORIENTED_EDGE('',*,*,#2557,.F.);
#2559=DIRECTION('',(0.,0.,1.));
#2560=VECTOR('',#2559,1.);
#2561=CARTESIAN_POINT('',(18.7325,47.6249999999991,5.08));
#2562=LINE('',#2561,#2560);
#2563=CARTESIAN_POINT('',(18.7325,47.6249999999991,5.08));
#2564=VERTEX_POINT('',#2563);
#2565=EDGE_CURVE('E600',#2564,#2554,#2562,.T.);
#2566=ORIENTED_EDGE('',*,*,#2565,.F.);
#2567=DIRECTION('',(1.,0.,0.));
#2568=VECTOR('',#2567,1.);
#2569=CARTESIAN_POINT('',(18.7325,47.6249999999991,5.08));
#2570=LINE('',#2569,#2568);
#2571=CARTESIAN_POINT('',(12.1285,47.6249999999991,5.08));
#2572=VERTEX_POINT('',#2571);
#2573=EDGE_CURVE('E133',#2572,#2564,#2570,.T.);
#2574=ORIENTED_EDGE('',*,*,#2573,.F.);
#2575=DIRECTION('',(0.,0.,-1.));
#2576=VECTOR('',#2575,1.);
#2577=CARTESIAN_POINT('',(12.1285,47.6249999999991,5.08));
#2578=LINE('',#2577,#2576);
#2579=EDGE_CURVE('E623',#2556,#2572,#2578,.T.);
#2580=ORIENTED_EDGE('',*,*,#2579,.F.);
#2581=EDGE_LOOP('',(#2558,#2566,#2574,#2580));
#2582=FACE_BOUND('',#2581,.T.);
#2583=DIRECTION('',(1.,0.,0.));
#2584=VECTOR('',#2583,1.);
#2585=CARTESIAN_POINT('',(1.5875,47.6249999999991,0.));
#2586=LINE('',#2585,#2584);
#2587=CARTESIAN_POINT('',(36.5125,47.6249999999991,0.));
#2588=VERTEX_POINT('',#2587);
#2589=EDGE_CURVE('E52',#1313,#2588,#2586,.T.);
#2590=ORIENTED_EDGE('',*,*,#2589,.T.);
#2591=DIRECTION('',(0.,0.,-1.));
#2592=VECTOR('',#2591,1.);
#2593=CARTESIAN_POINT('',(36.5125,47.6249999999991,228.6));
#2594=LINE('',#2593,#2592);
#2595=CARTESIAN_POINT('',(36.5125,47.6249999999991,228.6));
#2596=VERTEX_POINT('',#2595);
#2597=EDGE_CURVE('E45',#2596,#2588,#2594,.T.);
#2598=ORIENTED_EDGE('',*,*,#2597,.F.);
#2599=DIRECTION('',(1.,0.,0.));
#2600=VECTOR('',#2599,1.);
#2601=CARTESIAN_POINT('',(1.5875,47.6249999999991,228.6));
#2602=LINE('',#2601,#2600);
#2603=EDGE_CURVE('E101',#1321,#2596,#2602,.T.);
#2604=ORIENTED_EDGE('',*,*,#2603,.F.);
#2605=ORIENTED_EDGE('',*,*,#1322,.T.);
#2606=EDGE_LOOP('',(#2590,#2598,#2604,#2605));
#2607=FACE_BOUND('',#2606,.T.);
#2608=ADVANCED_FACE('F103',(#1349,#1360,#1371,#1382,#1393,#1404,#1415,#1426,#1437,#1448,#1459,
#1470,#1481,#1492,#1503,#1514,#1525,#1536,#1547,#1558,#1569,#1580,#1591,#1602,#1613,#1624,#1635,
#1646,#1657,#1668,#1679,#1690,#1701,#1712,#1723,#1734,#1745,#1756,#1767,#1778,#1789,#1800,#1811,
#1822,#1833,#1844,#1855,#1866,#1877,#1888,#1899,#1910,#1921,#1932,#1943,#1954,#1965,#1976,#1987,
#1998,#2009,#2020,#2031,#2042,#2053,#2064,#2075,#2086,#2097,#2108,#2119,#2130,#2141,#2152,#2163,
#2174,#2185,#2196,#2207,#2218,#2229,#2240,#2251,#2262,#2273,#2284,#2295,#2306,#2317,#2328,#2339,
#2350,#2361,#2372,#2383,#2394,#2405,#2416,#2427,#2438,#2449,#2460,#2471,#2482,#2493,#2504,#2515,
#2526,#2537,#2548,#2582,#2607),#1338,.F.);
#2609=CARTESIAN_POINT('',(36.5125,50.7999999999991,228.6));
#2610=DIRECTION('',(-1.,0.,0.));
#2611=DIRECTION('',(0.,0.,1.));
#2612=AXIS2_PLACEMENT_3D('',#2609,#2610,#2611);
#2613=PLANE('',#2612);
#2614=DIRECTION('',(0.,1.,0.));
#2615=VECTOR('',#2614,1.);
#2616=CARTESIAN_POINT('',(36.5125,50.7999999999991,0.));
#2617=LINE('',#2616,#2615);
#2618=EDGE_CURVE('E124',#2588,#1273,#2617,.T.);
#2619=ORIENTED_EDGE('',*,*,#2618,.T.);
#2620=ORIENTED_EDGE('',*,*,#1298,.F.);
#2621=DIRECTION('',(0.,1.,0.));
#2622=VECTOR('',#2621,1.);
#2623=CARTESIAN_POINT('',(36.5125,50.7999999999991,228.6));
#2624=LINE('',#2623,#2622);
#2625=EDGE_CURVE('E110',#2596,#1291,#2624,.T.);
#2626=ORIENTED_EDGE('',*,*,#2625,.F.);
#2627=ORIENTED_EDGE('',*,*,#2597,.T.);
#2628=EDGE_LOOP('',(#2619,#2620,#2626,#2627));
#2629=FACE_BOUND('',#2628,.T.);
#2630=ADVANCED_FACE('F139',(#2629),#2613,.F.);
#2631=CARTESIAN_POINT('',(0.,0.,228.6));
#2632=DIRECTION('',(0.,0.,-1.));
#2633=DIRECTION('',(-1.,0.,0.));
#2634=AXIS2_PLACEMENT_3D('',#2631,#2632,#2633);
#2635=PLANE('',#2634);
#2636=ORIENTED_EDGE('',*,*,#1328,.T.);
#2637=ORIENTED_EDGE('',*,*,#2603,.T.);
#2638=ORIENTED_EDGE('',*,*,#2625,.T.);
#2639=ORIENTED_EDGE('',*,*,#1292,.T.);
#2640=EDGE_LOOP('',(#2636,#2637,#2638,#2639));
#2641=FACE_BOUND('',#2640,.T.);
#2642=ADVANCED_FACE('F119',(#2641),#2635,.F.);
#2643=CARTESIAN_POINT('',(0.,0.,0.));
#2644=DIRECTION('',(0.,0.,-1.));
#2645=DIRECTION('',(-1.,0.,0.));
#2646=AXIS2_PLACEMENT_3D('',#2643,#2644,#2645);
#2647=PLANE('',#2646);
#2648=ORIENTED_EDGE('',*,*,#2589,.F.);
#2649=ORIENTED_EDGE('',*,*,#1314,.F.);
#2650=ORIENTED_EDGE('',*,*,#1276,.F.);
#2651=ORIENTED_EDGE('',*,*,#2618,.F.);
#2652=EDGE_LOOP('',(#2648,#2649,#2650,#2651));
#2653=FACE_BOUND('',#2652,.T.);
#2654=ADVANCED_FACE('F142',(#2653),#2647,.T.);
#2655=CARTESIAN_POINT('',(18.7325,-50.8010000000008,5.08));
#2656=DIRECTION('',(1.,0.,0.));
#2657=DIRECTION('',(0.,1.,0.));
#2658=AXIS2_PLACEMENT_3D('',#2655,#2656,#2657);
#2659=PLANE('',#2658);
#2660=ORIENTED_EDGE('',*,*,#2565,.T.);
#2661=DIRECTION('',(0.,1.,0.));
#2662=VECTOR('',#2661,1.);
#2663=CARTESIAN_POINT('',(18.7325,-50.8010000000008,157.48));
#2664=LINE('',#2663,#2662);
#2665=EDGE_CURVE('E607',#2554,#1249,#2664,.T.);
#2666=ORIENTED_EDGE('',*,*,#2665,.T.);
#2667=ORIENTED_EDGE('',*,*,#1250,.T.);
#2668=DIRECTION('',(0.,1.,0.));
#2669=VECTOR('',#2668,1.);
#2670=CARTESIAN_POINT('',(18.7325,-50.8010000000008,5.08));
#2671=LINE('',#2670,#2669);
#2672=EDGE_CURVE('E606',#2564,#1239,#2671,.T.);
#2673=ORIENTED_EDGE('',*,*,#2672,.F.);
#2674=EDGE_LOOP('',(#2660,#2666,#2667,#2673));
#2675=FACE_BOUND('',#2674,.T.);
#2676=ADVANCED_FACE('F1166',(#2675),#2659,.F.);
#2677=CARTESIAN_POINT('',(18.7325,-50.8010000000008,157.48));
#2678=DIRECTION('',(0.,0.,1.));
#2679=DIRECTION('',(1.,0.,0.));
#2680=AXIS2_PLACEMENT_3D('',#2677,#2678,#2679);
#2681=PLANE('',#2680);
#2682=ORIENTED_EDGE('',*,*,#2557,.T.);
#2683=DIRECTION('',(0.,1.,0.));
#2684=VECTOR('',#2683,1.);
#2685=CARTESIAN_POINT('',(12.1285,-50.8010000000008,157.48));
#2686=LINE('',#2685,#2684);
#2687=EDGE_CURVE('E609',#2556,#1257,#2686,.T.);
#2688=ORIENTED_EDGE('',*,*,#2687,.T.);
#2689=ORIENTED_EDGE('',*,*,#1258,.T.);
#2690=ORIENTED_EDGE('',*,*,#2665,.F.);
#2691=EDGE_LOOP('',(#2682,#2688,#2689,#2690));
#2692=FACE_BOUND('',#2691,.T.);
#2693=ADVANCED_FACE('F1163',(#2692),#2681,.F.);
#2694=CARTESIAN_POINT('',(12.1285,-50.8010000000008,5.08));
#2695=DIRECTION('',(-1.,0.,0.));
#2696=DIRECTION('',(0.,-1.,0.));
#2697=AXIS2_PLACEMENT_3D('',#2694,#2695,#2696);
#2698=PLANE('',#2697);
#2699=ORIENTED_EDGE('',*,*,#2579,.T.);
#2700=DIRECTION('',(0.,1.,0.));
#2701=VECTOR('',#2700,1.);
#2702=CARTESIAN_POINT('',(12.1285,-50.8010000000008,5.08));
#2703=LINE('',#2702,#2701);
#2704=EDGE_CURVE('E611',#2572,#1241,#2703,.T.);
#2705=ORIENTED_EDGE('',*,*,#2704,.T.);
#2706=ORIENTED_EDGE('',*,*,#1264,.T.);
#2707=ORIENTED_EDGE('',*,*,#2687,.F.);
#2708=EDGE_LOOP('',(#2699,#2705,#2706,#2707));
#2709=FACE_BOUND('',#2708,.T.);
#2710=ADVANCED_FACE('F1157',(#2709),#2698,.F.);
#2711=CARTESIAN_POINT('',(18.7325,-50.8010000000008,5.08));
#2712=DIRECTION('',(0.,0.,-1.));
#2713=DIRECTION('',(-1.,0.,0.));
#2714=AXIS2_PLACEMENT_3D('',#2711,#2712,#2713);
#2715=PLANE('',#2714);
#2716=ORIENTED_EDGE('',*,*,#2573,.T.);
#2717=ORIENTED_EDGE('',*,*,#2672,.T.);
#2718=ORIENTED_EDGE('',*,*,#1242,.T.);
#2719=ORIENTED_EDGE('',*,*,#2704,.F.);
#2720=EDGE_LOOP('',(#2716,#2717,#2718,#2719));
#2721=FACE_BOUND('',#2720,.T.);
#2722=ADVANCED_FACE('F616',(#2721),#2715,.F.);
#2723=CARTESIAN_POINT('',(6.03249999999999,-50.8010000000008,222.25));
#2724=DIRECTION('',(0.,1.,0.));
#2725=DIRECTION('',(-1.,0.,0.));
#2726=AXIS2_PLACEMENT_3D('',#2723,#2724,#2725);
#2727=CYLINDRICAL_SURFACE('',#2726,1.5875);
#2728=ORIENTED_EDGE('',*,*,#1230,.T.);
#2729=EDGE_LOOP('',(#2728));
#2730=FACE_BOUND('',#2729,.T.);
#2731=ORIENTED_EDGE('',*,*,#2545,.T.);
#2732=EDGE_LOOP('',(#2731));
#2733=FACE_BOUND('',#2732,.T.);
#2734=ADVANCED_FACE('F1145',(#2730,#2733),#2727,.F.);
#2735=CARTESIAN_POINT('',(25.0824999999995,-50.8010000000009,82.55));
#2736=DIRECTION('',(0.,1.,0.));
#2737=DIRECTION('',(-1.,0.,0.));
#2738=AXIS2_PLACEMENT_3D('',#2735,#2736,#2737);
#2739=CYLINDRICAL_SURFACE('',#2738,1.5875);
#2740=ORIENTED_EDGE('',*,*,#1219,.T.);
#2741=EDGE_LOOP('',(#2740));
#2742=FACE_BOUND('',#2741,.T.);
#2743=ORIENTED_EDGE('',*,*,#2534,.T.);
#2744=EDGE_LOOP('',(#2743));
#2745=FACE_BOUND('',#2744,.T.);
#2746=ADVANCED_FACE('F1147',(#2742,#2745),#2739,.F.);
#2747=CARTESIAN_POINT('',(31.4324999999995,-50.8010000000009,82.55));
#2748=DIRECTION('',(0.,1.,0.));
#2749=DIRECTION('',(-1.,0.,0.));
#2750=AXIS2_PLACEMENT_3D('',#2747,#2748,#2749);
#2751=CYLINDRICAL_SURFACE('',#2750,1.5875);
#2752=ORIENTED_EDGE('',*,*,#1208,.T.);
#2753=EDGE_LOOP('',(#2752));
#2754=FACE_BOUND('',#2753,.T.);
#2755=ORIENTED_EDGE('',*,*,#2523,.T.);
#2756=EDGE_LOOP('',(#2755));
#2757=FACE_BOUND('',#2756,.T.);
#2758=ADVANCED_FACE('F1154',(#2754,#2757),#2751,.F.);
#2759=CARTESIAN_POINT('',(25.0824999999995,-50.8010000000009,76.2));
#2760=DIRECTION('',(0.,1.,0.));
#2761=DIRECTION('',(-1.,0.,0.));
#2762=AXIS2_PLACEMENT_3D('',#2759,#2760,#2761);
#2763=CYLINDRICAL_SURFACE('',#2762,1.5875);
#2764=ORIENTED_EDGE('',*,*,#1197,.T.);
#2765=EDGE_LOOP('',(#2764));
#2766=FACE_BOUND('',#2765,.T.);
#2767=ORIENTED_EDGE('',*,*,#2512,.T.);
#2768=EDGE_LOOP('',(#2767));
#2769=FACE_BOUND('',#2768,.T.);
#2770=ADVANCED_FACE('F1230',(#2766,#2769),#2763,.F.);
#2771=CARTESIAN_POINT('',(31.4324999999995,-50.8010000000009,76.2));
#2772=DIRECTION('',(0.,1.,0.));
#2773=DIRECTION('',(-1.,0.,0.));
#2774=AXIS2_PLACEMENT_3D('',#2771,#2772,#2773);
#2775=CYLINDRICAL_SURFACE('',#2774,1.5875);
#2776=ORIENTED_EDGE('',*,*,#1186,.T.);
#2777=EDGE_LOOP('',(#2776));
#2778=FACE_BOUND('',#2777,.T.);
#2779=ORIENTED_EDGE('',*,*,#2501,.T.);
#2780=EDGE_LOOP('',(#2779));
#2781=FACE_BOUND('',#2780,.T.);
#2782=ADVANCED_FACE('F1240',(#2778,#2781),#2775,.F.);
#2783=CARTESIAN_POINT('',(25.0824999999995,-50.8010000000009,69.85));
#2784=DIRECTION('',(0.,1.,0.));
#2785=DIRECTION('',(-1.,0.,0.));
#2786=AXIS2_PLACEMENT_3D('',#2783,#2784,#2785);
#2787=CYLINDRICAL_SURFACE('',#2786,1.5875);
#2788=ORIENTED_EDGE('',*,*,#1175,.T.);
#2789=EDGE_LOOP('',(#2788));
#2790=FACE_BOUND('',#2789,.T.);
#2791=ORIENTED_EDGE('',*,*,#2490,.T.);
#2792=EDGE_LOOP('',(#2791));
#2793=FACE_BOUND('',#2792,.T.);
#2794=ADVANCED_FACE('F1250',(#2790,#2793),#2787,.F.);
#2795=CARTESIAN_POINT('',(31.4324999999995,-50.8010000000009,69.85));
#2796=DIRECTION('',(0.,1.,0.));
#2797=DIRECTION('',(-1.,0.,0.));
#2798=AXIS2_PLACEMENT_3D('',#2795,#2796,#2797);
#2799=CYLINDRICAL_SURFACE('',#2798,1.5875);
#2800=ORIENTED_EDGE('',*,*,#1164,.T.);
#2801=EDGE_LOOP('',(#2800));
#2802=FACE_BOUND('',#2801,.T.);
#2803=ORIENTED_EDGE('',*,*,#2479,.T.);
#2804=EDGE_LOOP('',(#2803));
#2805=FACE_BOUND('',#2804,.T.);
#2806=ADVANCED_FACE('F1260',(#2802,#2805),#2799,.F.);
#2807=CARTESIAN_POINT('',(25.0824999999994,-50.8010000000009,63.5));
#2808=DIRECTION('',(0.,1.,0.));
#2809=DIRECTION('',(-1.,0.,0.));
#2810=AXIS2_PLACEMENT_3D('',#2807,#2808,#2809);
#2811=CYLINDRICAL_SURFACE('',#2810,1.5875);
#2812=ORIENTED_EDGE('',*,*,#1153,.T.);
#2813=EDGE_LOOP('',(#2812));
#2814=FACE_BOUND('',#2813,.T.);
#2815=ORIENTED_EDGE('',*,*,#2468,.T.);
#2816=EDGE_LOOP('',(#2815));
#2817=FACE_BOUND('',#2816,.T.);
#2818=ADVANCED_FACE('F1270',(#2814,#2817),#2811,.F.);
#2819=CARTESIAN_POINT('',(31.4324999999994,-50.8010000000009,63.5));
#2820=DIRECTION('',(0.,1.,0.));
#2821=DIRECTION('',(-1.,0.,0.));
#2822=AXIS2_PLACEMENT_3D('',#2819,#2820,#2821);
#2823=CYLINDRICAL_SURFACE('',#2822,1.5875);
#2824=ORIENTED_EDGE('',*,*,#1142,.T.);
#2825=EDGE_LOOP('',(#2824));
#2826=FACE_BOUND('',#2825,.T.);
#2827=ORIENTED_EDGE('',*,*,#2457,.T.);
#2828=EDGE_LOOP('',(#2827));
#2829=FACE_BOUND('',#2828,.T.);
#2830=ADVANCED_FACE('F1280',(#2826,#2829),#2823,.F.);
#2831=CARTESIAN_POINT('',(25.0824999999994,-50.8010000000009,57.15));
#2832=DIRECTION('',(0.,1.,0.));
#2833=DIRECTION('',(-1.,0.,0.));
#2834=AXIS2_PLACEMENT_3D('',#2831,#2832,#2833);
#2835=CYLINDRICAL_SURFACE('',#2834,1.5875);
#2836=ORIENTED_EDGE('',*,*,#1131,.T.);
#2837=EDGE_LOOP('',(#2836));
#2838=FACE_BOUND('',#2837,.T.);
#2839=ORIENTED_EDGE('',*,*,#2446,.T.);
#2840=EDGE_LOOP('',(#2839));
#2841=FACE_BOUND('',#2840,.T.);
#2842=ADVANCED_FACE('F1290',(#2838,#2841),#2835,.F.);
#2843=CARTESIAN_POINT('',(31.4324999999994,-50.8010000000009,57.15));
#2844=DIRECTION('',(0.,1.,0.));
#2845=DIRECTION('',(-1.,0.,0.));
#2846=AXIS2_PLACEMENT_3D('',#2843,#2844,#2845);
#2847=CYLINDRICAL_SURFACE('',#2846,1.58750000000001);
#2848=ORIENTED_EDGE('',*,*,#1120,.T.);
#2849=EDGE_LOOP('',(#2848));
#2850=FACE_BOUND('',#2849,.T.);
#2851=ORIENTED_EDGE('',*,*,#2435,.T.);
#2852=EDGE_LOOP('',(#2851));
#2853=FACE_BOUND('',#2852,.T.);
#2854=ADVANCED_FACE('F1300',(#2850,#2853),#2847,.F.);
#2855=CARTESIAN_POINT('',(25.0824999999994,-50.8010000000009,50.8));
#2856=DIRECTION('',(0.,1.,0.));
#2857=DIRECTION('',(-1.,0.,0.));
#2858=AXIS2_PLACEMENT_3D('',#2855,#2856,#2857);
#2859=CYLINDRICAL_SURFACE('',#2858,1.5875);
#2860=ORIENTED_EDGE('',*,*,#1109,.T.);
#2861=EDGE_LOOP('',(#2860));
#2862=FACE_BOUND('',#2861,.T.);
#2863=ORIENTED_EDGE('',*,*,#2424,.T.);
#2864=EDGE_LOOP('',(#2863));
#2865=FACE_BOUND('',#2864,.T.);
#2866=ADVANCED_FACE('F1310',(#2862,#2865),#2859,.F.);
#2867=CARTESIAN_POINT('',(31.4324999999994,-50.8010000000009,50.8));
#2868=DIRECTION('',(0.,1.,0.));
#2869=DIRECTION('',(-1.,0.,0.));
#2870=AXIS2_PLACEMENT_3D('',#2867,#2868,#2869);
#2871=CYLINDRICAL_SURFACE('',#2870,1.5875);
#2872=ORIENTED_EDGE('',*,*,#1098,.T.);
#2873=EDGE_LOOP('',(#2872));
#2874=FACE_BOUND('',#2873,.T.);
#2875=ORIENTED_EDGE('',*,*,#2413,.T.);
#2876=EDGE_LOOP('',(#2875));
#2877=FACE_BOUND('',#2876,.T.);
#2878=ADVANCED_FACE('F1320',(#2874,#2877),#2871,.F.);
#2879=CARTESIAN_POINT('',(25.0824999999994,-50.8010000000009,44.45));
#2880=DIRECTION('',(0.,1.,0.));
#2881=DIRECTION('',(-1.,0.,0.));
#2882=AXIS2_PLACEMENT_3D('',#2879,#2880,#2881);
#2883=CYLINDRICAL_SURFACE('',#2882,1.5875);
#2884=ORIENTED_EDGE('',*,*,#1087,.T.);
#2885=EDGE_LOOP('',(#2884));
#2886=FACE_BOUND('',#2885,.T.);
#2887=ORIENTED_EDGE('',*,*,#2402,.T.);
#2888=EDGE_LOOP('',(#2887));
#2889=FACE_BOUND('',#2888,.T.);
#2890=ADVANCED_FACE('F1330',(#2886,#2889),#2883,.F.);
#2891=CARTESIAN_POINT('',(31.4324999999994,-50.8010000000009,44.45));
#2892=DIRECTION('',(0.,1.,0.));
#2893=DIRECTION('',(-1.,0.,0.));
#2894=AXIS2_PLACEMENT_3D('',#2891,#2892,#2893);
#2895=CYLINDRICAL_SURFACE('',#2894,1.5875);
#2896=ORIENTED_EDGE('',*,*,#1076,.T.);
#2897=EDGE_LOOP('',(#2896));
#2898=FACE_BOUND('',#2897,.T.);
#2899=ORIENTED_EDGE('',*,*,#2391,.T.);
#2900=EDGE_LOOP('',(#2899));
#2901=FACE_BOUND('',#2900,.T.);
#2902=ADVANCED_FACE('F1340',(#2898,#2901),#2895,.F.);
#2903=CARTESIAN_POINT('',(25.0824999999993,-50.8010000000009,38.1));
#2904=DIRECTION('',(0.,1.,0.));
#2905=DIRECTION('',(-1.,0.,0.));
#2906=AXIS2_PLACEMENT_3D('',#2903,#2904,#2905);
#2907=CYLINDRICAL_SURFACE('',#2906,1.5875);
#2908=ORIENTED_EDGE('',*,*,#1065,.T.);
#2909=EDGE_LOOP('',(#2908));
#2910=FACE_BOUND('',#2909,.T.);
#2911=ORIENTED_EDGE('',*,*,#2380,.T.);
#2912=EDGE_LOOP('',(#2911));
#2913=FACE_BOUND('',#2912,.T.);
#2914=ADVANCED_FACE('F1350',(#2910,#2913),#2907,.F.);
#2915=CARTESIAN_POINT('',(31.4324999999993,-50.8010000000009,38.1));
#2916=DIRECTION('',(0.,1.,0.));
#2917=DIRECTION('',(-1.,0.,0.));
#2918=AXIS2_PLACEMENT_3D('',#2915,#2916,#2917);
#2919=CYLINDRICAL_SURFACE('',#2918,1.5875);
#2920=ORIENTED_EDGE('',*,*,#1054,.T.);
#2921=EDGE_LOOP('',(#2920));
#2922=FACE_BOUND('',#2921,.T.);
#2923=ORIENTED_EDGE('',*,*,#2369,.T.);
#2924=EDGE_LOOP('',(#2923));
#2925=FACE_BOUND('',#2924,.T.);
#2926=ADVANCED_FACE('F1360',(#2922,#2925),#2919,.F.);
#2927=CARTESIAN_POINT('',(6.03249999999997,-50.8010000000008,215.9));
#2928=DIRECTION('',(0.,1.,0.));
#2929=DIRECTION('',(-1.,0.,0.));
#2930=AXIS2_PLACEMENT_3D('',#2927,#2928,#2929);
#2931=CYLINDRICAL_SURFACE('',#2930,1.5875);
#2932=ORIENTED_EDGE('',*,*,#1043,.T.);
#2933=EDGE_LOOP('',(#2932));
#2934=FACE_BOUND('',#2933,.T.);
#2935=ORIENTED_EDGE('',*,*,#2358,.T.);
#2936=EDGE_LOOP('',(#2935));
#2937=FACE_BOUND('',#2936,.T.);
#2938=ADVANCED_FACE('F1370',(#2934,#2937),#2931,.F.);
#2939=CARTESIAN_POINT('',(6.03249999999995,-50.8010000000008,209.55));
#2940=DIRECTION('',(0.,1.,0.));
#2941=DIRECTION('',(-1.,0.,0.));
#2942=AXIS2_PLACEMENT_3D('',#2939,#2940,#2941);
#2943=CYLINDRICAL_SURFACE('',#2942,1.5875);
#2944=ORIENTED_EDGE('',*,*,#1032,.T.);
#2945=EDGE_LOOP('',(#2944));
#2946=FACE_BOUND('',#2945,.T.);
#2947=ORIENTED_EDGE('',*,*,#2347,.T.);
#2948=EDGE_LOOP('',(#2947));
#2949=FACE_BOUND('',#2948,.T.);
#2950=ADVANCED_FACE('F1380',(#2946,#2949),#2943,.F.);
#2951=CARTESIAN_POINT('',(6.03249999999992,-50.8010000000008,203.2));
#2952=DIRECTION('',(0.,1.,0.));
#2953=DIRECTION('',(-1.,0.,0.));
#2954=AXIS2_PLACEMENT_3D('',#2951,#2952,#2953);
#2955=CYLINDRICAL_SURFACE('',#2954,1.5875);
#2956=ORIENTED_EDGE('',*,*,#1021,.T.);
#2957=EDGE_LOOP('',(#2956));
#2958=FACE_BOUND('',#2957,.T.);
#2959=ORIENTED_EDGE('',*,*,#2336,.T.);
#2960=EDGE_LOOP('',(#2959));
#2961=FACE_BOUND('',#2960,.T.);
#2962=ADVANCED_FACE('F1390',(#2958,#2961),#2955,.F.);
#2963=CARTESIAN_POINT('',(6.0324999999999,-50.8010000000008,196.85));
#2964=DIRECTION('',(0.,1.,0.));
#2965=DIRECTION('',(-1.,0.,0.));
#2966=AXIS2_PLACEMENT_3D('',#2963,#2964,#2965);
#2967=CYLINDRICAL_SURFACE('',#2966,1.5875);
#2968=ORIENTED_EDGE('',*,*,#1010,.T.);
#2969=EDGE_LOOP('',(#2968));
#2970=FACE_BOUND('',#2969,.T.);
#2971=ORIENTED_EDGE('',*,*,#2325,.T.);
#2972=EDGE_LOOP('',(#2971));
#2973=FACE_BOUND('',#2972,.T.);
#2974=ADVANCED_FACE('F1400',(#2970,#2973),#2967,.F.);
#2975=CARTESIAN_POINT('',(6.03249999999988,-50.8010000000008,190.5));
#2976=DIRECTION('',(0.,1.,0.));
#2977=DIRECTION('',(-1.,0.,0.));
#2978=AXIS2_PLACEMENT_3D('',#2975,#2976,#2977);
#2979=CYLINDRICAL_SURFACE('',#2978,1.5875);
#2980=ORIENTED_EDGE('',*,*,#999,.T.);
#2981=EDGE_LOOP('',(#2980));
#2982=FACE_BOUND('',#2981,.T.);
#2983=ORIENTED_EDGE('',*,*,#2314,.T.);
#2984=EDGE_LOOP('',(#2983));
#2985=FACE_BOUND('',#2984,.T.);
#2986=ADVANCED_FACE('F1410',(#2982,#2985),#2979,.F.);
#2987=CARTESIAN_POINT('',(6.03249999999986,-50.8010000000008,184.15));
#2988=DIRECTION('',(0.,1.,0.));
#2989=DIRECTION('',(-1.,0.,0.));
#2990=AXIS2_PLACEMENT_3D('',#2987,#2988,#2989);
#2991=CYLINDRICAL_SURFACE('',#2990,1.5875);
#2992=ORIENTED_EDGE('',*,*,#988,.T.);
#2993=EDGE_LOOP('',(#2992));
#2994=FACE_BOUND('',#2993,.T.);
#2995=ORIENTED_EDGE('',*,*,#2303,.T.);
#2996=EDGE_LOOP('',(#2995));
#2997=FACE_BOUND('',#2996,.T.);
#2998=ADVANCED_FACE('F1420',(#2994,#2997),#2991,.F.);
#2999=CARTESIAN_POINT('',(6.03249999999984,-50.8010000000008,177.8));
#3000=DIRECTION('',(0.,1.,0.));
#3001=DIRECTION('',(-1.,0.,0.));
#3002=AXIS2_PLACEMENT_3D('',#2999,#3000,#3001);
#3003=CYLINDRICAL_SURFACE('',#3002,1.5875);
#3004=ORIENTED_EDGE('',*,*,#977,.T.);
#3005=EDGE_LOOP('',(#3004));
#3006=FACE_BOUND('',#3005,.T.);
#3007=ORIENTED_EDGE('',*,*,#2292,.T.);
#3008=EDGE_LOOP('',(#3007));
#3009=FACE_BOUND('',#3008,.T.);
#3010=ADVANCED_FACE('F1430',(#3006,#3009),#3003,.F.);
#3011=CARTESIAN_POINT('',(6.03249999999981,-50.8010000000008,171.45));
#3012=DIRECTION('',(0.,1.,0.));
#3013=DIRECTION('',(-1.,0.,0.));
#3014=AXIS2_PLACEMENT_3D('',#3011,#3012,#3013);
#3015=CYLINDRICAL_SURFACE('',#3014,1.5875);
#3016=ORIENTED_EDGE('',*,*,#966,.T.);
#3017=EDGE_LOOP('',(#3016));
#3018=FACE_BOUND('',#3017,.T.);
#3019=ORIENTED_EDGE('',*,*,#2281,.T.);
#3020=EDGE_LOOP('',(#3019));
#3021=FACE_BOUND('',#3020,.T.);
#3022=ADVANCED_FACE('F1440',(#3018,#3021),#3015,.F.);
#3023=CARTESIAN_POINT('',(6.03249999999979,-50.8010000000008,165.1));
#3024=DIRECTION('',(0.,1.,0.));
#3025=DIRECTION('',(-1.,0.,0.));
#3026=AXIS2_PLACEMENT_3D('',#3023,#3024,#3025);
#3027=CYLINDRICAL_SURFACE('',#3026,1.5875);
#3028=ORIENTED_EDGE('',*,*,#955,.T.);
#3029=EDGE_LOOP('',(#3028));
#3030=FACE_BOUND('',#3029,.T.);
#3031=ORIENTED_EDGE('',*,*,#2270,.T.);
#3032=EDGE_LOOP('',(#3031));
#3033=FACE_BOUND('',#3032,.T.);
#3034=ADVANCED_FACE('F1450',(#3030,#3033),#3027,.F.);
#3035=CARTESIAN_POINT('',(6.03249999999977,-50.8010000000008,158.75));
#3036=DIRECTION('',(0.,1.,0.));
#3037=DIRECTION('',(-1.,0.,0.));
#3038=AXIS2_PLACEMENT_3D('',#3035,#3036,#3037);
#3039=CYLINDRICAL_SURFACE('',#3038,1.5875);
#3040=ORIENTED_EDGE('',*,*,#944,.T.);
#3041=EDGE_LOOP('',(#3040));
#3042=FACE_BOUND('',#3041,.T.);
#3043=ORIENTED_EDGE('',*,*,#2259,.T.);
#3044=EDGE_LOOP('',(#3043));
#3045=FACE_BOUND('',#3044,.T.);
#3046=ADVANCED_FACE('F1460',(#3042,#3045),#3039,.F.);
#3047=CARTESIAN_POINT('',(6.03249999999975,-50.8010000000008,152.4));
#3048=DIRECTION('',(0.,1.,0.));
#3049=DIRECTION('',(-1.,0.,0.));
#3050=AXIS2_PLACEMENT_3D('',#3047,#3048,#3049);
#3051=CYLINDRICAL_SURFACE('',#3050,1.5875);
#3052=ORIENTED_EDGE('',*,*,#933,.T.);
#3053=EDGE_LOOP('',(#3052));
#3054=FACE_BOUND('',#3053,.T.);
#3055=ORIENTED_EDGE('',*,*,#2248,.T.);
#3056=EDGE_LOOP('',(#3055));
#3057=FACE_BOUND('',#3056,.T.);
#3058=ADVANCED_FACE('F1470',(#3054,#3057),#3051,.F.);
#3059=CARTESIAN_POINT('',(6.03249999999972,-50.8010000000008,146.05));
#3060=DIRECTION('',(0.,1.,0.));
#3061=DIRECTION('',(-1.,0.,0.));
#3062=AXIS2_PLACEMENT_3D('',#3059,#3060,#3061);
#3063=CYLINDRICAL_SURFACE('',#3062,1.5875);
#3064=ORIENTED_EDGE('',*,*,#922,.T.);
#3065=EDGE_LOOP('',(#3064));
#3066=FACE_BOUND('',#3065,.T.);
#3067=ORIENTED_EDGE('',*,*,#2237,.T.);
#3068=EDGE_LOOP('',(#3067));
#3069=FACE_BOUND('',#3068,.T.);
#3070=ADVANCED_FACE('F1480',(#3066,#3069),#3063,.F.);
#3071=CARTESIAN_POINT('',(6.0324999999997,-50.8010000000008,139.7));
#3072=DIRECTION('',(0.,1.,0.));
#3073=DIRECTION('',(-1.,0.,0.));
#3074=AXIS2_PLACEMENT_3D('',#3071,#3072,#3073);
#3075=CYLINDRICAL_SURFACE('',#3074,1.5875);
#3076=ORIENTED_EDGE('',*,*,#911,.T.);
#3077=EDGE_LOOP('',(#3076));
#3078=FACE_BOUND('',#3077,.T.);
#3079=ORIENTED_EDGE('',*,*,#2226,.T.);
#3080=EDGE_LOOP('',(#3079));
#3081=FACE_BOUND('',#3080,.T.);
#3082=ADVANCED_FACE('F1490',(#3078,#3081),#3075,.F.);
#3083=CARTESIAN_POINT('',(6.03249999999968,-50.8010000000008,133.35));
#3084=DIRECTION('',(0.,1.,0.));
#3085=DIRECTION('',(-1.,0.,0.));
#3086=AXIS2_PLACEMENT_3D('',#3083,#3084,#3085);
#3087=CYLINDRICAL_SURFACE('',#3086,1.5875);
#3088=ORIENTED_EDGE('',*,*,#900,.T.);
#3089=EDGE_LOOP('',(#3088));
#3090=FACE_BOUND('',#3089,.T.);
#3091=ORIENTED_EDGE('',*,*,#2215,.T.);
#3092=EDGE_LOOP('',(#3091));
#3093=FACE_BOUND('',#3092,.T.);
#3094=ADVANCED_FACE('F1500',(#3090,#3093),#3087,.F.);
#3095=CARTESIAN_POINT('',(6.03249999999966,-50.8010000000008,127.));
#3096=DIRECTION('',(0.,1.,0.));
#3097=DIRECTION('',(-1.,0.,0.));
#3098=AXIS2_PLACEMENT_3D('',#3095,#3096,#3097);
#3099=CYLINDRICAL_SURFACE('',#3098,1.5875);
#3100=ORIENTED_EDGE('',*,*,#889,.T.);
#3101=EDGE_LOOP('',(#3100));
#3102=FACE_BOUND('',#3101,.T.);
#3103=ORIENTED_EDGE('',*,*,#2204,.T.);
#3104=EDGE_LOOP('',(#3103));
#3105=FACE_BOUND('',#3104,.T.);
#3106=ADVANCED_FACE('F1510',(#3102,#3105),#3099,.F.);
#3107=CARTESIAN_POINT('',(6.03249999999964,-50.8010000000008,120.65));
#3108=DIRECTION('',(0.,1.,0.));
#3109=DIRECTION('',(-1.,0.,0.));
#3110=AXIS2_PLACEMENT_3D('',#3107,#3108,#3109);
#3111=CYLINDRICAL_SURFACE('',#3110,1.5875);
#3112=ORIENTED_EDGE('',*,*,#878,.T.);
#3113=EDGE_LOOP('',(#3112));
#3114=FACE_BOUND('',#3113,.T.);
#3115=ORIENTED_EDGE('',*,*,#2193,.T.);
#3116=EDGE_LOOP('',(#3115));
#3117=FACE_BOUND('',#3116,.T.);
#3118=ADVANCED_FACE('F1071',(#3114,#3117),#3111,.F.);
#3119=CARTESIAN_POINT('',(6.03249999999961,-50.8010000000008,114.3));
#3120=DIRECTION('',(0.,1.,0.));
#3121=DIRECTION('',(-1.,0.,0.));
#3122=AXIS2_PLACEMENT_3D('',#3119,#3120,#3121);
#3123=CYLINDRICAL_SURFACE('',#3122,1.5875);
#3124=ORIENTED_EDGE('',*,*,#867,.T.);
#3125=EDGE_LOOP('',(#3124));
#3126=FACE_BOUND('',#3125,.T.);
#3127=ORIENTED_EDGE('',*,*,#2182,.T.);
#3128=EDGE_LOOP('',(#3127));
#3129=FACE_BOUND('',#3128,.T.);
#3130=ADVANCED_FACE('F1067',(#3126,#3129),#3123,.F.);
#3131=CARTESIAN_POINT('',(6.03249999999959,-50.8010000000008,107.95));
#3132=DIRECTION('',(0.,1.,0.));
#3133=DIRECTION('',(-1.,0.,0.));
#3134=AXIS2_PLACEMENT_3D('',#3131,#3132,#3133);
#3135=CYLINDRICAL_SURFACE('',#3134,1.5875);
#3136=ORIENTED_EDGE('',*,*,#856,.T.);
#3137=EDGE_LOOP('',(#3136));
#3138=FACE_BOUND('',#3137,.T.);
#3139=ORIENTED_EDGE('',*,*,#2171,.T.);
#3140=EDGE_LOOP('',(#3139));
#3141=FACE_BOUND('',#3140,.T.);
#3142=ADVANCED_FACE('F1070',(#3138,#3141),#3135,.F.);
#3143=CARTESIAN_POINT('',(6.03249999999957,-50.8010000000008,101.6));
#3144=DIRECTION('',(0.,1.,0.));
#3145=DIRECTION('',(-1.,0.,0.));
#3146=AXIS2_PLACEMENT_3D('',#3143,#3144,#3145);
#3147=CYLINDRICAL_SURFACE('',#3146,1.5875);
#3148=ORIENTED_EDGE('',*,*,#845,.T.);
#3149=EDGE_LOOP('',(#3148));
#3150=FACE_BOUND('',#3149,.T.);
#3151=ORIENTED_EDGE('',*,*,#2160,.T.);
#3152=EDGE_LOOP('',(#3151));
#3153=FACE_BOUND('',#3152,.T.);
#3154=ADVANCED_FACE('F1544',(#3150,#3153),#3147,.F.);
#3155=CARTESIAN_POINT('',(6.03249999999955,-50.8010000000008,95.25));
#3156=DIRECTION('',(0.,1.,0.));
#3157=DIRECTION('',(-1.,0.,0.));
#3158=AXIS2_PLACEMENT_3D('',#3155,#3156,#3157);
#3159=CYLINDRICAL_SURFACE('',#3158,1.5875);
#3160=ORIENTED_EDGE('',*,*,#834,.T.);
#3161=EDGE_LOOP('',(#3160));
#3162=FACE_BOUND('',#3161,.T.);
#3163=ORIENTED_EDGE('',*,*,#2149,.T.);
#3164=EDGE_LOOP('',(#3163));
#3165=FACE_BOUND('',#3164,.T.);
#3166=ADVANCED_FACE('F1554',(#3162,#3165),#3159,.F.);
#3167=CARTESIAN_POINT('',(6.03249999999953,-50.8010000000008,88.9));
#3168=DIRECTION('',(0.,1.,0.));
#3169=DIRECTION('',(-1.,0.,0.));
#3170=AXIS2_PLACEMENT_3D('',#3167,#3168,#3169);
#3171=CYLINDRICAL_SURFACE('',#3170,1.5875);
#3172=ORIENTED_EDGE('',*,*,#823,.T.);
#3173=EDGE_LOOP('',(#3172));
#3174=FACE_BOUND('',#3173,.T.);
#3175=ORIENTED_EDGE('',*,*,#2138,.T.);
#3176=EDGE_LOOP('',(#3175));
#3177=FACE_BOUND('',#3176,.T.);
#3178=ADVANCED_FACE('F1564',(#3174,#3177),#3171,.F.);
#3179=CARTESIAN_POINT('',(6.0324999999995,-50.8010000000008,82.55));
#3180=DIRECTION('',(0.,1.,0.));
#3181=DIRECTION('',(-1.,0.,0.));
#3182=AXIS2_PLACEMENT_3D('',#3179,#3180,#3181);
#3183=CYLINDRICAL_SURFACE('',#3182,1.5875);
#3184=ORIENTED_EDGE('',*,*,#812,.T.);
#3185=EDGE_LOOP('',(#3184));
#3186=FACE_BOUND('',#3185,.T.);
#3187=ORIENTED_EDGE('',*,*,#2127,.T.);
#3188=EDGE_LOOP('',(#3187));
#3189=FACE_BOUND('',#3188,.T.);
#3190=ADVANCED_FACE('F1574',(#3186,#3189),#3183,.F.);
#3191=CARTESIAN_POINT('',(6.03249999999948,-50.8010000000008,76.2));
#3192=DIRECTION('',(0.,1.,0.));
#3193=DIRECTION('',(-1.,0.,0.));
#3194=AXIS2_PLACEMENT_3D('',#3191,#3192,#3193);
#3195=CYLINDRICAL_SURFACE('',#3194,1.5875);
#3196=ORIENTED_EDGE('',*,*,#801,.T.);
#3197=EDGE_LOOP('',(#3196));
#3198=FACE_BOUND('',#3197,.T.);
#3199=ORIENTED_EDGE('',*,*,#2116,.T.);
#3200=EDGE_LOOP('',(#3199));
#3201=FACE_BOUND('',#3200,.T.);
#3202=ADVANCED_FACE('F1584',(#3198,#3201),#3195,.F.);
#3203=CARTESIAN_POINT('',(6.03249999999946,-50.8010000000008,69.85));
#3204=DIRECTION('',(0.,1.,0.));
#3205=DIRECTION('',(-1.,0.,0.));
#3206=AXIS2_PLACEMENT_3D('',#3203,#3204,#3205);
#3207=CYLINDRICAL_SURFACE('',#3206,1.5875);
#3208=ORIENTED_EDGE('',*,*,#790,.T.);
#3209=EDGE_LOOP('',(#3208));
#3210=FACE_BOUND('',#3209,.T.);
#3211=ORIENTED_EDGE('',*,*,#2105,.T.);
#3212=EDGE_LOOP('',(#3211));
#3213=FACE_BOUND('',#3212,.T.);
#3214=ADVANCED_FACE('F1594',(#3210,#3213),#3207,.F.);
#3215=CARTESIAN_POINT('',(6.03249999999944,-50.8010000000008,63.5));
#3216=DIRECTION('',(0.,1.,0.));
#3217=DIRECTION('',(-1.,0.,0.));
#3218=AXIS2_PLACEMENT_3D('',#3215,#3216,#3217);
#3219=CYLINDRICAL_SURFACE('',#3218,1.5875);
#3220=ORIENTED_EDGE('',*,*,#779,.T.);
#3221=EDGE_LOOP('',(#3220));
#3222=FACE_BOUND('',#3221,.T.);
#3223=ORIENTED_EDGE('',*,*,#2094,.T.);
#3224=EDGE_LOOP('',(#3223));
#3225=FACE_BOUND('',#3224,.T.);
#3226=ADVANCED_FACE('F1604',(#3222,#3225),#3219,.F.);
#3227=CARTESIAN_POINT('',(6.03249999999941,-50.8010000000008,57.15));
#3228=DIRECTION('',(0.,1.,0.));
#3229=DIRECTION('',(-1.,0.,0.));
#3230=AXIS2_PLACEMENT_3D('',#3227,#3228,#3229);
#3231=CYLINDRICAL_SURFACE('',#3230,1.5875);
#3232=ORIENTED_EDGE('',*,*,#768,.T.);
#3233=EDGE_LOOP('',(#3232));
#3234=FACE_BOUND('',#3233,.T.);
#3235=ORIENTED_EDGE('',*,*,#2083,.T.);
#3236=EDGE_LOOP('',(#3235));
#3237=FACE_BOUND('',#3236,.T.);
#3238=ADVANCED_FACE('F1614',(#3234,#3237),#3231,.F.);
#3239=CARTESIAN_POINT('',(6.03249999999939,-50.8010000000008,50.8));
#3240=DIRECTION('',(0.,1.,0.));
#3241=DIRECTION('',(-1.,0.,0.));
#3242=AXIS2_PLACEMENT_3D('',#3239,#3240,#3241);
#3243=CYLINDRICAL_SURFACE('',#3242,1.5875);
#3244=ORIENTED_EDGE('',*,*,#757,.T.);
#3245=EDGE_LOOP('',(#3244));
#3246=FACE_BOUND('',#3245,.T.);
#3247=ORIENTED_EDGE('',*,*,#2072,.T.);
#3248=EDGE_LOOP('',(#3247));
#3249=FACE_BOUND('',#3248,.T.);
#3250=ADVANCED_FACE('F1624',(#3246,#3249),#3243,.F.);
#3251=CARTESIAN_POINT('',(6.03249999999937,-50.8010000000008,44.45));
#3252=DIRECTION('',(0.,1.,0.));
#3253=DIRECTION('',(-1.,0.,0.));
#3254=AXIS2_PLACEMENT_3D('',#3251,#3252,#3253);
#3255=CYLINDRICAL_SURFACE('',#3254,1.5875);
#3256=ORIENTED_EDGE('',*,*,#746,.T.);
#3257=EDGE_LOOP('',(#3256));
#3258=FACE_BOUND('',#3257,.T.);
#3259=ORIENTED_EDGE('',*,*,#2061,.T.);
#3260=EDGE_LOOP('',(#3259));
#3261=FACE_BOUND('',#3260,.T.);
#3262=ADVANCED_FACE('F1634',(#3258,#3261),#3255,.F.);
#3263=CARTESIAN_POINT('',(6.03249999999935,-50.8010000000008,38.1));
#3264=DIRECTION('',(0.,1.,0.));
#3265=DIRECTION('',(-1.,0.,0.));
#3266=AXIS2_PLACEMENT_3D('',#3263,#3264,#3265);
#3267=CYLINDRICAL_SURFACE('',#3266,1.5875);
#3268=ORIENTED_EDGE('',*,*,#735,.T.);
#3269=EDGE_LOOP('',(#3268));
#3270=FACE_BOUND('',#3269,.T.);
#3271=ORIENTED_EDGE('',*,*,#2050,.T.);
#3272=EDGE_LOOP('',(#3271));
#3273=FACE_BOUND('',#3272,.T.);
#3274=ADVANCED_FACE('F1644',(#3270,#3273),#3267,.F.);
#3275=CARTESIAN_POINT('',(31.4324999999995,-50.8010000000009,88.9));
#3276=DIRECTION('',(0.,1.,0.));
#3277=DIRECTION('',(-1.,0.,0.));
#3278=AXIS2_PLACEMENT_3D('',#3275,#3276,#3277);
#3279=CYLINDRICAL_SURFACE('',#3278,1.58750000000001);
#3280=ORIENTED_EDGE('',*,*,#724,.T.);
#3281=EDGE_LOOP('',(#3280));
#3282=FACE_BOUND('',#3281,.T.);
#3283=ORIENTED_EDGE('',*,*,#2039,.T.);
#3284=EDGE_LOOP('',(#3283));
#3285=FACE_BOUND('',#3284,.T.);
#3286=ADVANCED_FACE('F1161',(#3282,#3285),#3279,.F.);
#3287=CARTESIAN_POINT('',(25.0824999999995,-50.8010000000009,88.9));
#3288=DIRECTION('',(0.,1.,0.));
#3289=DIRECTION('',(-1.,0.,0.));
#3290=AXIS2_PLACEMENT_3D('',#3287,#3288,#3289);
#3291=CYLINDRICAL_SURFACE('',#3290,1.5875);
#3292=ORIENTED_EDGE('',*,*,#713,.T.);
#3293=EDGE_LOOP('',(#3292));
#3294=FACE_BOUND('',#3293,.T.);
#3295=ORIENTED_EDGE('',*,*,#2028,.T.);
#3296=EDGE_LOOP('',(#3295));
#3297=FACE_BOUND('',#3296,.T.);
#3298=ADVANCED_FACE('F1663',(#3294,#3297),#3291,.F.);
#3299=CARTESIAN_POINT('',(31.4324999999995,-50.8010000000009,95.25));
#3300=DIRECTION('',(0.,1.,0.));
#3301=DIRECTION('',(-1.,0.,0.));
#3302=AXIS2_PLACEMENT_3D('',#3299,#3300,#3301);
#3303=CYLINDRICAL_SURFACE('',#3302,1.5875);
#3304=ORIENTED_EDGE('',*,*,#702,.T.);
#3305=EDGE_LOOP('',(#3304));
#3306=FACE_BOUND('',#3305,.T.);
#3307=ORIENTED_EDGE('',*,*,#2017,.T.);
#3308=EDGE_LOOP('',(#3307));
#3309=FACE_BOUND('',#3308,.T.);
#3310=ADVANCED_FACE('F1672',(#3306,#3309),#3303,.F.);
#3311=CARTESIAN_POINT('',(25.0824999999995,-50.8010000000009,95.25));
#3312=DIRECTION('',(0.,1.,0.));
#3313=DIRECTION('',(-1.,0.,0.));
#3314=AXIS2_PLACEMENT_3D('',#3311,#3312,#3313);
#3315=CYLINDRICAL_SURFACE('',#3314,1.5875);
#3316=ORIENTED_EDGE('',*,*,#691,.T.);
#3317=EDGE_LOOP('',(#3316));
#3318=FACE_BOUND('',#3317,.T.);
#3319=ORIENTED_EDGE('',*,*,#2006,.T.);
#3320=EDGE_LOOP('',(#3319));
#3321=FACE_BOUND('',#3320,.T.);
#3322=ADVANCED_FACE('F1681',(#3318,#3321),#3315,.F.);
#3323=CARTESIAN_POINT('',(31.4324999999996,-50.8010000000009,101.6));
#3324=DIRECTION('',(0.,1.,0.));
#3325=DIRECTION('',(-1.,0.,0.));
#3326=AXIS2_PLACEMENT_3D('',#3323,#3324,#3325);
#3327=CYLINDRICAL_SURFACE('',#3326,1.5875);
#3328=ORIENTED_EDGE('',*,*,#680,.T.);
#3329=EDGE_LOOP('',(#3328));
#3330=FACE_BOUND('',#3329,.T.);
#3331=ORIENTED_EDGE('',*,*,#1995,.T.);
#3332=EDGE_LOOP('',(#3331));
#3333=FACE_BOUND('',#3332,.T.);
#3334=ADVANCED_FACE('F1691',(#3330,#3333),#3327,.F.);
#3335=CARTESIAN_POINT('',(25.0824999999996,-50.8010000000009,101.6));
#3336=DIRECTION('',(0.,1.,0.));
#3337=DIRECTION('',(-1.,0.,0.));
#3338=AXIS2_PLACEMENT_3D('',#3335,#3336,#3337);
#3339=CYLINDRICAL_SURFACE('',#3338,1.5875);
#3340=ORIENTED_EDGE('',*,*,#669,.T.);
#3341=EDGE_LOOP('',(#3340));
#3342=FACE_BOUND('',#3341,.T.);
#3343=ORIENTED_EDGE('',*,*,#1984,.T.);
#3344=EDGE_LOOP('',(#3343));
#3345=FACE_BOUND('',#3344,.T.);
#3346=ADVANCED_FACE('F1701',(#3342,#3345),#3339,.F.);
#3347=CARTESIAN_POINT('',(31.4324999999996,-50.8010000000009,107.95));
#3348=DIRECTION('',(0.,1.,0.));
#3349=DIRECTION('',(-1.,0.,0.));
#3350=AXIS2_PLACEMENT_3D('',#3347,#3348,#3349);
#3351=CYLINDRICAL_SURFACE('',#3350,1.5875);
#3352=ORIENTED_EDGE('',*,*,#658,.T.);
#3353=EDGE_LOOP('',(#3352));
#3354=FACE_BOUND('',#3353,.T.);
#3355=ORIENTED_EDGE('',*,*,#1973,.T.);
#3356=EDGE_LOOP('',(#3355));
#3357=FACE_BOUND('',#3356,.T.);
#3358=ADVANCED_FACE('F1711',(#3354,#3357),#3351,.F.);
#3359=CARTESIAN_POINT('',(25.0824999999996,-50.8010000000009,107.95));
#3360=DIRECTION('',(0.,1.,0.));
#3361=DIRECTION('',(-1.,0.,0.));
#3362=AXIS2_PLACEMENT_3D('',#3359,#3360,#3361);
#3363=CYLINDRICAL_SURFACE('',#3362,1.5875);
#3364=ORIENTED_EDGE('',*,*,#647,.T.);
#3365=EDGE_LOOP('',(#3364));
#3366=FACE_BOUND('',#3365,.T.);
#3367=ORIENTED_EDGE('',*,*,#1962,.T.);
#3368=EDGE_LOOP('',(#3367));
#3369=FACE_BOUND('',#3368,.T.);
#3370=ADVANCED_FACE('F1721',(#3366,#3369),#3363,.F.);
#3371=CARTESIAN_POINT('',(31.4324999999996,-50.8010000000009,114.3));
#3372=DIRECTION('',(0.,1.,0.));
#3373=DIRECTION('',(-1.,0.,0.));
#3374=AXIS2_PLACEMENT_3D('',#3371,#3372,#3373);
#3375=CYLINDRICAL_SURFACE('',#3374,1.5875);
#3376=ORIENTED_EDGE('',*,*,#636,.T.);
#3377=EDGE_LOOP('',(#3376));
#3378=FACE_BOUND('',#3377,.T.);
#3379=ORIENTED_EDGE('',*,*,#1951,.T.);
#3380=EDGE_LOOP('',(#3379));
#3381=FACE_BOUND('',#3380,.T.);
#3382=ADVANCED_FACE('F1731',(#3378,#3381),#3375,.F.);
#3383=CARTESIAN_POINT('',(25.0824999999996,-50.8010000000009,114.3));
#3384=DIRECTION('',(0.,1.,0.));
#3385=DIRECTION('',(-1.,0.,0.));
#3386=AXIS2_PLACEMENT_3D('',#3383,#3384,#3385);
#3387=CYLINDRICAL_SURFACE('',#3386,1.5875);
#3388=ORIENTED_EDGE('',*,*,#625,.T.);
#3389=EDGE_LOOP('',(#3388));
#3390=FACE_BOUND('',#3389,.T.);
#3391=ORIENTED_EDGE('',*,*,#1940,.T.);
#3392=EDGE_LOOP('',(#3391));
#3393=FACE_BOUND('',#3392,.T.);
#3394=ADVANCED_FACE('F1741',(#3390,#3393),#3387,.F.);
#3395=CARTESIAN_POINT('',(31.4324999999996,-50.8010000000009,120.65));
#3396=DIRECTION('',(0.,1.,0.));
#3397=DIRECTION('',(-1.,0.,0.));
#3398=AXIS2_PLACEMENT_3D('',#3395,#3396,#3397);
#3399=CYLINDRICAL_SURFACE('',#3398,1.58750000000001);
#3400=ORIENTED_EDGE('',*,*,#614,.T.);
#3401=EDGE_LOOP('',(#3400));
#3402=FACE_BOUND('',#3401,.T.);
#3403=ORIENTED_EDGE('',*,*,#1929,.T.);
#3404=EDGE_LOOP('',(#3403));
#3405=FACE_BOUND('',#3404,.T.);
#3406=ADVANCED_FACE('F1751',(#3402,#3405),#3399,.F.);
#3407=CARTESIAN_POINT('',(25.0824999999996,-50.8010000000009,120.65));
#3408=DIRECTION('',(0.,1.,0.));
#3409=DIRECTION('',(-1.,0.,0.));
#3410=AXIS2_PLACEMENT_3D('',#3407,#3408,#3409);
#3411=CYLINDRICAL_SURFACE('',#3410,1.5875);
#3412=ORIENTED_EDGE('',*,*,#603,.T.);
#3413=EDGE_LOOP('',(#3412));
#3414=FACE_BOUND('',#3413,.T.);
#3415=ORIENTED_EDGE('',*,*,#1918,.T.);
#3416=EDGE_LOOP('',(#3415));
#3417=FACE_BOUND('',#3416,.T.);
#3418=ADVANCED_FACE('F1761',(#3414,#3417),#3411,.F.);
#3419=CARTESIAN_POINT('',(31.4324999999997,-50.8010000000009,127.));
#3420=DIRECTION('',(0.,1.,0.));
#3421=DIRECTION('',(-1.,0.,0.));
#3422=AXIS2_PLACEMENT_3D('',#3419,#3420,#3421);
#3423=CYLINDRICAL_SURFACE('',#3422,1.5875);
#3424=ORIENTED_EDGE('',*,*,#592,.T.);
#3425=EDGE_LOOP('',(#3424));
#3426=FACE_BOUND('',#3425,.T.);
#3427=ORIENTED_EDGE('',*,*,#1907,.T.);
#3428=EDGE_LOOP('',(#3427));
#3429=FACE_BOUND('',#3428,.T.);
#3430=ADVANCED_FACE('F1771',(#3426,#3429),#3423,.F.);
#3431=CARTESIAN_POINT('',(25.0824999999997,-50.8010000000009,127.));
#3432=DIRECTION('',(0.,1.,0.));
#3433=DIRECTION('',(-1.,0.,0.));
#3434=AXIS2_PLACEMENT_3D('',#3431,#3432,#3433);
#3435=CYLINDRICAL_SURFACE('',#3434,1.5875);
#3436=ORIENTED_EDGE('',*,*,#581,.T.);
#3437=EDGE_LOOP('',(#3436));
#3438=FACE_BOUND('',#3437,.T.);
#3439=ORIENTED_EDGE('',*,*,#1896,.T.);
#3440=EDGE_LOOP('',(#3439));
#3441=FACE_BOUND('',#3440,.T.);
#3442=ADVANCED_FACE('F1781',(#3438,#3441),#3435,.F.);
#3443=CARTESIAN_POINT('',(31.4324999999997,-50.8010000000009,133.35));
#3444=DIRECTION('',(0.,1.,0.));
#3445=DIRECTION('',(-1.,0.,0.));
#3446=AXIS2_PLACEMENT_3D('',#3443,#3444,#3445);
#3447=CYLINDRICAL_SURFACE('',#3446,1.5875);
#3448=ORIENTED_EDGE('',*,*,#570,.T.);
#3449=EDGE_LOOP('',(#3448));
#3450=FACE_BOUND('',#3449,.T.);
#3451=ORIENTED_EDGE('',*,*,#1885,.T.);
#3452=EDGE_LOOP('',(#3451));
#3453=FACE_BOUND('',#3452,.T.);
#3454=ADVANCED_FACE('F1791',(#3450,#3453),#3447,.F.);
#3455=CARTESIAN_POINT('',(25.0824999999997,-50.8010000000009,133.35));
#3456=DIRECTION('',(0.,1.,0.));
#3457=DIRECTION('',(-1.,0.,0.));
#3458=AXIS2_PLACEMENT_3D('',#3455,#3456,#3457);
#3459=CYLINDRICAL_SURFACE('',#3458,1.5875);
#3460=ORIENTED_EDGE('',*,*,#559,.T.);
#3461=EDGE_LOOP('',(#3460));
#3462=FACE_BOUND('',#3461,.T.);
#3463=ORIENTED_EDGE('',*,*,#1874,.T.);
#3464=EDGE_LOOP('',(#3463));
#3465=FACE_BOUND('',#3464,.T.);
#3466=ADVANCED_FACE('F1801',(#3462,#3465),#3459,.F.);
#3467=CARTESIAN_POINT('',(31.4324999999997,-50.8010000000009,139.7));
#3468=DIRECTION('',(0.,1.,0.));
#3469=DIRECTION('',(-1.,0.,0.));
#3470=AXIS2_PLACEMENT_3D('',#3467,#3468,#3469);
#3471=CYLINDRICAL_SURFACE('',#3470,1.5875);
#3472=ORIENTED_EDGE('',*,*,#548,.T.);
#3473=EDGE_LOOP('',(#3472));
#3474=FACE_BOUND('',#3473,.T.);
#3475=ORIENTED_EDGE('',*,*,#1863,.T.);
#3476=EDGE_LOOP('',(#3475));
#3477=FACE_BOUND('',#3476,.T.);
#3478=ADVANCED_FACE('F1811',(#3474,#3477),#3471,.F.);
#3479=CARTESIAN_POINT('',(25.0824999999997,-50.8010000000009,139.7));
#3480=DIRECTION('',(0.,1.,0.));
#3481=DIRECTION('',(-1.,0.,0.));
#3482=AXIS2_PLACEMENT_3D('',#3479,#3480,#3481);
#3483=CYLINDRICAL_SURFACE('',#3482,1.5875);
#3484=ORIENTED_EDGE('',*,*,#537,.T.);
#3485=EDGE_LOOP('',(#3484));
#3486=FACE_BOUND('',#3485,.T.);
#3487=ORIENTED_EDGE('',*,*,#1852,.T.);
#3488=EDGE_LOOP('',(#3487));
#3489=FACE_BOUND('',#3488,.T.);
#3490=ADVANCED_FACE('F1821',(#3486,#3489),#3483,.F.);
#3491=CARTESIAN_POINT('',(31.4324999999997,-50.8010000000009,146.05));
#3492=DIRECTION('',(0.,1.,0.));
#3493=DIRECTION('',(-1.,0.,0.));
#3494=AXIS2_PLACEMENT_3D('',#3491,#3492,#3493);
#3495=CYLINDRICAL_SURFACE('',#3494,1.5875);
#3496=ORIENTED_EDGE('',*,*,#526,.T.);
#3497=EDGE_LOOP('',(#3496));
#3498=FACE_BOUND('',#3497,.T.);
#3499=ORIENTED_EDGE('',*,*,#1841,.T.);
#3500=EDGE_LOOP('',(#3499));
#3501=FACE_BOUND('',#3500,.T.);
#3502=ADVANCED_FACE('F1831',(#3498,#3501),#3495,.F.);
#3503=CARTESIAN_POINT('',(25.0824999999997,-50.8010000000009,146.05));
#3504=DIRECTION('',(0.,1.,0.));
#3505=DIRECTION('',(-1.,0.,0.));
#3506=AXIS2_PLACEMENT_3D('',#3503,#3504,#3505);
#3507=CYLINDRICAL_SURFACE('',#3506,1.5875);
#3508=ORIENTED_EDGE('',*,*,#515,.T.);
#3509=EDGE_LOOP('',(#3508));
#3510=FACE_BOUND('',#3509,.T.);
#3511=ORIENTED_EDGE('',*,*,#1830,.T.);
#3512=EDGE_LOOP('',(#3511));
#3513=FACE_BOUND('',#3512,.T.);
#3514=ADVANCED_FACE('F1841',(#3510,#3513),#3507,.F.);
#3515=CARTESIAN_POINT('',(31.4324999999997,-50.8010000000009,152.4));
#3516=DIRECTION('',(0.,1.,0.));
#3517=DIRECTION('',(-1.,0.,0.));
#3518=AXIS2_PLACEMENT_3D('',#3515,#3516,#3517);
#3519=CYLINDRICAL_SURFACE('',#3518,1.58750000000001);
#3520=ORIENTED_EDGE('',*,*,#504,.T.);
#3521=EDGE_LOOP('',(#3520));
#3522=FACE_BOUND('',#3521,.T.);
#3523=ORIENTED_EDGE('',*,*,#1819,.T.);
#3524=EDGE_LOOP('',(#3523));
#3525=FACE_BOUND('',#3524,.T.);
#3526=ADVANCED_FACE('F1851',(#3522,#3525),#3519,.F.);
#3527=CARTESIAN_POINT('',(25.0824999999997,-50.8010000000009,152.4));
#3528=DIRECTION('',(0.,1.,0.));
#3529=DIRECTION('',(-1.,0.,0.));
#3530=AXIS2_PLACEMENT_3D('',#3527,#3528,#3529);
#3531=CYLINDRICAL_SURFACE('',#3530,1.5875);
#3532=ORIENTED_EDGE('',*,*,#493,.T.);
#3533=EDGE_LOOP('',(#3532));
#3534=FACE_BOUND('',#3533,.T.);
#3535=ORIENTED_EDGE('',*,*,#1808,.T.);
#3536=EDGE_LOOP('',(#3535));
#3537=FACE_BOUND('',#3536,.T.);
#3538=ADVANCED_FACE('F1861',(#3534,#3537),#3531,.F.);
#3539=CARTESIAN_POINT('',(31.4324999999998,-50.8010000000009,158.75));
#3540=DIRECTION('',(0.,1.,0.));
#3541=DIRECTION('',(-1.,0.,0.));
#3542=AXIS2_PLACEMENT_3D('',#3539,#3540,#3541);
#3543=CYLINDRICAL_SURFACE('',#3542,1.5875);
#3544=ORIENTED_EDGE('',*,*,#482,.T.);
#3545=EDGE_LOOP('',(#3544));
#3546=FACE_BOUND('',#3545,.T.);
#3547=ORIENTED_EDGE('',*,*,#1797,.T.);
#3548=EDGE_LOOP('',(#3547));
#3549=FACE_BOUND('',#3548,.T.);
#3550=ADVANCED_FACE('F1871',(#3546,#3549),#3543,.F.);
#3551=CARTESIAN_POINT('',(25.0824999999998,-50.8010000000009,158.75));
#3552=DIRECTION('',(0.,1.,0.));
#3553=DIRECTION('',(-1.,0.,0.));
#3554=AXIS2_PLACEMENT_3D('',#3551,#3552,#3553);
#3555=CYLINDRICAL_SURFACE('',#3554,1.5875);
#3556=ORIENTED_EDGE('',*,*,#471,.T.);
#3557=EDGE_LOOP('',(#3556));
#3558=FACE_BOUND('',#3557,.T.);
#3559=ORIENTED_EDGE('',*,*,#1786,.T.);
#3560=EDGE_LOOP('',(#3559));
#3561=FACE_BOUND('',#3560,.T.);
#3562=ADVANCED_FACE('F1881',(#3558,#3561),#3555,.F.);
#3563=CARTESIAN_POINT('',(31.4324999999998,-50.8010000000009,165.1));
#3564=DIRECTION('',(0.,1.,0.));
#3565=DIRECTION('',(-1.,0.,0.));
#3566=AXIS2_PLACEMENT_3D('',#3563,#3564,#3565);
#3567=CYLINDRICAL_SURFACE('',#3566,1.58750000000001);
#3568=ORIENTED_EDGE('',*,*,#460,.T.);
#3569=EDGE_LOOP('',(#3568));
#3570=FACE_BOUND('',#3569,.T.);
#3571=ORIENTED_EDGE('',*,*,#1775,.T.);
#3572=EDGE_LOOP('',(#3571));
#3573=FACE_BOUND('',#3572,.T.);
#3574=ADVANCED_FACE('F1891',(#3570,#3573),#3567,.F.);
#3575=CARTESIAN_POINT('',(25.0824999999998,-50.8010000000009,165.1));
#3576=DIRECTION('',(0.,1.,0.));
#3577=DIRECTION('',(-1.,0.,0.));
#3578=AXIS2_PLACEMENT_3D('',#3575,#3576,#3577);
#3579=CYLINDRICAL_SURFACE('',#3578,1.5875);
#3580=ORIENTED_EDGE('',*,*,#449,.T.);
#3581=EDGE_LOOP('',(#3580));
#3582=FACE_BOUND('',#3581,.T.);
#3583=ORIENTED_EDGE('',*,*,#1764,.T.);
#3584=EDGE_LOOP('',(#3583));
#3585=FACE_BOUND('',#3584,.T.);
#3586=ADVANCED_FACE('F1901',(#3582,#3585),#3579,.F.);
#3587=CARTESIAN_POINT('',(18.7324999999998,-50.8010000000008,165.1));
#3588=DIRECTION('',(0.,1.,0.));
#3589=DIRECTION('',(-1.,0.,0.));
#3590=AXIS2_PLACEMENT_3D('',#3587,#3588,#3589);
#3591=CYLINDRICAL_SURFACE('',#3590,1.5875);
#3592=ORIENTED_EDGE('',*,*,#438,.T.);
#3593=EDGE_LOOP('',(#3592));
#3594=FACE_BOUND('',#3593,.T.);
#3595=ORIENTED_EDGE('',*,*,#1753,.T.);
#3596=EDGE_LOOP('',(#3595));
#3597=FACE_BOUND('',#3596,.T.);
#3598=ADVANCED_FACE('F1911',(#3594,#3597),#3591,.F.);
#3599=CARTESIAN_POINT('',(12.3824999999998,-50.8010000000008,165.1));
#3600=DIRECTION('',(0.,1.,0.));
#3601=DIRECTION('',(-1.,0.,0.));
#3602=AXIS2_PLACEMENT_3D('',#3599,#3600,#3601);
#3603=CYLINDRICAL_SURFACE('',#3602,1.5875);
#3604=ORIENTED_EDGE('',*,*,#427,.T.);
#3605=EDGE_LOOP('',(#3604));
#3606=FACE_BOUND('',#3605,.T.);
#3607=ORIENTED_EDGE('',*,*,#1742,.T.);
#3608=EDGE_LOOP('',(#3607));
#3609=FACE_BOUND('',#3608,.T.);
#3610=ADVANCED_FACE('F1921',(#3606,#3609),#3603,.F.);
#3611=CARTESIAN_POINT('',(31.4324999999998,-50.8010000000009,171.45));
#3612=DIRECTION('',(0.,1.,0.));
#3613=DIRECTION('',(-1.,0.,0.));
#3614=AXIS2_PLACEMENT_3D('',#3611,#3612,#3613);
#3615=CYLINDRICAL_SURFACE('',#3614,1.5875);
#3616=ORIENTED_EDGE('',*,*,#416,.T.);
#3617=EDGE_LOOP('',(#3616));
#3618=FACE_BOUND('',#3617,.T.);
#3619=ORIENTED_EDGE('',*,*,#1731,.T.);
#3620=EDGE_LOOP('',(#3619));
#3621=FACE_BOUND('',#3620,.T.);
#3622=ADVANCED_FACE('F1931',(#3618,#3621),#3615,.F.);
#3623=CARTESIAN_POINT('',(25.0824999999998,-50.8010000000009,171.45));
#3624=DIRECTION('',(0.,1.,0.));
#3625=DIRECTION('',(-1.,0.,0.));
#3626=AXIS2_PLACEMENT_3D('',#3623,#3624,#3625);
#3627=CYLINDRICAL_SURFACE('',#3626,1.5875);
#3628=ORIENTED_EDGE('',*,*,#405,.T.);
#3629=EDGE_LOOP('',(#3628));
#3630=FACE_BOUND('',#3629,.T.);
#3631=ORIENTED_EDGE('',*,*,#1720,.T.);
#3632=EDGE_LOOP('',(#3631));
#3633=FACE_BOUND('',#3632,.T.);
#3634=ADVANCED_FACE('F1941',(#3630,#3633),#3627,.F.);
#3635=CARTESIAN_POINT('',(18.7324999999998,-50.8010000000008,171.45));
#3636=DIRECTION('',(0.,1.,0.));
#3637=DIRECTION('',(-1.,0.,0.));
#3638=AXIS2_PLACEMENT_3D('',#3635,#3636,#3637);
#3639=CYLINDRICAL_SURFACE('',#3638,1.5875);
#3640=ORIENTED_EDGE('',*,*,#394,.T.);
#3641=EDGE_LOOP('',(#3640));
#3642=FACE_BOUND('',#3641,.T.);
#3643=ORIENTED_EDGE('',*,*,#1709,.T.);
#3644=EDGE_LOOP('',(#3643));
#3645=FACE_BOUND('',#3644,.T.);
#3646=ADVANCED_FACE('F1951',(#3642,#3645),#3639,.F.);
#3647=CARTESIAN_POINT('',(12.3824999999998,-50.8010000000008,171.45));
#3648=DIRECTION('',(0.,1.,0.));
#3649=DIRECTION('',(-1.,0.,0.));
#3650=AXIS2_PLACEMENT_3D('',#3647,#3648,#3649);
#3651=CYLINDRICAL_SURFACE('',#3650,1.5875);
#3652=ORIENTED_EDGE('',*,*,#383,.T.);
#3653=EDGE_LOOP('',(#3652));
#3654=FACE_BOUND('',#3653,.T.);
#3655=ORIENTED_EDGE('',*,*,#1698,.T.);
#3656=EDGE_LOOP('',(#3655));
#3657=FACE_BOUND('',#3656,.T.);
#3658=ADVANCED_FACE('F1961',(#3654,#3657),#3651,.F.);
#3659=CARTESIAN_POINT('',(31.4324999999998,-50.8010000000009,177.8));
#3660=DIRECTION('',(0.,1.,0.));
#3661=DIRECTION('',(-1.,0.,0.));
#3662=AXIS2_PLACEMENT_3D('',#3659,#3660,#3661);
#3663=CYLINDRICAL_SURFACE('',#3662,1.5875);
#3664=ORIENTED_EDGE('',*,*,#372,.T.);
#3665=EDGE_LOOP('',(#3664));
#3666=FACE_BOUND('',#3665,.T.);
#3667=ORIENTED_EDGE('',*,*,#1687,.T.);
#3668=EDGE_LOOP('',(#3667));
#3669=FACE_BOUND('',#3668,.T.);
#3670=ADVANCED_FACE('F1971',(#3666,#3669),#3663,.F.);
#3671=CARTESIAN_POINT('',(25.0824999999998,-50.8010000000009,177.8));
#3672=DIRECTION('',(0.,1.,0.));
#3673=DIRECTION('',(-1.,0.,0.));
#3674=AXIS2_PLACEMENT_3D('',#3671,#3672,#3673);
#3675=CYLINDRICAL_SURFACE('',#3674,1.5875);
#3676=ORIENTED_EDGE('',*,*,#361,.T.);
#3677=EDGE_LOOP('',(#3676));
#3678=FACE_BOUND('',#3677,.T.);
#3679=ORIENTED_EDGE('',*,*,#1676,.T.);
#3680=EDGE_LOOP('',(#3679));
#3681=FACE_BOUND('',#3680,.T.);
#3682=ADVANCED_FACE('F1981',(#3678,#3681),#3675,.F.);
#3683=CARTESIAN_POINT('',(18.7324999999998,-50.8010000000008,177.8));
#3684=DIRECTION('',(0.,1.,0.));
#3685=DIRECTION('',(-1.,0.,0.));
#3686=AXIS2_PLACEMENT_3D('',#3683,#3684,#3685);
#3687=CYLINDRICAL_SURFACE('',#3686,1.5875);
#3688=ORIENTED_EDGE('',*,*,#350,.T.);
#3689=EDGE_LOOP('',(#3688));
#3690=FACE_BOUND('',#3689,.T.);
#3691=ORIENTED_EDGE('',*,*,#1665,.T.);
#3692=EDGE_LOOP('',(#3691));
#3693=FACE_BOUND('',#3692,.T.);
#3694=ADVANCED_FACE('F1991',(#3690,#3693),#3687,.F.);
#3695=CARTESIAN_POINT('',(12.3824999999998,-50.8010000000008,177.8));
#3696=DIRECTION('',(0.,1.,0.));
#3697=DIRECTION('',(-1.,0.,0.));
#3698=AXIS2_PLACEMENT_3D('',#3695,#3696,#3697);
#3699=CYLINDRICAL_SURFACE('',#3698,1.5875);
#3700=ORIENTED_EDGE('',*,*,#339,.T.);
#3701=EDGE_LOOP('',(#3700));
#3702=FACE_BOUND('',#3701,.T.);
#3703=ORIENTED_EDGE('',*,*,#1654,.T.);
#3704=EDGE_LOOP('',(#3703));
#3705=FACE_BOUND('',#3704,.T.);
#3706=ADVANCED_FACE('F2001',(#3702,#3705),#3699,.F.);
#3707=CARTESIAN_POINT('',(31.4324999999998,-50.8010000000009,184.15));
#3708=DIRECTION('',(0.,1.,0.));
#3709=DIRECTION('',(-1.,0.,0.));
#3710=AXIS2_PLACEMENT_3D('',#3707,#3708,#3709);
#3711=CYLINDRICAL_SURFACE('',#3710,1.58750000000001);
#3712=ORIENTED_EDGE('',*,*,#328,.T.);
#3713=EDGE_LOOP('',(#3712));
#3714=FACE_BOUND('',#3713,.T.);
#3715=ORIENTED_EDGE('',*,*,#1643,.T.);
#3716=EDGE_LOOP('',(#3715));
#3717=FACE_BOUND('',#3716,.T.);
#3718=ADVANCED_FACE('F2011',(#3714,#3717),#3711,.F.);
#3719=CARTESIAN_POINT('',(25.0824999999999,-50.8010000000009,184.15));
#3720=DIRECTION('',(0.,1.,0.));
#3721=DIRECTION('',(-1.,0.,0.));
#3722=AXIS2_PLACEMENT_3D('',#3719,#3720,#3721);
#3723=CYLINDRICAL_SURFACE('',#3722,1.5875);
#3724=ORIENTED_EDGE('',*,*,#317,.T.);
#3725=EDGE_LOOP('',(#3724));
#3726=FACE_BOUND('',#3725,.T.);
#3727=ORIENTED_EDGE('',*,*,#1632,.T.);
#3728=EDGE_LOOP('',(#3727));
#3729=FACE_BOUND('',#3728,.T.);
#3730=ADVANCED_FACE('F2021',(#3726,#3729),#3723,.F.);
#3731=CARTESIAN_POINT('',(18.7324999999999,-50.8010000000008,184.15));
#3732=DIRECTION('',(0.,1.,0.));
#3733=DIRECTION('',(-1.,0.,0.));
#3734=AXIS2_PLACEMENT_3D('',#3731,#3732,#3733);
#3735=CYLINDRICAL_SURFACE('',#3734,1.5875);
#3736=ORIENTED_EDGE('',*,*,#306,.T.);
#3737=EDGE_LOOP('',(#3736));
#3738=FACE_BOUND('',#3737,.T.);
#3739=ORIENTED_EDGE('',*,*,#1621,.T.);
#3740=EDGE_LOOP('',(#3739));
#3741=FACE_BOUND('',#3740,.T.);
#3742=ADVANCED_FACE('F2031',(#3738,#3741),#3735,.F.);
#3743=CARTESIAN_POINT('',(12.3824999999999,-50.8010000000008,184.15));
#3744=DIRECTION('',(0.,1.,0.));
#3745=DIRECTION('',(-1.,0.,0.));
#3746=AXIS2_PLACEMENT_3D('',#3743,#3744,#3745);
#3747=CYLINDRICAL_SURFACE('',#3746,1.5875);
#3748=ORIENTED_EDGE('',*,*,#295,.T.);
#3749=EDGE_LOOP('',(#3748));
#3750=FACE_BOUND('',#3749,.T.);
#3751=ORIENTED_EDGE('',*,*,#1610,.T.);
#3752=EDGE_LOOP('',(#3751));
#3753=FACE_BOUND('',#3752,.T.);
#3754=ADVANCED_FACE('F2041',(#3750,#3753),#3747,.F.);
#3755=CARTESIAN_POINT('',(31.4324999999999,-50.8010000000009,190.5));
#3756=DIRECTION('',(0.,1.,0.));
#3757=DIRECTION('',(-1.,0.,0.));
#3758=AXIS2_PLACEMENT_3D('',#3755,#3756,#3757);
#3759=CYLINDRICAL_SURFACE('',#3758,1.5875);
#3760=ORIENTED_EDGE('',*,*,#284,.T.);
#3761=EDGE_LOOP('',(#3760));
#3762=FACE_BOUND('',#3761,.T.);
#3763=ORIENTED_EDGE('',*,*,#1599,.T.);
#3764=EDGE_LOOP('',(#3763));
#3765=FACE_BOUND('',#3764,.T.);
#3766=ADVANCED_FACE('F2051',(#3762,#3765),#3759,.F.);
#3767=CARTESIAN_POINT('',(25.0824999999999,-50.8010000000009,190.5));
#3768=DIRECTION('',(0.,1.,0.));
#3769=DIRECTION('',(-1.,0.,0.));
#3770=AXIS2_PLACEMENT_3D('',#3767,#3768,#3769);
#3771=CYLINDRICAL_SURFACE('',#3770,1.5875);
#3772=ORIENTED_EDGE('',*,*,#273,.T.);
#3773=EDGE_LOOP('',(#3772));
#3774=FACE_BOUND('',#3773,.T.);
#3775=ORIENTED_EDGE('',*,*,#1588,.T.);
#3776=EDGE_LOOP('',(#3775));
#3777=FACE_BOUND('',#3776,.T.);
#3778=ADVANCED_FACE('F2061',(#3774,#3777),#3771,.F.);
#3779=CARTESIAN_POINT('',(18.7324999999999,-50.8010000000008,190.5));
#3780=DIRECTION('',(0.,1.,0.));
#3781=DIRECTION('',(-1.,0.,0.));
#3782=AXIS2_PLACEMENT_3D('',#3779,#3780,#3781);
#3783=CYLINDRICAL_SURFACE('',#3782,1.5875);
#3784=ORIENTED_EDGE('',*,*,#262,.T.);
#3785=EDGE_LOOP('',(#3784));
#3786=FACE_BOUND('',#3785,.T.);
#3787=ORIENTED_EDGE('',*,*,#1577,.T.);
#3788=EDGE_LOOP('',(#3787));
#3789=FACE_BOUND('',#3788,.T.);
#3790=ADVANCED_FACE('F2071',(#3786,#3789),#3783,.F.);
#3791=CARTESIAN_POINT('',(12.3824999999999,-50.8010000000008,190.5));
#3792=DIRECTION('',(0.,1.,0.));
#3793=DIRECTION('',(-1.,0.,0.));
#3794=AXIS2_PLACEMENT_3D('',#3791,#3792,#3793);
#3795=CYLINDRICAL_SURFACE('',#3794,1.5875);
#3796=ORIENTED_EDGE('',*,*,#251,.T.);
#3797=EDGE_LOOP('',(#3796));
#3798=FACE_BOUND('',#3797,.T.);
#3799=ORIENTED_EDGE('',*,*,#1566,.T.);
#3800=EDGE_LOOP('',(#3799));
#3801=FACE_BOUND('',#3800,.T.);
#3802=ADVANCED_FACE('F2081',(#3798,#3801),#3795,.F.);
#3803=CARTESIAN_POINT('',(31.4324999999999,-50.8010000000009,196.85));
#3804=DIRECTION('',(0.,1.,0.));
#3805=DIRECTION('',(-1.,0.,0.));
#3806=AXIS2_PLACEMENT_3D('',#3803,#3804,#3805);
#3807=CYLINDRICAL_SURFACE('',#3806,1.58750000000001);
#3808=ORIENTED_EDGE('',*,*,#240,.T.);
#3809=EDGE_LOOP('',(#3808));
#3810=FACE_BOUND('',#3809,.T.);
#3811=ORIENTED_EDGE('',*,*,#1555,.T.);
#3812=EDGE_LOOP('',(#3811));
#3813=FACE_BOUND('',#3812,.T.);
#3814=ADVANCED_FACE('F2091',(#3810,#3813),#3807,.F.);
#3815=CARTESIAN_POINT('',(25.0824999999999,-50.8010000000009,196.85));
#3816=DIRECTION('',(0.,1.,0.));
#3817=DIRECTION('',(-1.,0.,0.));
#3818=AXIS2_PLACEMENT_3D('',#3815,#3816,#3817);
#3819=CYLINDRICAL_SURFACE('',#3818,1.5875);
#3820=ORIENTED_EDGE('',*,*,#229,.T.);
#3821=EDGE_LOOP('',(#3820));
#3822=FACE_BOUND('',#3821,.T.);
#3823=ORIENTED_EDGE('',*,*,#1544,.T.);
#3824=EDGE_LOOP('',(#3823));
#3825=FACE_BOUND('',#3824,.T.);
#3826=ADVANCED_FACE('F2101',(#3822,#3825),#3819,.F.);
#3827=CARTESIAN_POINT('',(18.7324999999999,-50.8010000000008,196.85));
#3828=DIRECTION('',(0.,1.,0.));
#3829=DIRECTION('',(-1.,0.,0.));
#3830=AXIS2_PLACEMENT_3D('',#3827,#3828,#3829);
#3831=CYLINDRICAL_SURFACE('',#3830,1.5875);
#3832=ORIENTED_EDGE('',*,*,#218,.T.);
#3833=EDGE_LOOP('',(#3832));
#3834=FACE_BOUND('',#3833,.T.);
#3835=ORIENTED_EDGE('',*,*,#1533,.T.);
#3836=EDGE_LOOP('',(#3835));
#3837=FACE_BOUND('',#3836,.T.);
#3838=ADVANCED_FACE('F2111',(#3834,#3837),#3831,.F.);
#3839=CARTESIAN_POINT('',(12.3824999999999,-50.8010000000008,196.85));
#3840=DIRECTION('',(0.,1.,0.));
#3841=DIRECTION('',(-1.,0.,0.));
#3842=AXIS2_PLACEMENT_3D('',#3839,#3840,#3841);
#3843=CYLINDRICAL_SURFACE('',#3842,1.5875);
#3844=ORIENTED_EDGE('',*,*,#207,.T.);
#3845=EDGE_LOOP('',(#3844));
#3846=FACE_BOUND('',#3845,.T.);
#3847=ORIENTED_EDGE('',*,*,#1522,.T.);
#3848=EDGE_LOOP('',(#3847));
#3849=FACE_BOUND('',#3848,.T.);
#3850=ADVANCED_FACE('F2121',(#3846,#3849),#3843,.F.);
#3851=CARTESIAN_POINT('',(31.4324999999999,-50.8010000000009,203.2));
#3852=DIRECTION('',(0.,1.,0.));
#3853=DIRECTION('',(-1.,0.,0.));
#3854=AXIS2_PLACEMENT_3D('',#3851,#3852,#3853);
#3855=CYLINDRICAL_SURFACE('',#3854,1.5875);
#3856=ORIENTED_EDGE('',*,*,#196,.T.);
#3857=EDGE_LOOP('',(#3856));
#3858=FACE_BOUND('',#3857,.T.);
#3859=ORIENTED_EDGE('',*,*,#1511,.T.);
#3860=EDGE_LOOP('',(#3859));
#3861=FACE_BOUND('',#3860,.T.);
#3862=ADVANCED_FACE('F2131',(#3858,#3861),#3855,.F.);
#3863=CARTESIAN_POINT('',(25.0824999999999,-50.8010000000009,203.2));
#3864=DIRECTION('',(0.,1.,0.));
#3865=DIRECTION('',(-1.,0.,0.));
#3866=AXIS2_PLACEMENT_3D('',#3863,#3864,#3865);
#3867=CYLINDRICAL_SURFACE('',#3866,1.5875);
#3868=ORIENTED_EDGE('',*,*,#185,.T.);
#3869=EDGE_LOOP('',(#3868));
#3870=FACE_BOUND('',#3869,.T.);
#3871=ORIENTED_EDGE('',*,*,#1500,.T.);
#3872=EDGE_LOOP('',(#3871));
#3873=FACE_BOUND('',#3872,.T.);
#3874=ADVANCED_FACE('F2141',(#3870,#3873),#3867,.F.);
#3875=CARTESIAN_POINT('',(18.7324999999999,-50.8010000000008,203.2));
#3876=DIRECTION('',(0.,1.,0.));
#3877=DIRECTION('',(-1.,0.,0.));
#3878=AXIS2_PLACEMENT_3D('',#3875,#3876,#3877);
#3879=CYLINDRICAL_SURFACE('',#3878,1.5875);
#3880=ORIENTED_EDGE('',*,*,#174,.T.);
#3881=EDGE_LOOP('',(#3880));
#3882=FACE_BOUND('',#3881,.T.);
#3883=ORIENTED_EDGE('',*,*,#1489,.T.);
#3884=EDGE_LOOP('',(#3883));
#3885=FACE_BOUND('',#3884,.T.);
#3886=ADVANCED_FACE('F2151',(#3882,#3885),#3879,.F.);
#3887=CARTESIAN_POINT('',(12.3824999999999,-50.8010000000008,203.2));
#3888=DIRECTION('',(0.,1.,0.));
#3889=DIRECTION('',(-1.,0.,0.));
#3890=AXIS2_PLACEMENT_3D('',#3887,#3888,#3889);
#3891=CYLINDRICAL_SURFACE('',#3890,1.5875);
#3892=ORIENTED_EDGE('',*,*,#163,.T.);
#3893=EDGE_LOOP('',(#3892));
#3894=FACE_BOUND('',#3893,.T.);
#3895=ORIENTED_EDGE('',*,*,#1478,.T.);
#3896=EDGE_LOOP('',(#3895));
#3897=FACE_BOUND('',#3896,.T.);
#3898=ADVANCED_FACE('F2161',(#3894,#3897),#3891,.F.);
#3899=CARTESIAN_POINT('',(31.4324999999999,-50.8010000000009,209.55));
#3900=DIRECTION('',(0.,1.,0.));
#3901=DIRECTION('',(-1.,0.,0.));
#3902=AXIS2_PLACEMENT_3D('',#3899,#3900,#3901);
#3903=CYLINDRICAL_SURFACE('',#3902,1.5875);
#3904=ORIENTED_EDGE('',*,*,#152,.T.);
#3905=EDGE_LOOP('',(#3904));
#3906=FACE_BOUND('',#3905,.T.);
#3907=ORIENTED_EDGE('',*,*,#1467,.T.);
#3908=EDGE_LOOP('',(#3907));
#3909=FACE_BOUND('',#3908,.T.);
#3910=ADVANCED_FACE('F2171',(#3906,#3909),#3903,.F.);
#3911=CARTESIAN_POINT('',(25.0824999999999,-50.8010000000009,209.55));
#3912=DIRECTION('',(0.,1.,0.));
#3913=DIRECTION('',(-1.,0.,0.));
#3914=AXIS2_PLACEMENT_3D('',#3911,#3912,#3913);
#3915=CYLINDRICAL_SURFACE('',#3914,1.5875);
#3916=ORIENTED_EDGE('',*,*,#141,.T.);
#3917=EDGE_LOOP('',(#3916));
#3918=FACE_BOUND('',#3917,.T.);
#3919=ORIENTED_EDGE('',*,*,#1456,.T.);
#3920=EDGE_LOOP('',(#3919));
#3921=FACE_BOUND('',#3920,.T.);
#3922=ADVANCED_FACE('F2181',(#3918,#3921),#3915,.F.);
#3923=CARTESIAN_POINT('',(18.7324999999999,-50.8010000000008,209.55));
#3924=DIRECTION('',(0.,1.,0.));
#3925=DIRECTION('',(-1.,0.,0.));
#3926=AXIS2_PLACEMENT_3D('',#3923,#3924,#3925);
#3927=CYLINDRICAL_SURFACE('',#3926,1.5875);
#3928=ORIENTED_EDGE('',*,*,#130,.T.);
#3929=EDGE_LOOP('',(#3928));
#3930=FACE_BOUND('',#3929,.T.);
#3931=ORIENTED_EDGE('',*,*,#1445,.T.);
#3932=EDGE_LOOP('',(#3931));
#3933=FACE_BOUND('',#3932,.T.);
#3934=ADVANCED_FACE('F2191',(#3930,#3933),#3927,.F.);
#3935=CARTESIAN_POINT('',(12.3824999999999,-50.8010000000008,209.55));
#3936=DIRECTION('',(0.,1.,0.));
#3937=DIRECTION('',(-1.,0.,0.));
#3938=AXIS2_PLACEMENT_3D('',#3935,#3936,#3937);
#3939=CYLINDRICAL_SURFACE('',#3938,1.5875);
#3940=ORIENTED_EDGE('',*,*,#119,.T.);
#3941=EDGE_LOOP('',(#3940));
#3942=FACE_BOUND('',#3941,.T.);
#3943=ORIENTED_EDGE('',*,*,#1434,.T.);
#3944=EDGE_LOOP('',(#3943));
#3945=FACE_BOUND('',#3944,.T.);
#3946=ADVANCED_FACE('F2201',(#3942,#3945),#3939,.F.);
#3947=CARTESIAN_POINT('',(31.4325,-50.8010000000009,215.9));
#3948=DIRECTION('',(0.,1.,0.));
#3949=DIRECTION('',(-1.,0.,0.));
#3950=AXIS2_PLACEMENT_3D('',#3947,#3948,#3949);
#3951=CYLINDRICAL_SURFACE('',#3950,1.58750000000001);
#3952=ORIENTED_EDGE('',*,*,#108,.T.);
#3953=EDGE_LOOP('',(#3952));
#3954=FACE_BOUND('',#3953,.T.);
#3955=ORIENTED_EDGE('',*,*,#1423,.T.);
#3956=EDGE_LOOP('',(#3955));
#3957=FACE_BOUND('',#3956,.T.);
#3958=ADVANCED_FACE('F2211',(#3954,#3957),#3951,.F.);
#3959=CARTESIAN_POINT('',(25.0825,-50.8010000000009,215.9));
#3960=DIRECTION('',(0.,1.,0.));
#3961=DIRECTION('',(-1.,0.,0.));
#3962=AXIS2_PLACEMENT_3D('',#3959,#3960,#3961);
#3963=CYLINDRICAL_SURFACE('',#3962,1.5875);
#3964=ORIENTED_EDGE('',*,*,#97,.T.);
#3965=EDGE_LOOP('',(#3964));
#3966=FACE_BOUND('',#3965,.T.);
#3967=ORIENTED_EDGE('',*,*,#1412,.T.);
#3968=EDGE_LOOP('',(#3967));
#3969=FACE_BOUND('',#3968,.T.);
#3970=ADVANCED_FACE('F2221',(#3966,#3969),#3963,.F.);
#3971=CARTESIAN_POINT('',(18.7325,-50.8010000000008,215.9));
#3972=DIRECTION('',(0.,1.,0.));
#3973=DIRECTION('',(-1.,0.,0.));
#3974=AXIS2_PLACEMENT_3D('',#3971,#3972,#3973);
#3975=CYLINDRICAL_SURFACE('',#3974,1.5875);
#3976=ORIENTED_EDGE('',*,*,#86,.T.);
#3977=EDGE_LOOP('',(#3976));
#3978=FACE_BOUND('',#3977,.T.);
#3979=ORIENTED_EDGE('',*,*,#1401,.T.);
#3980=EDGE_LOOP('',(#3979));
#3981=FACE_BOUND('',#3980,.T.);
#3982=ADVANCED_FACE('F2231',(#3978,#3981),#3975,.F.);
#3983=CARTESIAN_POINT('',(12.3825,-50.8010000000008,215.9));
#3984=DIRECTION('',(0.,1.,0.));
#3985=DIRECTION('',(-1.,0.,0.));
#3986=AXIS2_PLACEMENT_3D('',#3983,#3984,#3985);
#3987=CYLINDRICAL_SURFACE('',#3986,1.5875);
#3988=ORIENTED_EDGE('',*,*,#75,.T.);
#3989=EDGE_LOOP('',(#3988));
#3990=FACE_BOUND('',#3989,.T.);
#3991=ORIENTED_EDGE('',*,*,#1390,.T.);
#3992=EDGE_LOOP('',(#3991));
#3993=FACE_BOUND('',#3992,.T.);
#3994=ADVANCED_FACE('F2241',(#3990,#3993),#3987,.F.);
#3995=CARTESIAN_POINT('',(31.4325,-50.8010000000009,222.25));
#3996=DIRECTION('',(0.,1.,0.));
#3997=DIRECTION('',(-1.,0.,0.));
#3998=AXIS2_PLACEMENT_3D('',#3995,#3996,#3997);
#3999=CYLINDRICAL_SURFACE('',#3998,1.5875);
#4000=ORIENTED_EDGE('',*,*,#64,.T.);
#4001=EDGE_LOOP('',(#4000));
#4002=FACE_BOUND('',#4001,.T.);
#4003=ORIENTED_EDGE('',*,*,#1379,.T.);
#4004=EDGE_LOOP('',(#4003));
#4005=FACE_BOUND('',#4004,.T.);
#4006=ADVANCED_FACE('F2251',(#4002,#4005),#3999,.F.);
#4007=CARTESIAN_POINT('',(25.0825,-50.8010000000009,222.25));
#4008=DIRECTION('',(0.,1.,0.));
#4009=DIRECTION('',(-1.,0.,0.));
#4010=AXIS2_PLACEMENT_3D('',#4007,#4008,#4009);
#4011=CYLINDRICAL_SURFACE('',#4010,1.5875);
#4012=ORIENTED_EDGE('',*,*,#53,.T.);
#4013=EDGE_LOOP('',(#4012));
#4014=FACE_BOUND('',#4013,.T.);
#4015=ORIENTED_EDGE('',*,*,#1368,.T.);
#4016=EDGE_LOOP('',(#4015));
#4017=FACE_BOUND('',#4016,.T.);
#4018=ADVANCED_FACE('F2261',(#4014,#4017),#4011,.F.);
#4019=CARTESIAN_POINT('',(18.7325,-50.8010000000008,222.25));
#4020=DIRECTION('',(0.,1.,0.));
#4021=DIRECTION('',(-1.,0.,0.));
#4022=AXIS2_PLACEMENT_3D('',#4019,#4020,#4021);
#4023=CYLINDRICAL_SURFACE('',#4022,1.5875);
#4024=ORIENTED_EDGE('',*,*,#42,.T.);
#4025=EDGE_LOOP('',(#4024));
#4026=FACE_BOUND('',#4025,.T.);
#4027=ORIENTED_EDGE('',*,*,#1357,.T.);
#4028=EDGE_LOOP('',(#4027));
#4029=FACE_BOUND('',#4028,.T.);
#4030=ADVANCED_FACE('F2271',(#4026,#4029),#4023,.F.);
#4031=CARTESIAN_POINT('',(12.3825,-50.8010000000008,222.25));
#4032=DIRECTION('',(0.,1.,0.));
#4033=DIRECTION('',(-1.,0.,0.));
#4034=AXIS2_PLACEMENT_3D('',#4031,#4032,#4033);
#4035=CYLINDRICAL_SURFACE('',#4034,1.5875);
#4036=ORIENTED_EDGE('',*,*,#31,.T.);
#4037=EDGE_LOOP('',(#4036));
#4038=FACE_BOUND('',#4037,.T.);
#4039=ORIENTED_EDGE('',*,*,#1346,.T.);
#4040=EDGE_LOOP('',(#4039));
#4041=FACE_BOUND('',#4040,.T.);
#4042=ADVANCED_FACE('F2281',(#4038,#4041),#4035,.F.);
#4043=CLOSED_SHELL('',(#1302,#1333,#2608,#2630,#2642,#2654,#2676,#2693,#2710,#2722,#2734,#2746,
#2758,#2770,#2782,#2794,#2806,#2818,#2830,#2842,#2854,#2866,#2878,#2890,#2902,#2914,#2926,#2938,
#2950,#2962,#2974,#2986,#2998,#3010,#3022,#3034,#3046,#3058,#3070,#3082,#3094,#3106,#3118,#3130,
#3142,#3154,#3166,#3178,#3190,#3202,#3214,#3226,#3238,#3250,#3262,#3274,#3286,#3298,#3310,#3322,
#3334,#3346,#3358,#3370,#3382,#3394,#3406,#3418,#3430,#3442,#3454,#3466,#3478,#3490,#3502,#3514,
#3526,#3538,#3550,#3562,#3574,#3586,#3598,#3610,#3622,#3634,#3646,#3658,#3670,#3682,#3694,#3706,
#3718,#3730,#3742,#3754,#3766,#3778,#3790,#3802,#3814,#3826,#3838,#3850,#3862,#3874,#3886,#3898,
#3910,#3922,#3934,#3946,#3958,#3970,#3982,#3994,#4006,#4018,#4030,#4042));
#4044=MANIFOLD_SOLID_BREP('B2',#4043);
#4045=ADVANCED_BREP_SHAPE_REPRESENTATION('',(#18,#4044),#14);
#4046=SHAPE_DEFINITION_REPRESENTATION(#9,#4045);
ENDSEC;
END-ISO-10303-21;
